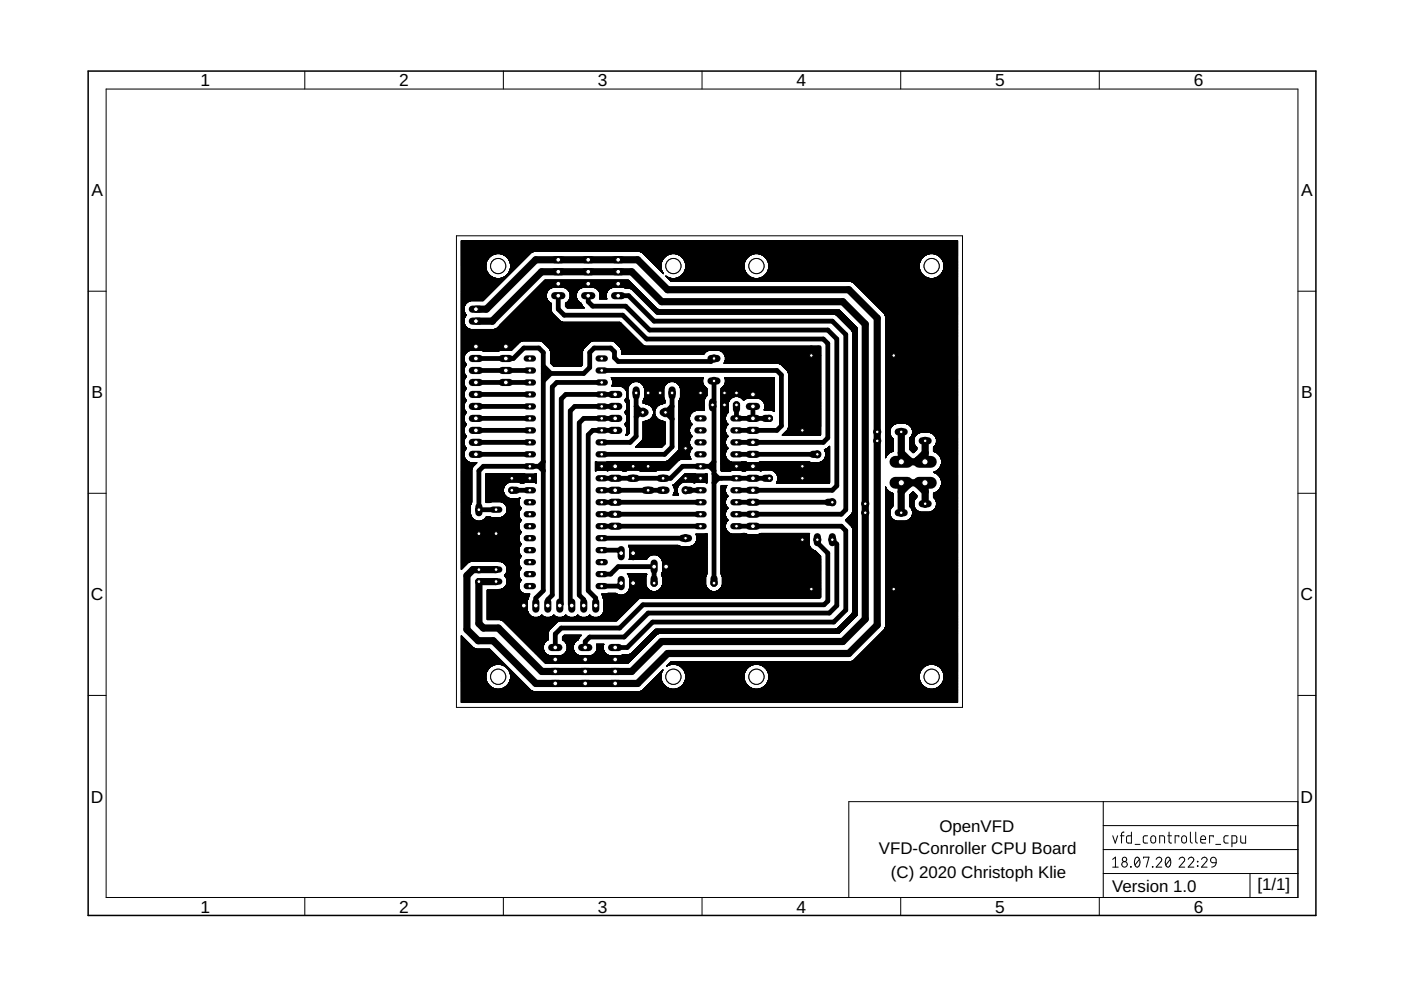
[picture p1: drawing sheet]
<svg xmlns="http://www.w3.org/2000/svg" width="297mm" height="210mm" viewBox="0 0 297 210" stroke-linecap="round" stroke-linejoin="round" font-family="sans-serif">
<defs><g id="words">
<g font-size="3.7">
<text x="42.5" y="18.3">1</text>
<text x="84.7" y="18.3">2</text>
<text x="126.8" y="18.3">3</text>
<text x="168.9" y="18.3">4</text>
<text x="211" y="18.3">5</text>
<text x="253.1" y="18.3">6</text>
<text x="19.4" y="41.6">A</text>
<text x="275.9" y="41.6">A</text>
<text x="19.4" y="84.5">B</text>
<text x="275.9" y="84.5">B</text>
<text x="19.3" y="127.3">C</text>
<text x="275.8" y="127.3">C</text>
<text x="19.3" y="170.2">D</text>
<text x="275.8" y="170.2">D</text>
<text x="42.5" y="193.5">1</text>
<text x="84.7" y="193.5">2</text>
<text x="126.8" y="193.5">3</text>
<text x="168.9" y="193.5">4</text>
<text x="211" y="193.5">5</text>
<text x="253.1" y="193.5">6</text>
</g>
<g font-size="3.6">
<text x="199.2" y="176.3">OpenVFD</text>
<text x="186.3" y="181.1">VFD-Conroller CPU Board</text>
<text x="188.9" y="186.2">(C) 2020 Christoph Klie</text>
<text x="235.8" y="189">Version 1.0</text>
<text x="266.6" y="188.7">[1/1]</text>
</g>
</g></defs>
<g fill="none" stroke="#000" stroke-width=".51">
<circle cx="105.6" cy="56.4" r=".76"/>
<circle cx="142.8" cy="56.4" r=".76"/>
<circle cx="160.3" cy="56.4" r=".76"/>
<circle cx="197.5" cy="56.4" r=".76"/>
<circle cx="105.6" cy="143.5" r=".76"/>
<circle cx="142.8" cy="143.5" r=".76"/>
<circle cx="160.4" cy="143.5" r=".76"/>
<circle cx="197.5" cy="143.4" r=".76"/>
</g>
<g fill="none" stroke="#000" stroke-width="1.5">
<path d="M100.9 68.1h3.5l10.4-10.5h19.1l6.4 6.4h38.4l4.8 4.7v62.6l-4.8 4.7h-38.4l-6.4 6.4h-19l-9.2-9.2h-3.2l-1-1v-8.9h3.7M100.9 65.6h2.2l10.5-10.5h21.6l6.3 6.3h38.5l6 6.1v65l-6 6.1h-38.5l-6.3 6.3h-21.6l-9-9.1h-3.2l-2.4-2.3v-11.5l1.3-1.2h4.9M118.4 60.2h12.7M150.7 76h1.3M133.6 98.9h1.3M134.9 82.7v1.2M135.8 87.4h1M136.8 98.9h1.2M137.4 82.7v1.2M140 82.7v1.2M140.6 87.4h.5M142.5 82.7v1.2"/>
<path d="M145.4 94.4v1.3M148.5 82.7v1.2M150.7 80.8h1.3M151.1 85.2v1.3M153.6 82.7v1.2M153.6 85.2v1.3M155.5 83.3h1.3M156.1 85.9v.9M162.2 88.7h.9M169.5 98.9h1.3M169.5 91.2h1.3M172.3 96.3h1"/>
<path d="M190.4 91.6h1.3M191.1 91.6h.1M191.1 91.6v6.3h5l.1-4.4M191.1 96l1.9 1.9M193 97.9h.1M195.5 93.5h1.3M196.2 96l-2 1.9M101.5 107.4v1.3M101.5 112.5v1.3M107.9 101.4h1.3M108.5 103.9h1M133.6 101.4h1.3"/>
<path d="M136.8 103.9h1.2M140 101.4h1.2M140 103.9h1.2M144.7 114.1h1.3M145.4 101.4h.9M145.4 103.9h.9M162.2 101.4h.9M169.5 101.4h1.3M170.1 113.8v1.3M173.3 113.8v1.3M175.5 106.5h1M176.5 113.8v1.3"/>
<path d="M190.4 108.7h1.3M193 102.4l-1.9 1.9M194.2 102.4l2 1.9M195.5 106.8h1.3M196.2 106.8l-.1-4.4h-5v6.3M117.7 139.8h12.7M138.7 122.7v.9M151.4 122.7v.9"/>
</g>
<g fill="none" stroke="#000" stroke-width="1">
<path d="M100.9 76h7.9l2.3-2.2h3.1l1 .9v50.5l-1.6 1.6v1.6M100.9 73.5h6.4M100.9 78.5h11.4M107.3 68.7h24.1l5.1 5.1h37.1v16.5l-.9 .9h-2.6M107.3 68.7l-4.8 4.8M115.2 77.6l1.6 1.6-1.6 1.6M118.4 62.7v2.9l1.2 1.2h12.4l5.1 5.1h37.5l.9 .9v20l-.9 1h-18.5M118.4 60.2h-2.6l-8.5 8.5M124.7 62.7v1.3l1 .9h7l5 5.1h37.8l1.9 1.9v31.1l-.9 .9h-20.4M127.6 78.5h37.1l1 1v10.8l-1 .9h-8.6M131.1 60.2h2.2l6 6h38.1l3.8 3.8v60.3l-3.5 3.5h-38.4l-6 6h-2.9M131.1 62.7h2.2l5.4 5.4h37.8l2.8 2.8v37.2l-.9 .9h-22.3"/>
<path d="M151.4 76l-.7 .6h-19.6l-.8-.7v-1.3l-.8-.8h-3.5l-1 .9v3.2l-1.2 1.3h-8.6M172 73.8v1.6M172 75.4h1.6M173 74.4l-1 1M100.9 91.2h11.4M100.9 88.7h11.4M100.9 81.1h11.4M100.9 96.3h11.4M100.9 93.8h11.4M100.9 86.2h11.4M100.9 83.6h11.4M114.2 98.9h-11.7l-1 .9v7.6"/>
<path d="M114.2 98.9l1 .9M115.2 97.9l-1 1M127.6 98.9h6M127.6 81.1h-9.6l-.9 .9v44.2l-1 .9v1.3M130.4 91.2h-4.7l-1 1v33l1.6 1.6v1.6M130.4 88.7h-6.6l-1 1v36.5l1 .9v1.3M130.4 86.2h-8.5l-1 .9v41l.3 .3M130.4 83.6h-10.4l-1 1v43.5l-.3 .3M134.9 98.9h1.9M134.9 83.9v8.6l-1.3 1.3h-6M134.9 86.2l1.4 1.2M135.8 87.4l-.9 1"/>
<path d="M137.4 83.3h2.6M137.7 83.3l1-.9 .9 .9M138.7 83.3v-1.9l.9-.9h4.8l1 .9v13.7l-3.9 3.8h-3.5M142.5 83.9v10.8l-1.6 1.6h-13.3M142.5 86.2l-1.4 1.2 1.4 1.4M145.4 82.4l.9 .9-.9 1M146 83.3h2.5M150.4 98.9h-5.7l-2.5 2.5h-1M150.4 98.9l1 .9M151.1 85.9l.3 .3M151.4 97.9l-1 1M151.4 80.8v41.9"/>
<path d="M151.4 85.2l-.3 .3M153.3 85.5l.3 .4-.3 .3M155.5 83.3h-1.9l-.3 .3v14.6l.6 .7h15.6M156.1 86.8v1.9h6.1M156.1 96.3h16.2M156.8 83.3h2.5l.3 .3M159.6 86.2v2.5M170.1 98.9v2.5M101.5 108.1h3.7M105.2 108.1h.1M107.5 113.1l1 1v18.7l7 7h2.2M107.5 113.1l-6 .1"/>
<path d="M108.2 101.4h-1.3l-1.2 1.3v2.2l2.8 2.9v4.1l-1 1v.2M109.2 101.4h3.1M109.5 103.9h2.8M127.6 101.4h6M127.6 106.5h20.9M127.6 109h20.9M127.6 111.6h20.9M127.6 103.9h9.2M127.6 114.1h17.1M127.6 116.6h3.5l.6 .7M134.2 101.4h5.8M134.2 117.3h5.8l1.2 1.3v6.9"/>
<path d="M138 103.9h2M146.3 101.4h2.2M146.3 103.9h2.2M151.4 100.5l.9 .9M152.3 101.4h9.9M152.3 101.4l-.9 1M156.1 106.5h19.4M156.1 111.6h22.3l.9 .9v16.8l-2.5 2.6h-38.4l-5.4 5.4h-2.6M170.1 115.1l3.5 3.5v7.9h-38.4M173.3 115.1l2.2 2.2v10.1l-.8 .8h-38.4l-4.9 5h-12.4l-1.3 1.2v2.9M176.5 114.4l.9 1v13l-1.6 1.6h-38.4l-5.1 5.1h-7.3l-.9 .9v1.3M108.5 128.4h2.6"/>
<path d="M108.5 127.4l1 1-1 .9M108.5 130.3l1 1M109.5 131.3l-1 .9M127.6 121.7h1.9l1.6-1.6h7.6v2.6M131.7 123.6l-.6 .7h-3.5M134.2 125.5l1 1M134.2 123.6v3.8M135.2 126.5l-4.8 4.8h-20.9M141.2 125.5l-.9 1M141.2 125.5l1 1M172 124.9h1.6M172 124.9v1.6"/>
<path d="M172 124.9l1.3 1.3v.3"/>
</g>
<g fill="none" stroke="#000" stroke-width=".21">
<path d="M97.8 59l9.3 .1M97.8 59h7.4M97.8 58.9h7.1M97.8 58.9h7M97.8 58.8h6.8M97.8 58.8h6.7M97.8 58.7h6.6M97.8 58.7h6.5M97.8 58.6h6.4M97.8 58.5l6.3 .1M97.8 58.5h6.2M97.8 58.4l6.2 .1"/>
<path d="M97.8 58.4h6.1M97.8 58.3l6.1 .1M97.8 58.3h6M97.8 58.2l6 .1M97.8 58.2h5.9M97.8 58.1l5.9 .1M97.8 58.1h5.8M97.8 58l5.8 .1M97.8 58h5.7M97.8 57.9l5.7 .1M97.8 57.9h5.6M97.8 57.8h5.6"/>
<path d="M97.8 57.7h5.6M97.8 57.7h5.5M97.8 57.6h5.5M97.8 57.5h5.4M97.8 57.4l5.4 .1M97.8 57.4h5.4M97.8 57.3l5.4 .1M97.8 57.3h5.3M97.8 57.2h5.3M97.8 57.1h5.3M97.8 57h5.3M97.8 56.9h5.2"/>
<path d="M97.8 56.8h5.2M97.8 56.7h5.2M97.8 56.6h5.2M97.8 56.5h5.2M97.8 56.4h5.2M97.8 56.3h5.2M97.8 56.2h5.2M97.8 56.1h5.2M97.8 56h5.2M97.8 55.9h5.2M97.8 55.8h5.3M97.8 55.6h5.3"/>
<path d="M97.8 55.4h5.4M97.8 55.3h5.4M97.8 55.2h5.5M97.8 55h5.6M97.8 53.3h105.2M97.8 53.2h105.2M97.8 53.1h105.2M97.8 53h105.2M97.8 52.9h105.2M97.8 52.8h105.2M97.8 52.7h105.2M97.8 52.6h105.2"/>
<path d="M97.8 52.5h105.2M97.8 52.4h105.2M97.8 52.3h105.2M97.8 52.2h105.2M97.8 52.1h105.2M97.8 52h105.2M97.8 51.9h105.2M97.8 51.8h105.2M97.8 51.7h105.2M97.8 51.6h105.2M97.8 51.5h105.2M97.8 51.4h105.2"/>
<path d="M97.8 51.3h105.2M97.8 51.2h105.2M97.8 51.1h105.2M103 56.1v.7M103 56.8l.2 .6 .8 1.1M103 56h-5.2M103.1 55.9h-5.3M103.1 55.7h-5.3M103.1 55.5l-5.3 .1M103.2 55.5h-5.4M103.2 55.4h-5.4M103.3 55.3h-5.5"/>
<path d="M103.3 55.2h-5.5M103.3 55.1h-5.5M103.4 55.1h-5.6M103.4 54.9l-5.6 .1M103.5 54.9h-5.7M103.5 54.8l-5.7 .1M103.5 54.8l-.5 1.3M103.5 54.8h-5.7M103.6 54.7l-5.8 .1M103.6 54.7h-5.8M103.7 54.6l-5.9 .1M103.7 54.6h-5.9"/>
<path d="M103.8 54.5l-6 .1M103.8 54.5h-6M103.9 54.4l-6.1 .1M103.9 54.4h-6.1M104 54.3l-.5 .5M104 58.5l1.3 .6M104 54.3l-6.2 .1M104.1 54.3h-6.3M104.2 54.2l-6.4 .1M104.3 54.2h-6.5M104.4 54.1h-6.6M104.5 54l-6.7 .1"/>
<path d="M104.6 54h-6.8M104.8 53.9l-7 .1M104.9 53.9h-7.1M105.1 53.8l-7.3 .1M105.3 53.8l-1.3 .5M106 53.8l1.2 .5M106.1 53.8h6.2M106.2 60h-8.4M106.2 59.9l-8.4 .1M106.3 59.9h-8.5M106.3 53.9h6M106.4 59.8l-8.6 .1"/>
<path d="M106.4 59.8h-8.6M106.4 59.7l-8.6 .1M106.5 59.7h-8.7M106.5 53.9h5.7M106.6 59.6h-8.8M106.7 59.5h-8.9M106.7 54h5.5M106.7 54h5.4M106.8 59.4h-9M106.8 58.7h.6M106.8 54.1h5.3M106.9 59.3h-9.1"/>
<path d="M106.9 59.2l-9.1 .1M107 54.2h5M107 59.2h-9.2M107 59.1l-9.2 .1M107.1 54.2h4.9M107.1 59.1h-9.3M107.2 54.3h4.7M107.2 59h-1.1M107.2 54.3l.9 1.1M107.2 58.5l-1.2 .6M107.2 54.3h4.6M107.3 58.9h-1"/>
<path d="M107.3 54.4h4.5M107.3 58.9h-.8M107.3 58.8h-.6M107.4 58.8h-.7M107.4 54.5h4.3M107.4 54.5h4.2M107.5 58.7h-.6M107.5 54.6h4.1M107.5 54.6h4M107.6 58.6h-.6M107.6 54.7h3.9M107.6 58.5l-.5 .1"/>
<path d="M107.7 58.5h-.5M107.7 54.7h3.7M107.7 58.4l-.4 .1M107.7 54.8h3.7M107.8 58.4h-.5M107.8 54.9h3.5M107.8 54.9h3.4M107.8 58.3l-.4 .1M107.8 55h3.3M107.9 57.8h.5M107.9 55.1h3.2M107.9 58.3h-.5"/>
<path d="M107.9 55.2h3.1M107.9 58.2l-.4 .1M108 58.2h-.5M108 55.2h2.9M108 55.3h2.9M108 58.1l-.4 .1M108.1 55.4h2.7M108.1 55.4l.1 .7M108.1 57.4l-.9 1.1M108.1 58.1h-.4M108.1 55.4h2.6M108.1 58l-.4 .1"/>
<path d="M108.1 55.7h2.4M108.2 55.8h2.2M108.2 58h-.5M108.2 56h2M108.2 56.1v.7M108.2 56.8l-.1 .6M108.3 57.9l-.5 .1M108.3 57.9h-.5M108.4 57.8h-.6M108.5 57.7h-.6M108.6 57.6h-.7M108.6 57.6h-.6"/>
<path d="M108.7 57.5h-.7M108.7 57.4l-.6 .1M108.8 57.4h-.7M108.8 57.3l-.7 .1M108.9 57.3h-.8M108.9 57.2l-.8 .1M109 57.2h-.9M109 57.1h-.9M109.1 57.1h-.9M109.2 57h-1M109.2 56.9h-1M109.3 56.9h-1.1"/>
<path d="M109.3 56.8h-1.1M109.4 56.7l-1.2 .1M109.5 56.7h-1.3M109.5 56.6l-1.3 .1M109.6 56.6h-1.4M109.6 56.5l-1.4 .1M109.7 56.5h-1.5M109.7 56.4l-1.5 .1M109.8 56.4h-1.6M109.9 56.3l-1.7 .1M109.9 56.3h-1.7M109.9 56.2l-1.7 .1"/>
<path d="M110 56.2h-1.8M110 56.1l-1.8 .1M110.1 56.1h-1.9M110.2 56h-2M110.3 55.9h-2.1M110.4 55.8h-2.2M110.5 55.6l-2.4 .1M110.6 55.6h-2.5M110.6 55.5l-2.5 .1M110.7 55.5h-2.6M110.8 55.3l-2.8 .1M111.3 54.8l-3.5 .1"/>
<path d="M112.4 53.8h-14.6M112.5 53.7l-14.7 .1M112.5 53.7h-14.7M112.5 53.6l-14.7 .1M112.6 53.6h-14.8M112.6 53.6l-10.2 10.2h-4.6M112.7 53.5l-14.9 .1M112.9 53.5h-15.1M113 53.4h-15.2M113.1 53.4h-15.3M113.3 53.3l-.7 .3M115 60h18.8"/>
<path d="M115 59.9h18.7M115.1 59.9h18.6M115.1 59.8h18.5M115.2 59.8h18.4M115.3 59.7h18.2M115.3 59.6h18.2M115.4 59.6h18M115.4 59.5h17.9M115.5 59.5h17.8M115.5 59.4h17.7M135.6 53.3l.6 .3M135.7 53.4h67.3"/>
<path d="M135.8 53.4h67.2M136 53.5h67M136.1 53.5h66.9M136.2 53.6l4.5 4.4M136.2 53.6h66.8M136.3 53.7h66.7M136.4 53.7h66.6M136.4 53.8h66.6M136.5 53.8h5.8M136.5 53.9h5.5M136.6 53.9h5.3M136.6 54h5.1"/>
<path d="M136.7 54h4.9M136.7 54.1h4.8M136.8 54.2h4.6M136.8 54.2h4.5M136.9 54.3h4.3M137 54.4h4.1M137.1 54.4h4M137.1 54.5h3.9M137.2 54.5h3.7M137.2 54.6h3.7M137.3 54.6h3.5M137.3 54.7h3.5"/>
<path d="M137.4 54.7h3.3M137.4 54.8h3.3M137.5 54.8h3.1M137.5 54.9h3.1M137.6 54.9h3M137.6 55h2.9M137.7 55.1h2.8M137.8 55.1h2.7M137.8 55.2h2.7M137.9 55.2h2.5M137.9 55.3h2.5M138 55.3h2.4"/>
<path d="M138 55.4h2.3M138.1 55.4h2.2M138.1 55.5h2.2M138.2 55.5h2.1M138.2 55.6h2.1M138.3 55.6h2M138.3 55.7h2M138.4 55.8h1.8M138.5 55.9h1.7M138.6 56h1.6M138.7 56.1h1.4M138.8 56.2h1.3"/>
<path d="M138.9 56.2h1.2M138.9 56.3h1.2M139 56.3h1.1M139 56.4h1.1M139.1 56.4h1M139.1 56.5h1M139.2 56.5h.9M139.2 56.6h.9M139.3 56.6h.8M139.3 56.7h.8M139.4 56.7h.7M139.4 56.8h.8"/>
<path d="M139.5 56.9h.7M139.6 56.9h.6M139.6 57h.6M139.7 57h.5M139.7 57.1h.5M139.8 57.1h.5M139.8 57.2h.5M139.9 57.2h.4M139.9 57.3h.4M140 57.3h.3M140 57.4h.3M140.1 57.4h.2"/>
<path d="M140.1 57.5h.3M140.1 56.1v.7M140.1 56.8l.2 .6M140.2 57.6h.2M140.3 57.7h.2M140.3 57.4l.4 .6M140.4 57.8h.1M140.4 57.8h.2M140.5 57.9h.1M140.7 58h.1M140.7 54.8l-.6 1.3M141.2 54.3l-.5 .5"/>
<path d="M141.2 58.5l.1 .1M141.2 58.6h.2M141.3 58.7h.2M141.4 58.7h.1M141.4 58.8h.2M141.5 58.8h.2M141.5 58.9h.4M141.6 58.9h.5M141.6 59h.7M141.7 59l61.3 .1M141.7 59.1h61.3M141.8 59.1h61.2"/>
<path d="M141.8 59.2h61.2M141.9 59.2h61.1M141.9 59.3h61.1M142 59.4h61M142.1 59.5h60.9M142.2 59.6h60.8M142.4 59.1l-1.2-.6 1 1.1h60.8M142.4 53.8l-1.2 .5M143.1 53.8l1.3 .5M143.2 59h16.7M143.3 53.8h16.6M143.4 58.9h16.3"/>
<path d="M143.5 53.9h16.2M143.6 58.9h15.9M143.6 53.9h15.9M143.8 58.8h15.5M143.8 54h15.5M143.9 58.8h15.4M143.9 54h15.4M144 58.7h15.2M144 54.1h15.2M144.1 58.7h15M144.1 54.2h14.9M144.2 58.6h14.8"/>
<path d="M144.2 54.2h14.7M144.3 58.6h14.6M144.3 54.3h14.5M144.4 58.5l-1.3 .6M144.4 54.3l.5 .5M144.4 58.5h14.4M144.4 54.3h14.4M144.4 58.5h14.3M144.4 54.4h14.3M144.5 58.4h14.2M144.5 54.4h14.2M144.5 58.4h14.1"/>
<path d="M144.5 54.5h14.1M144.6 58.3h14M144.6 54.5h14M144.6 58.3h13.9M144.7 54.6h13.8M144.7 58.2h13.8M144.7 58.2h13.7M144.8 54.7h13.6M144.8 58.1h13.5M144.8 54.7h13.5M144.9 54.8l.5 1.3M144.9 54.8h13.4"/>
<path d="M144.9 58h13.4M144.9 54.8h13.3M144.9 58h13.3M144.9 57.9h13.3M144.9 54.9h13.3M145 57.8h13.2M145 55h13.2M145 57.8h13.1M145 55.1h13.1M145 57.7h13.1M145.1 55.1h13M145.1 57.7h13"/>
<path d="M145.1 57.6h13M145.1 57.6h12.9M145.2 57.5h12.8M145.2 55.3h12.8M145.2 57.5h12.7M145.2 55.4h12.7M145.2 57.4l-.8 1.1M145.2 57.4h12.7M145.2 57.3h12.7M145.2 55.5h12.7M145.3 57.2h12.6M145.3 57.1h12.6"/>
<path d="M145.3 55.6h12.6M145.3 57.1h12.5M145.3 57h12.5M145.3 55.9h12.5M145.3 55.8h12.5M145.4 56.9h12.4M145.4 56.8h12.4M145.4 56h12.4M145.4 56.8l-.2 .6M145.4 56.1v.7M145.4 56.7h12.4M145.4 56.6h12.4"/>
<path d="M145.4 56.5h12.4M145.4 56.4h12.4M145.4 56.3h12.4M145.4 56.2h12.4M145.4 56.1h12.4M157.8 56.1v.7M157.8 56.8l.1 .6M157.8 56h-12.4M157.8 55.9h-12.4M157.8 55.8h-12.5M157.9 55.7h-12.6M157.9 55.6h-12.6"/>
<path d="M157.9 57.4l.9 1.1M157.9 55.4l-12.7 .1M158 55.3h-12.9M158 55.2h-12.9M158.1 55.2h-13M158.2 54.9h-13.3M158.3 54.8l-.5 1.3M158.8 54.3l-.5 .5M158.8 58.5l1.2 .6M160 53.8l-1.2 .5M160.7 53.8l1.3 .5M160.8 59h36.3"/>
<path d="M160.9 53.8h36.1M161.1 58.9h35.7M161.1 53.9h35.7M161.2 58.9h35.5M161.2 53.9h35.5M161.4 58.8h35.1M161.4 54h35.1M161.5 58.8h34.9M161.5 54h34.9M161.6 58.7h34.7M161.6 54.1h34.7M161.7 58.7h34.5"/>
<path d="M161.7 54.2h34.5M161.8 58.6h34.3M161.8 54.2h34.3M161.9 58.6h34.1M161.9 54.3h34.1M162 54.3l.5 .5M162 58.5l-1.3 .6M162 58.5h33.9M162 54.3h33.9M162.1 54.4h33.8M162.1 58.4h33.7M162.1 54.4h33.7"/>
<path d="M162.2 54.5h33.5M162.2 58.3h33.5M162.3 54.6h33.3M162.3 58.2h33.3M162.4 54.7h33.1M162.4 58.1h33.1M162.5 54.8l.3 .6M162.5 54.8h32.9M162.5 58h32.9M162.5 54.9h32.8M162.6 57.9h32.7M162.6 54.9h32.7"/>
<path d="M162.6 57.8h32.7M162.6 55h32.7M162.6 55.1h32.7M162.6 57.7h32.7M162.7 57.7h32.5M162.7 57.6h32.5M162.8 57.6h32.4M162.8 55.3h32.4M162.8 57.5h32.3M162.8 57.4l32.3 .1M162.8 55.4l.2 .7M162.8 57.4l-.8 1.1"/>
<path d="M162.8 57.4h32.3M162.8 55.4h32.3M162.9 57.3h32.1M162.9 55.5h32.1M162.9 57.2h32.1M162.9 57.1h32.1M162.9 55.7h32.1M162.9 55.6h32.1M162.9 57h32.1M162.9 55.8h32.1M162.9 57h32M162.9 55.9h32"/>
<path d="M163 56.9h31.9M163 55.9h31.9M163 56.8h31.9M163 56h31.9M163 56.1v.7M163 56.8l-.2 .6M163 56.7l31.9 .1M163 56.7h31.9M163 56.6h31.9M163 56.5h31.9M163 56.4h31.9M163 56.3h31.9"/>
<path d="M163 56.2h31.9M163 56.1h31.9M180.3 59.6l.7 .3M180.4 59.7h22.6M180.5 59.7h22.5M180.6 59.8h22.4M180.7 59.8h22.3M180.9 59.9h22.1M181 59.9l.5 .5M181 59.9h22M181 60h22M194.9 56.1v.7"/>
<path d="M194.9 56.8l.2 .6M195 55.8h-32.1M195 55.6h-32.1M195.1 55.5h-32.2M195.1 57.4l.3 .6M195.1 55.4h-32.3M195.1 55.3l-32.3 .1M195.2 55.2h-32.5M195.2 55.1h-32.5M195.4 54.8l-.5 1.3M195.4 58l.5 .5M195.9 54.3l-.5 .5"/>
<path d="M195.9 58.5l1.3 .6M197.2 53.8l-1.3 .5M197.9 53.8l1.2 .5M198 59h5M198 53.8h5M198.2 58.9h4.8M198.2 53.9h4.8M198.4 58.9h4.6M198.4 53.9h4.6M198.6 58.8h4.4M198.6 54h4.4M198.8 58.7h4.2"/>
<path d="M198.8 54.1h4.2M198.9 54.2h4.1M198.9 58.6h4.1M199 58.6h4M199.1 54.3h3.9M199.1 58.5h3.9M199.1 54.3l.5 .5M199.1 58.5l-1.2 .6M199.2 58.5h3.8M199.2 54.4h3.8M199.2 58.4h3.8M199.3 58.4h3.7"/>
<path d="M199.3 54.5h3.7M199.3 58.3h3.7M199.4 58.3h3.6M199.4 54.6h3.6M199.5 58.2h3.5M199.5 54.6h3.5M199.5 54.7h3.5M199.5 58.1h3.5M199.6 58.1h3.4M199.6 54.8h3.4M199.6 54.8l.6 1.3M199.6 58h3.4"/>
<path d="M199.7 57.9h3.3M199.7 54.9h3.3M199.7 57.8h3.3M199.7 55h3.3M199.8 57.8h3.2M199.8 55.1h3.2M199.8 57.7h3.2M199.8 55.2h3.2M199.9 57.6h3.1M199.9 55.2h3.1M199.9 55.3h3.1M199.9 57.5h3.1"/>
<path d="M199.9 55.4h3.1M200 57.4l-.9 1.1M200 57.4h3M200 57.3h3M200 55.5h3M200 55.4h3M200 57.2h3M200 55.6h3M200 57.1h3M200 55.7h3M200.1 57h2.9M200.1 55.8h2.9"/>
<path d="M200.1 55.9h2.9M200.1 56.9h2.9M200.1 56h2.9M200.1 56.8h2.9M200.2 56.1v.7M200.2 56.8l-.2 .6M200.2 56.7h2.8M200.2 56.6h2.8M200.2 56.5h2.8M200.2 56.4h2.8M200.2 56.3h2.8M200.2 56.2h2.8"/>
<path d="M200.2 56.1h2.8M203 53.3h-105.2M97.8 69.8l35.1 .1M97.8 65.7h.6M97.8 66.5l.9 .1M97.8 65.3h.6M97.8 68.3h.6M97.8 77l.9 .1M97.8 72.3h37.6M97.8 79.8h1.1M97.8 79.7h1M97.8 79.6h.9"/>
<path d="M97.8 79.5l.9 .1M97.8 79.5h.8M97.8 79.4h.8M97.8 79.3h.8M97.8 79.3h.7M97.8 79.2h.7M97.8 79.1h.7M97.8 79.1h.6M97.8 79h.6M97.8 78.9h.6M97.8 78.8h.6M97.8 78.7h.6"/>
<path d="M97.8 78.6h.6M97.8 78.5h.6M97.8 78.4h.6M97.8 78.3h.6M97.8 78.2h.6M97.8 78.1h.6M97.8 78h.7M97.8 77.9h.7M97.8 77.7h.8M97.8 77.3h1.1M97.8 77.2h1.1M97.8 77.2h1"/>
<path d="M97.8 77.1h.9M97.8 77h.9M97.8 76.9l.8 .1M97.8 76.9h.8M97.8 76.8h.8M97.8 76.7h.7M97.8 76.6h.7M97.8 76.5h.6M97.8 76.4h.6M97.8 76.3h.6M97.8 76.2h.6M97.8 76.1h.6"/>
<path d="M97.8 76h.6M97.8 75.9h.6M97.8 75.8h.6M97.8 75.7h.6M97.8 75.6h.6M97.8 75.5h.6M97.8 75.5h.7M97.8 75.4h.7M97.8 75.3h.7M97.8 75.2h.8M97.8 72.2l37.5 .1M97.8 72.2h37.5"/>
<path d="M97.8 72.1l37.4 .1M97.8 72.1h37.3M97.8 72l37.3 .1M97.8 72h37.2M97.8 71.9h37.2M97.8 71.9h37.1M97.8 71.8h37.1M97.8 71.8h37M97.8 71.7h37M97.8 71.6l36.9 .1M97.8 71.6h36.9M97.8 71.5l36.8 .1"/>
<path d="M97.8 71.5h36.8M97.8 71.4l36.7 .1M97.8 71.4h36.7M97.8 71.3l36.6 .1M97.8 71.3h36.6M97.8 71.2h36.5M97.8 71.1h36.4M97.8 71h36.3M97.8 71h36.2M97.8 70.9h36.2M97.8 70.8l36.1 .1M97.8 70.8h36.1"/>
<path d="M97.8 70.7l36 .1M97.8 70.7h36M97.8 70.6l35.9 .1M97.8 70.6h35.9M97.8 70.5l35.8 .1M97.8 70.5h35.8M97.8 70.4l35.7 .1M97.8 70.4h35.7M97.8 70.3l35.6 .1M97.8 70.3h35.5M97.8 70.2l35.5 .1M97.8 70.2h35.4"/>
<path d="M97.8 70.1h35.4M97.8 70.1h35.3M97.8 70h35.3M97.8 70h35.2M97.8 69.9h35.2M97.8 69.8h1.9M97.8 69.7l1.8 .1M97.8 69.7h1.7M97.8 69.6l1.5 .1M97.8 69.6h1.4M97.8 69.5l1.3 .1M97.8 69.5h1.3"/>
<path d="M97.8 69.4h1.2M97.8 69.3h1.1M97.8 69.2h1M97.8 69.2h.9M97.8 69.1h.9M97.8 69l.9 .1M97.8 69h.8M97.8 68.9l.8 .1M97.8 68.9h.8M97.8 68.8l.8 .1M97.8 68.8h.7M97.8 68.7h.7"/>
<path d="M97.8 68.6h.7M97.8 68.6h.6M97.8 68.5h.6M97.8 68.4l.6 .1M97.8 68.4h.6M97.8 68.2h.6M97.8 68.1h.6M97.8 68h.6M97.8 67.9h.6M97.8 67.8h.6M97.8 67.7h.6M97.8 67.6h.6"/>
<path d="M97.8 67.5h.7M97.8 66.8h1.1M97.8 66.7h1M97.8 66.6h.9M97.8 66.5h.8M97.8 66.4l.8 .1M97.8 66.4h.8M97.8 66.3l.8 .1M97.8 66.3h.8M97.8 66.2l.7 .1M97.8 66.2h.7M97.8 66.1l.7 .1"/>
<path d="M97.8 66.1h.7M97.8 66l.6 .1M97.8 66h.6M97.8 65.9l.6 .1M97.8 65.9h.6M97.8 65.8h.6M97.8 65.6h.6M97.8 65.5h.6M97.8 65.4h.6M97.8 65.2h.6M97.8 64.6h.8M98.4 65.2v.7"/>
<path d="M98.4 67.7v.7M98.4 75.7v.7M98.4 78.2v.7M98.4 65.9l.5 .9M98.4 68.4l.2 .7M98.4 76.4l.2 .6M98.4 78.9l.5 .9M98.4 65.2h-.6M98.4 67.7h-.6M98.4 65.1l-.6 .1M98.4 65.1h-.6M98.4 67.6h-.6"/>
<path d="M98.4 65h-.6M98.5 65h-.7M98.5 67.5h-.7M98.5 64.9h-.7M98.5 77.9h-.7M98.5 75.4h-.7M98.5 67.4h-.7M98.5 64.8h-.7M98.6 77.8h-.8M98.6 75.2l-.8 .1M98.6 67.3h-.8M98.6 64.7l-.8 .1"/>
<path d="M98.6 67.2l-.8 .1M98.6 64.7h-.8M98.6 75.1l-.8 .1M98.6 77.7h-.8M98.6 67.2h-.8M98.6 64.6l-.8 .1M98.6 77.6l-.8 .1M98.6 75.1h-.8M98.6 67.1l-.8 .1M98.6 64.5l-.2 .7M98.6 69.1l.5 .5 .7 .2M98.6 77l.3 .3"/>
<path d="M98.6 77.6h-.8M98.6 75l-.8 .1M98.6 67.1h-.8M98.6 64.5l-.8 .1M98.7 77.5l-.9 .1M98.7 75h-.9M98.7 67l-.9 .1M98.7 64.5h-.9M98.7 77.5h-.9M98.7 74.9l-.9 .1M98.7 67h-.9M98.7 64.4l-.9 .1"/>
<path d="M98.8 80h-1M98.8 77.4h-1M98.8 74.9h-1M98.8 79.9h-1M98.8 66.9l-1 .1M98.8 64.4h-1M98.8 74.8l-1 .1M98.8 66.9h-1M98.9 79.9h-1.1M98.9 77.3h-1.1M98.9 74.8h-1.1M98.9 64.3l-1.1 .1"/>
<path d="M98.9 66.8l-1.1 .1M98.9 64.3h-1.1M98.9 66.8l-.5 .9M98.9 77.3l-.5 .9M98.9 79.8l-.3 .3M98.9 74.7l-1.1 .1M99 64.2l-1.2 .1M99 74.7h-1.2M99 64.2h-1.2M99.1 74.6l-1.3 .1M99.1 64.1l-1.3 .1M99.1 74.6h-1.3"/>
<path d="M99.1 64.1h-1.3M99.2 74.5h-1.4M99.2 64l-1.4 .1M99.3 74.5h-1.5M99.3 64h-1.5M99.4 74.4h-1.6M99.5 63.9h-1.7M99.5 74.4h-1.7M99.6 63.9h-1.8M99.7 74.3h-1.9M99.7 63.8h-1.9M99.8 63.8l-.7 .2-.5 .5"/>
<path d="M99.8 74.3l-.7 .2-.5 .5-.2 .7M102 74.3l.6 .2h2.9l.7-.2M102.1 74.3h3.9M102.3 74.4h3.6M102.4 74.4h3.4M102.5 63.7h-4.7M102.5 63.6l-4.7 .1M102.6 74.5h3M102.6 63.6h-4.8M102.6 63.5l-4.8 .1M102.7 63.5h-4.9M102.7 63.4l-4.9 .1"/>
<path d="M102.8 63.4h-5M102.8 63.3l-5 .1M102.9 63.3h-5.1M102.9 63.2h-5.1M103 63.2h-5.2M103.1 63.1h-5.3M103.1 63h-5.3M103.2 62.9l-5.4 .1M103.3 62.9h-5.5M103.3 62.8l-5.5 .1M103.4 62.8h-5.6M103.4 62.7l-5.6 .1"/>
<path d="M103.5 62.7h-5.7M103.5 62.6l-5.7 .1M103.6 62.6h-5.8M103.6 62.5l-5.8 .1M103.7 62.5h-5.9M103.8 62.4l-6 .1M103.8 62.4h-6M103.8 62.3l-6 .1M103.9 62.3h-6.1M103.9 62.2l-6.1 .1M104 62.2h-6.2M104.1 62.1h-6.3"/>
<path d="M104.2 62h-6.4M104.3 61.9h-6.5M104.3 61.8l-6.5 .1M104.4 61.8h-6.6M104.4 61.7l-6.6 .1M104.5 61.7h-6.7M104.5 61.6l-6.7 .1M104.6 61.6h-6.8M104.6 61.5l-6.8 .1M104.7 61.5h-6.9M104.7 61.4h-6.9M104.8 61.4h-7"/>
<path d="M104.8 69.8h28.1M104.8 61.3h-7M104.9 61.3h-7.1M105 69.8h27.8M105 61.2h-7.2M105.1 61.1h-7.3M105.1 69.7h27.7M105.1 61l-7.3 .1M105.2 61h-7.4M105.2 69.7h27.5M105.2 60.9l-7.4 .1M105.3 60.9h-7.5"/>
<path d="M105.3 69.6h27.4M105.3 60.8l-7.5 .1M105.4 60.8h-7.6M105.4 69.6h27.2M105.4 60.7l-7.6 .1M105.5 69.5h27.1M105.5 60.7h-7.7M105.5 69.4h27M105.5 60.6l-7.7 .1M105.6 69.4h26.9M105.6 60.6h-7.8M105.6 69.3h26.8"/>
<path d="M105.7 60.5l-7.9 .1M105.7 69.3h26.7M105.7 60.5h-7.9M105.7 69.2h26.6M105.7 60.4h-7.9M105.8 69.2h26.4M105.8 60.3l-8 .1M105.9 69.1h26.3M105.9 60.3h-8.1M105.9 69.1l-.5 .5-.6 .2M105.9 69.1h26.2M105.9 69h26.2"/>
<path d="M105.9 60.2l-8.1 .1M106 69h26M106 60.2h-8.2M106 68.9h26M106 60.1l-8.2 .1M106.1 68.9h25.8M106.1 60.1h-8.3M106.1 68.8h25.8M106.1 60l-8.3 .1M106.2 68.8h25.6M106.2 68.7h25.6M106.3 68.7h25.4"/>
<path d="M106.3 68.6h25.4M106.4 68.6h25.2M106.4 68.5h25.2M106.5 68.5h25M106.6 68.4h24.8M106.6 68.3h24.8l4.8 4.9 .6 .2M106.7 68.3h12.5M106.7 68.2h12.4M106.8 68.2h12.2M106.8 68.1h12.1M106.9 68.1h11.8M106.9 68h11.8"/>
<path d="M107 68h11.7M107 67.9h11.6M107.1 67.9h11.4M107.1 67.8h11.4M107.2 67.8h11.2M107.2 67.7h11.2M107.3 67.6h11M107.4 67.5h10.8M107.5 67.4h10.6M107.6 67.3h10.4M107.7 67.3h10.3M107.7 67.2h10.2"/>
<path d="M107.8 67.2h10.1M107.8 67.1h10M107.9 67.1h9.9M107.9 67h9.8M108 67h9.6M108 66.9h9.6M108.1 66.9h9.4M108.1 66.8h9.4M108.2 66.7h9.2M108.3 66.6h9M108.4 66.6h8.9M108.4 74.3h.1"/>
<path d="M108.4 66.5h8.8M108.5 74.3h-10.7M108.5 66.5h8.7M108.5 74.2h-10.7M108.5 66.4h8.6M108.6 74.1l-10.8 .1M108.6 66.4h8.5M108.6 74.1h-10.8M108.6 66.3h8.5M108.7 74l-10.9 .1M108.7 66.3h8.3M108.7 74h-10.9"/>
<path d="M108.7 66.2h8.3M108.8 73.9l-11 .1M108.8 66.2h8.2M108.8 73.9h-11M108.8 66.1h8.1M108.9 73.8l-11.1 .1M108.9 66.1h8M108.9 73.8h-11.1M108.9 66h8M109 73.7h-11.2M109 66h7.9M109.1 73.7h-11.3"/>
<path d="M109.1 65.9h7.8M109.1 73.6h-11.3M109.1 65.8h7.8M109.2 73.6h-11.4M109.2 65.8h7.6M109.2 65.7h7.6M109.2 73.5h-11.4M109.3 73.4l-11.5 .1M109.3 65.7h7.5M109.3 73.4h-11.5M109.3 65.6h7.5M109.4 73.3l-11.6 .1"/>
<path d="M109.4 65.6h7.4M109.4 73.3h-11.6M109.4 65.5h7.4M109.5 73.2l-11.7 .1M109.5 65.5h7.3M109.5 65.4h7.3M109.5 73.2h-11.7M109.6 73.1l-11.8 .1M109.6 65.4h7.2M109.6 65.3h7.2M109.6 73.1h-11.8M109.7 73h-11.9"/>
<path d="M109.7 65.3h7.1M109.7 65.2h7.1M109.8 72.9l-12 .1M109.8 72.9l-1.4 1.4M109.8 72.9h-12M109.8 65.2h7M109.8 65.1h7M109.9 72.9h-12.1M109.9 72.8h-12.1M109.9 65h6.9M110 72.7l-12.2 .1M110 72.7h-12.2"/>
<path d="M110 64.9h6.8M110.1 72.6l-12.3 .1M110.1 72.6h-12.3M110.1 64.8h6.7M110.2 64.8h6.6M110.2 72.5l-12.4 .1M110.2 64.7h6.6M110.2 72.5h-12.4M110.3 64.7h6.5M110.3 64.6h6.5M110.4 64.6h6.4M110.4 72.4l-12.6 .1"/>
<path d="M110.4 64.5h6.4M110.5 64.5h6.3M110.5 72.4h-12.7M110.5 64.4h6.3M110.6 64.4h6.2M110.6 64.3h6.2M110.7 72.3l-12.9 .1M110.7 64.3h6.1M110.7 64.2h5.9M110.8 72.3l-.6 .2-.4 .4M110.8 64.2h5.8M110.8 64.1h5.7"/>
<path d="M110.9 64.1h5.6M111 64h5.4M111 63.9h5.4M111.1 63.9h5.2M111.1 63.8h5.2M111.2 63.8h5M111.2 63.7h4.9M111.3 63.7h4.8M111.3 63.6h4.8M111.4 63.6h4.7M111.4 63.5h4.6M111.5 63.5h4.5"/>
<path d="M111.5 63.4h4.5M111.6 63.4h4.4M111.6 63.3h4.4M111.7 63.2h4.2M111.8 63.1h4.1M111.9 63h3.9M112 63h3.8M112 62.9h3.8M112.1 62.9h3.7M112.1 62.8h3.7M112.2 62.8h3.6M112.2 62.7h3.6"/>
<path d="M112.3 62.7h3.5M112.3 62.6h3.5M112.4 62.6h3.4M112.4 62.5h3.4M112.5 62.5h3.3M112.5 62.4h3.3M114 60.9h20.7M114.1 60.9h20.6M114.1 60.8h20.5M114.2 60.8h20.4M114.2 60.7h20.3M114.3 60.7h20.2"/>
<path d="M114.3 60.6h20.1M114.4 60.6h20M114.4 60.5h19.9M114.5 60.4h19.7M114.5 72.3l.6 .2 1.4 1.4 .2 .5M114.6 60.4h19.6M114.6 60.3h19.5M114.6 72.3h11M114.7 60.3h19.4M114.7 60.2h19.3M114.8 60.2h19.2M114.8 72.4h10.6"/>
<path d="M114.8 60.1h19.1M114.9 60.1h19M114.9 72.4h10.4M114.9 60h18.9M115.1 72.5h10.1M115.1 72.5h10M115.2 72.6h9.8M115.3 72.7h9.6M115.4 72.8h9.4M115.4 72.9h9.4M115.5 72.9h9.2M115.5 73h9.2"/>
<path d="M115.6 73h9M115.7 73.1h8.9M115.7 73.1h8.8M115.8 73.2h8.7M115.8 63l.3 .7 .5 .5M115.8 73.2h8.6M115.8 62.3l-3.2 .1M115.9 62.3h-3.3M115.9 73.3h8.4M115.9 62.2l-3.2 .1M115.9 62.2h-3.1M115.9 62.1h-3.1"/>
<path d="M116 62.1h-3.1M116 62h-3.1M116 73.4h8.2M116 62h-3M116 61.9h-3M116 61.8l-2.9 .1M116.1 61.8h-3M116.1 61.7l-2.9 .1M116.1 61.7l-.3 .6v.7M116.1 73.5h8M116.1 61.7h-2.9M116.1 73.6h8"/>
<path d="M116.1 61.6l-2.8 .1M116.2 73.6h7.8M116.2 61.6h-2.9M116.2 73.7h7.8M116.3 61.5l-2.9 .1M116.3 73.7h7.6M116.3 61.5h-2.9M116.4 73.8h7.5M116.4 61.4h-2.9M116.4 73.8h7.4M116.5 73.9h7.3M116.5 61.3h-2.9"/>
<path d="M116.5 73.9h7.2M116.5 74h7.2M116.6 74.1h7.1M116.6 74.1h7M116.6 61.2h-2.9M116.6 64.2l.2 .1M116.6 74.2h7M116.6 74.3h7M116.7 74.4h6.8M116.7 61.2h-3M116.7 75.1h6.8M116.7 77l.7 .7h5.7l.4-.4"/>
<path d="M116.7 74.4v2.6M116.7 74.5h6.8M116.7 76.9h6.8M116.7 76.8h6.8M116.7 76.7h6.8M116.7 76.6h6.8M116.7 76.5h6.8M116.7 76.4h6.8M116.7 76.3h6.8M116.7 76.2h6.8M116.7 76.1h6.8M116.7 76h6.8"/>
<path d="M116.7 75.9h6.8M116.7 75.8h6.8M116.7 75.7h6.8M116.7 75.6h6.8M116.7 75.5h6.8M116.7 75.4h6.8M116.7 75.3h6.8M116.7 75.2h6.8M116.7 75h6.8M116.7 74.9h6.8M116.7 74.8h6.8M116.7 74.7h6.8"/>
<path d="M116.7 74.6h6.8M116.7 77h6.8M116.8 77h6.7M116.8 61.1h-3M116.8 64.3v1.5l.3 .6M116.8 77.1h6.7M116.9 77.2h6.6M116.9 61l-3 .1M117 77.3h6.5M117 61h-3.1M117.1 77.3h6.4M117.1 66.4l1.7 1.7 .5 .2"/>
<path d="M117.1 77.4h6.3M117.2 77.4h6.2M117.2 60.9l-3.2 .1M117.2 77.5h6.1M117.3 60.9l-.7 .3-.5 .5M117.3 77.5h6M117.3 77.6h5.9M117.4 77.6h5.8M119.5 60.9l.6 .3 .5 .5M119.5 60.9h4M119.7 61h3.7M119.8 61h3.5"/>
<path d="M119.9 64.3v.6M119.9 64.9h3.6M119.9 64.8h3.5M119.9 64.7l3.5 .1M119.9 64.7h3.5M119.9 64.6l3.5 .1M119.9 64.6h3.4M119.9 64.5l3.4 .1M119.9 64.5h3.4M119.9 64.4l3.4 .1M119.9 64.4h3.4M119.9 64.3h3.3"/>
<path d="M119.9 65h3.7M120 64.3h3.1M120 61.1h3.1M120 65h3.7M120 61.2h3M120 65.1h3.7M120.1 65.1l3.7 .1M120.1 64.2h2.9M120.1 65.2h3.7M120.2 64.2h2.7M120.2 61.2h2.7M120.2 65.2l3.7 .1"/>
<path d="M120.2 61.3h2.7M120.2 64.1h2.7M120.3 64.1h2.5M120.3 61.3h2.5M120.3 61.4h2.5M120.3 64h2.4M120.4 63.9h2.3M120.4 61.4h2.3M120.4 61.5h2.3M120.4 63.9h2.2M120.5 63.8h2.1M120.5 61.5h2.1"/>
<path d="M120.5 61.6h2.1M120.5 63.8h2M120.6 63.7h1.9M120.6 61.6h1.9M120.6 61.7l.3 .6M120.6 61.7h1.8M120.6 63.6l1.8 .1M120.6 63.6h1.8M120.7 61.8h1.7M120.7 63.5l1.7 .1M120.7 63.5h1.7M120.7 61.9h1.7"/>
<path d="M120.7 63.4l1.7 .1M120.8 63.4h1.5M120.8 62h1.5M120.8 63.3h1.5M120.8 62.1h1.5M120.8 63.2h1.5M120.8 62.2h1.5M120.9 63.1h1.3M120.9 62.3h1.3M120.9 63l-.3 .7-.7 .6M120.9 62.3v.7M120.9 63h1.3"/>
<path d="M120.9 62.9h1.3M120.9 62.8h1.3M120.9 62.7h1.3M120.9 62.6h1.3M120.9 62.5h1.3M120.9 62.4h1.3M122.2 62.3v.7M122.2 63l.2 .7 .6 .5M122.2 62.2h-1.3M122.3 62h-1.5M122.4 61.7l-.2 .6M123 64.2l.2 .1"/>
<path d="M123.2 64.3l.2 .5M123.4 64.8l.5 .5h-3.7l-.3-.4M123.6 60.9l-.6 .3-.6 .5M123.7 73.9l-.2 .5v2.9M125.7 72.3l-.6 .2-1.4 1.4M125.8 60.9l.7 .3 .5 .5M125.9 60.9h4M126 61h3.7M126.2 61h3.4M126.3 61.1h3.2M126.4 61.2h3M126.5 61.2h2.8"/>
<path d="M126.6 61.3h2.6M126.7 61.4h2.4M126.8 61.5h2.2M126.8 61.5h2.1M126.9 61.6h2M126.9 61.6h1.9M127 61.7l.3 .6M127 61.7h1.8M127 61.8h1.8M127 61.8h1.7M127.1 61.9h1.6M127.1 62h1.6"/>
<path d="M127.1 63.3h1.6M127.1 62.1h1.5M127.1 62.1h1.6M127.2 63.2h1.4M127.2 62.2h1.4M127.2 63.1h1.4M127.2 63.1h1.3M127.2 62.3h1.3M127.3 63l-.2 .4h1.6l-.2-.4M127.3 62.3v.7M127.3 63h1.2M127.3 62.9h1.2"/>
<path d="M127.3 62.8h1.2M127.3 62.7h1.2M127.3 62.6h1.2M127.3 62.5h1.2M127.3 62.4h1.2M127.3 62.3h1.2M128.5 62.3v.7M128.6 62.2h-1.4M128.7 62h-1.6M128.8 61.7l-.3 .6M129.8 72.3l.5 .2M129.9 72.3l5.5 .1"/>
<path d="M129.9 60.9l-.6 .3-.5 .5M130 72.4h5.5M130.2 72.4l5.3 .1M130.3 72.5h5.3M130.3 72.5l1.3 1.2M130.4 72.5l5.2 .1M130.4 72.6h5.3M130.5 72.6l5.2 .1M130.5 72.7h5.3M130.6 72.7l5.2 .1M130.6 72.8h5.3M130.7 72.9h5.3"/>
<path d="M130.8 73h5.3M130.9 73h5.2M130.9 73.1h5.3M131 73.1l5.2 .1M131 73.2h5.3M131.1 73.2l5.4 .1M131.1 73.3h5.5M131.2 73.3l5.5 .1M131.2 73.4h42.7M131.3 73.4l42.7 .1M131.3 73.5h42.7M131.4 73.6h42.6"/>
<path d="M131.5 73.7h42.5M131.6 73.7l.2 .6M131.6 73.7h42.4M131.6 73.8h42.4M131.6 73.9h42.4M131.7 74h42.3M131.7 74.1h42.3M131.7 74.2h42.3M131.8 74.3v.8h17.4v-.1M131.8 75.1h17.4M131.8 74.9h17.6M131.8 74.6h17.9"/>
<path d="M132.2 60.9l.6 .3M132.2 60.9l2.6 .1M132.4 61h2.4M132.5 61l2.4 .1M132.7 61.1h2.2M132.7 61.2h2.3M133.6 61.2l.6 .2 5.1 5.2h39.5M133.7 61.2h1.3M133.8 61.3h1.3M134 61.3h1.1M134 61.4h1.2M134.2 61.4h1.1"/>
<path d="M134.2 61.5h1.1M134.3 61.5l1.1 .1M134.3 61.6h1.1M134.4 61.6l1.1 .1M134.4 61.7h1.1M134.5 61.7l1.1 .1M134.5 61.8h1.1M134.6 61.8l1.1 .1M134.6 61.9h1.1M134.7 62h1.1M134.8 62.1h1.1M134.9 62.1h1.1"/>
<path d="M134.9 62.2h1.1M135 62.2l1.1 .1M135 62.3h1.1M135.1 62.3l1.1 .1M135.1 62.4h1.1M135.2 62.4l1.1 .1M135.2 62.5h1.1M135.3 62.5l1.1 .1M135.3 62.6h1.1M135.4 62.6l1.1 .1M135.4 62.7h1.1M135.5 62.7l1.1 .1"/>
<path d="M135.6 62.8h1M135.6 62.8l1.1 .1M135.7 62.9h1M135.7 62.9l1.1 .1M135.8 63h1M135.8 63.1h1.1M135.9 63.1h1M135.9 63.2h1.1M136 63.2h1.1M136 63.3h1.1M136.1 63.3l1.1 .1M136.1 63.4h1.1"/>
<path d="M136.2 63.4l1.1 .1M136.2 63.5h1.1M136.3 63.5l1.1 .1M136.3 63.6h1.1M136.4 63.6l1.1 .1M136.4 63.7h1.1M136.5 63.8h1.1M136.6 63.9h1.1M136.7 63.9h1.1M136.7 64h1.1M136.8 64l1.1 .1M136.8 64.1h1.1"/>
<path d="M136.9 64.1l1.1 .1M136.9 64.2h1.1M137 64.2l1.1 .1M137 64.3h1.1M137.1 64.3l1.1 .1M137.1 64.4h1.1M137.2 64.4l1.1 .1M137.2 64.5h1.1M137.3 64.5l1.1 .1M137.4 64.6h1M137.4 64.6l1.1 .1M137.5 64.7h1"/>
<path d="M137.5 64.7l1.1 .1M137.6 64.8h1M137.6 64.9h1.1M137.7 64.9h1M137.7 65h1.1M137.8 65h1.1M137.8 65.1h1.1M137.9 65.1l1.1 .1M137.9 65.2h1.1M138 65.2l1.1 .1M138 65.3h1.1M138.1 65.3l1.1 .1"/>
<path d="M138.1 65.4h1.1M138.2 65.4l1.1 .1M138.2 65.5h1.2M138.3 65.6h1.3M138.3 65.6h1.4M138.4 65.7h1.4M138.5 65.7h39.5M138.5 65.8h39.5M138.6 65.8h39.5M138.6 65.9h39.5M138.7 65.9l39.5 .1M138.7 66h39.5"/>
<path d="M138.8 66l39.5 .1M138.8 66.1h39.5M138.9 66.1l39.5 .1M138.9 66.2h39.5M139 66.2l39.5 .1M139 66.3h39.5M139.1 66.3l39.5 .1M139.1 66.4h39.5M139.2 66.4l39.5 .1M139.3 66.5h39.5M139.3 65.5l-6.1-6.1h-17.6l-9.7 9.7M139.3 65.5l.6 .2"/>
<path d="M149.2 75l-17.4 .1M149.3 75h-17.5M149.3 74.9l-17.5 .1M149.4 74.8l-17.6 .1M149.5 74.8h-17.7M149.5 74.7l-17.7 .1M149.6 74.7h-17.8M149.6 74.6h-17.8M149.8 74.5h-18M149.9 74.5h-18.1M150 74.4h-18.2M150.1 74.4h-18.3"/>
<path d="M150.3 74.3h-18.5M150.4 74.3l-.7 .2-.5 .5M152.4 74.3l.6 .2 .5 .5M152.5 74.3h21.5M152.6 74.4h21.4M152.8 74.4h21.2M152.9 74.5h21.1M153 74.5h21M153.1 74.6h20.9M153.2 74.7h20.8M153.3 74.8h20.7M153.4 74.9h20.6"/>
<path d="M153.5 75h20.5M153.5 77h20.5M153.5 75l.3 .7M153.6 75.1h20.4M153.6 76.9h20.4M153.6 76.8h20.4M153.6 75.2h20.4M153.6 76.7h20.4M153.6 75.3h20.4M153.7 76.6h20.3M153.7 75.4h20.3M153.7 76.5h20.3"/>
<path d="M153.7 75.5h20.3M153.8 76.4h20.2M153.8 75.6h20.2M153.8 75.7v.7l-.3 .6M153.8 76.3h20.2M153.8 76.2h20.2M153.8 76.1h20.2M153.8 76h20.2M153.8 75.9h20.2M153.8 75.8h20.2M153.8 75.7h20.2M165 77l.6 .3 .9 .9"/>
<path d="M165.2 77.1h8.8M165.3 77.2h8.7M165.4 77.2h8.6M165.5 77.3h8.5M165.6 77.3h8.4M165.7 77.4h8.3M165.8 77.5h8.2M165.9 77.6h8.1M166 77.7h8M166.1 77.7h7.9M166.1 77.8h7.9M166.2 77.9h7.8"/>
<path d="M166.3 78h7.7M166.4 78.1h7.6M166.5 78.2h7.5M166.5 78.2l.5 .5M166.6 78.3h7.4M166.7 78.4h7.3M166.8 78.5h7.2M166.9 78.6h7.1M167 78.7l.2 .5M167 78.7h7M167 78.8h7M167.1 78.9h6.9"/>
<path d="M167.1 79h6.9M167.1 79.1h6.9M167.2 79.1h6.8M167.2 79.2h6.8M167.2 79.2v11.4M167.2 80h6.8M167.2 79.9h6.8M167.2 79.8h6.8M167.2 79.7h6.8M167.2 79.6h6.8M167.2 79.5h6.8M167.2 79.4h6.8"/>
<path d="M167.2 79.3h6.8M173.9 73.4l.1 .1M174 73.5v18.7M174 74.3h-42.2M176.8 66.6l.5 .2 2.9 2.9M176.9 66.6h2M177 66.7h1.9M177.1 66.7h1.9M177.2 66.8h1.8M177.4 66.8l1.7 .1M177.4 66.9h1.7M177.4 66.9l1.8 .1"/>
<path d="M177.5 67h1.7M177.6 67l1.7 .1M177.6 67.1h1.7M177.7 67.1l1.7 .1M177.7 67.2h1.8M177.8 67.2l1.7 .1M177.8 67.3h1.8M177.9 67.4h1.7M177.9 65.7l3.8 3.7M177.9 67.4h1.8M178 67.5h1.7M178.1 67.5h1.7"/>
<path d="M178.1 67.6h1.7M178.1 67.6h1.8M178.2 67.7h1.7M178.3 67.7l1.7 .1M178.3 67.8h1.7M178.4 67.8l1.7 .1M178.4 67.9h1.7M178.5 67.9l1.7 .1M178.5 68h1.8M178.6 68.1h1.7M178.6 68.1h1.8M178.7 68.2h1.7"/>
<path d="M178.7 68.2h1.8M178.8 68.3h1.7M178.8 68.3h1.8M178.9 68.4h1.7M178.9 68.4l1.8 .1M179 68.5h1.7M179 68.5l1.8 .1M179.1 68.6h1.7M179.2 68.6l1.7 .1M179.2 68.7h1.7M179.3 68.7l1.7 .1M179.3 68.8h1.7"/>
<path d="M179.3 68.8l1.8 .1M179.4 68.9h1.7M179.5 68.9l1.7 .1M179.5 69h1.8M179.6 69l1.7 .1M179.6 69.1h1.8M179.7 69.2h1.7M179.7 69.2h1.8M179.8 69.3h1.7M179.9 69.3h1.7M179.9 69.4h1.7M180 69.4h1.7"/>
<path d="M180 69.5h1.7M180.1 69.6h1.6M180.2 69.7l.4 .4 .2 .5M180.2 69.6h1.5M180.2 69.7h1.5M180.3 69.7h1.4M180.3 69.8h1.4M180.4 69.8h1.3M180.4 69.9h1.3M180.5 70h1.2M180.6 70.1h1.1M180.6 70.2h1.1"/>
<path d="M180.7 70.2h1M180.7 70.3h1M180.7 70.4h1M180.8 70.5h.9M180.8 70.6v37.8M180.8 73.4h.9M180.8 77h.9M180.8 74.3h.9M180.8 75.1h.9M180.8 72.3h.9M180.8 77.7h.9M180.8 74.5h.9"/>
<path d="M180.8 80h.9M180.8 79.9h.9M180.8 79.8h.9M180.8 79.7h.9M180.8 79.6h.9M180.8 79.5h.9M180.8 79.4h.9M180.8 79.3h.9M180.8 79.2h.9M180.8 79.1h.9M180.8 79h.9M180.8 78.9h.9"/>
<path d="M180.8 78.8h.9M180.8 78.7h.9M180.8 78.6h.9M180.8 78.5h.9M180.8 78.4h.9M180.8 78.3h.9M180.8 78.2h.9M180.8 78.1h.9M180.8 78h.9M180.8 77.9h.9M180.8 77.8h.9M180.8 77.6h.9"/>
<path d="M180.8 77.5h.9M180.8 77.4h.9M180.8 77.3h.9M180.8 77.2h.9M180.8 77.1h.9M180.8 76.9h.9M180.8 76.8h.9M180.8 76.7h.9M180.8 76.6h.9M180.8 76.5h.9M180.8 76.4h.9M180.8 76.3h.9"/>
<path d="M180.8 76.2h.9M180.8 76.1h.9M180.8 76h.9M180.8 75.9h.9M180.8 75.8h.9M180.8 75.7h.9M180.8 75.6h.9M180.8 75.5h.9M180.8 75.4h.9M180.8 75.3h.9M180.8 75.2h.9M180.8 75h.9"/>
<path d="M180.8 74.9h.9M180.8 74.8h.9M180.8 74.7h.9M180.8 74.6h.9M180.8 74.4h.9M180.8 74.2h.9M180.8 74.1h.9M180.8 74h.9M180.8 73.9h.9M180.8 73.8h.9M180.8 73.7h.9M180.8 73.6h.9"/>
<path d="M180.8 73.5h.9M180.8 73.3h.9M180.8 73.2h.9M180.8 73.1h.9M180.8 73h.9M180.8 72.9h.9M180.8 72.8h.9M180.8 72.7h.9M180.8 72.6h.9M180.8 72.5h.9M180.8 72.4h.9M180.8 72.2h.9"/>
<path d="M180.8 72.1h.9M180.8 72h.9M180.8 71.9h.9M180.8 71.8h.9M180.8 71.7h.9M180.8 71.6h.9M180.8 71.5h.9M180.8 71.4h.9M180.8 71.3h.9M180.8 71.2h.9M180.8 71.1h.9M180.8 71h.9"/>
<path d="M180.8 70.9h.9M180.8 70.8h.9M180.8 70.7h.9M180.8 70.6h.9M181.1 60h21.9M181.1 60.1h21.9M181.2 60.1h21.8M181.2 60.2h21.8M181.3 60.2h21.7M181.4 60.3h21.6M181.4 60.4h21.6M181.5 60.4l6 6"/>
<path d="M181.5 60.5h21.5M181.6 60.6h21.4M181.7 69.4v61.1M181.7 60.6h21.3M181.7 60.7h21.3M181.8 60.7h21.2M181.8 60.8h21.2M181.9 60.8h21.1M181.9 60.9h21.1M182 60.9h21M182.1 61h20.9M182.1 61.1h20.9"/>
<path d="M182.2 61.2h20.8M182.3 61.3h20.7M182.4 61.3h20.6M182.4 61.4h20.6M182.5 61.4h20.5M182.5 61.5h20.5M182.6 61.5h20.4M182.6 61.6h20.4M182.7 61.6h20.3M182.7 61.7h20.3M182.8 61.7h20.2M182.8 61.8h20.2"/>
<path d="M182.9 61.8h20.1M182.9 61.9h20.1M183 62h20M183.1 62.1h19.9M183.2 62.2h19.8M183.3 62.2h19.7M183.3 62.3h19.7M183.4 62.4h19.6M183.5 62.4h19.5M183.5 62.5h19.5M183.6 62.5h19.4M183.6 62.6h19.4"/>
<path d="M183.7 62.6h19.3M183.7 62.7h19.3M183.8 62.7h19.2M183.8 62.8h19.2M183.9 62.8h19.1M184 62.9h19M184 63h19M184.1 63.1h18.9M184.2 63.2h18.8M184.3 63.2h18.7M184.3 63.3h18.7M184.4 63.3h18.6"/>
<path d="M184.4 63.4h18.6M184.5 63.4h18.5M184.5 63.5h18.5M184.6 63.5h18.4M184.6 63.6h18.4M184.7 63.6h18.3M184.7 63.7h18.3M184.8 63.8h18.2M184.9 63.9h18.1M185 64h18M185.1 64.1h17.9M185.2 64.1h17.8"/>
<path d="M185.2 64.2h17.8M185.3 64.2h17.7M185.3 64.3h17.7M185.4 64.3h17.6M185.4 64.4h17.6M185.5 64.4h17.5M185.5 64.5h17.5M185.6 64.5h17.4M185.6 64.6h17.4M185.7 64.6h17.3M185.7 64.7h17.3M185.8 64.7h17.2"/>
<path d="M185.9 64.8h17.1M185.9 64.9h17.1M186 65h17M186.1 65h16.9M186.1 65.1h16.9M186.2 65.1h16.8M186.2 65.2h16.8M186.3 65.2h16.7M186.3 65.3h16.7M186.4 65.3h16.6M186.4 65.4h16.6M186.5 65.4h16.5"/>
<path d="M186.5 65.5h16.5M186.6 65.6h16.4M186.7 65.7h16.3M186.8 65.7h16.2M186.8 65.8h16.2M186.9 65.9h16.1M187 66h16M187.1 66h15.9M187.1 66.1h15.9M187.2 66.1h15.8M187.2 66.2h15.8M187.3 66.2h15.7"/>
<path d="M187.3 66.3h15.7M187.4 66.3h15.6M187.5 66.4h15.5M187.5 66.4l.2 .7M187.5 66.5h15.5M187.6 66.6h15.4M187.6 66.7h15.4M187.6 66.8h15.4M187.7 66.9h15.3M187.7 67h15.3M187.7 67.1v30M187.7 69.8h15.3"/>
<path d="M187.7 68.3h15.3M187.7 73.4h15.3M187.7 77h15.3M187.7 74.3h15.3M187.7 75.1h15.3M187.7 72.3h15.3M187.7 77.7h15.3M187.7 74.5h15.3M187.7 80h15.3M187.7 79.9h15.3M187.7 79.8h15.3M187.7 79.7h15.3"/>
<path d="M187.7 79.6h15.3M187.7 79.5h15.3M187.7 79.4h15.3M187.7 79.3h15.3M187.7 79.2h15.3M187.7 79.1h15.3M187.7 79h15.3M187.7 78.9h15.3M187.7 78.8h15.3M187.7 78.7h15.3M187.7 78.6h15.3M187.7 78.5h15.3"/>
<path d="M187.7 78.4h15.3M187.7 78.3h15.3M187.7 78.2h15.3M187.7 78.1h15.3M187.7 78h15.3M187.7 77.9h15.3M187.7 77.8h15.3M187.7 77.6h15.3M187.7 77.5h15.3M187.7 77.4h15.3M187.7 77.3h15.3M187.7 77.2h15.3"/>
<path d="M187.7 77.1h15.3M187.7 76.9h15.3M187.7 76.8h15.3M187.7 76.7h15.3M187.7 76.6h15.3M187.7 76.5h15.3M187.7 76.4h15.3M187.7 76.3h15.3M187.7 76.2h15.3M187.7 76.1h15.3M187.7 76h15.3M187.7 75.9h15.3"/>
<path d="M187.7 75.8h15.3M187.7 75.7h15.3M187.7 75.6h15.3M187.7 75.5h15.3M187.7 75.4h15.3M187.7 75.3h15.3M187.7 75.2h15.3M187.7 75h15.3M187.7 74.9h15.3M187.7 74.8h15.3M187.7 74.7h15.3M187.7 74.6h15.3"/>
<path d="M187.7 74.4h15.3M187.7 74.2h15.3M187.7 74.1h15.3M187.7 74h15.3M187.7 73.9h15.3M187.7 73.8h15.3M187.7 73.7h15.3M187.7 73.6h15.3M187.7 73.5h15.3M187.7 73.3h15.3M187.7 73.2h15.3M187.7 73.1h15.3"/>
<path d="M187.7 73h15.3M187.7 72.9h15.3M187.7 72.8h15.3M187.7 72.7h15.3M187.7 72.6h15.3M187.7 72.5h15.3M187.7 72.4h15.3M187.7 72.2h15.3M187.7 72.1h15.3M187.7 72h15.3M187.7 71.9h15.3M187.7 71.8h15.3"/>
<path d="M187.7 71.7h15.3M187.7 71.6h15.3M187.7 71.5h15.3M187.7 71.4h15.3M187.7 71.3h15.3M187.7 71.2h15.3M187.7 71.1h15.3M187.7 71h15.3M187.7 70.9h15.3M187.7 70.8h15.3M187.7 70.7h15.3M187.7 70.6h15.3"/>
<path d="M187.7 70.5h15.3M187.7 70.4h15.3M187.7 70.3h15.3M187.7 70.2h15.3M187.7 70.1h15.3M187.7 70h15.3M187.7 69.9h15.3M187.7 69.7h15.3M187.7 69.6h15.3M187.7 69.5h15.3M187.7 69.4h15.3M187.7 69.3h15.3"/>
<path d="M187.7 69.2h15.3M187.7 69.1h15.3M187.7 69h15.3M187.7 68.9h15.3M187.7 68.8h15.3M187.7 68.7h15.3M187.7 68.6h15.3M187.7 68.5h15.3M187.7 68.4h15.3M187.7 68.2h15.3M187.7 68.1h15.3M187.7 68h15.3"/>
<path d="M187.7 67.9h15.3M187.7 67.8h15.3M187.7 67.7h15.3M187.7 67.6h15.3M187.7 67.5h15.3M187.7 67.4h15.3M187.7 67.3h15.3M187.7 67.2h15.3M187.7 67.1h15.3M97.8 99.7h2.2M97.8 99.6h2.2M97.8 99.9h2.2"/>
<path d="M97.8 99.8h2.2M97.8 87l.8 .1M97.8 86.9l.8 .1M97.8 84.4h.7M97.8 84.2h.6M97.8 84.1h.6M97.8 98h1.8M97.8 97.8l1.4 .1M97.8 98.1h3.3l-.9 .9-.2 .5M97.8 97.3l.9 .1M97.8 80.9h.6M97.8 85.5h.7"/>
<path d="M97.8 85.6h.6M97.8 89.2h.6M97.8 89.3l.7 .1M97.8 94.8h.9M97.8 92.3h.9M97.8 81.9h.8M97.8 91.7h.6M97.8 89.8h.9M97.8 99.5h2.2M97.8 99.4h2.3M97.8 99.3h2.3M97.8 99.2h2.4"/>
<path d="M97.8 99.1h2.4M97.8 99h2.5M97.8 98.6h2.8M97.8 98.3h3.2M97.8 98l1.9 .1M97.8 97.9l1.6 .1M97.8 97.9h1.5M97.8 97.8h1.3M97.8 97.7h1.3M97.8 97.7h1.2M97.8 97.6h1.2M97.8 97.6h1.1"/>
<path d="M97.8 97.5h1M97.8 97.4h.9M97.8 97.3h.8M97.8 97.2h.8M97.8 97.1l.8 .1M97.8 97.1h.8M97.8 97h.7M97.8 96.9h.7M97.8 96.8h.6M97.8 96.7h.6M97.8 96.6h.6M97.8 96.5h.6"/>
<path d="M97.8 96.4h.6M97.8 96.3h.6M97.8 96.2h.6M97.8 96.1h.6M97.8 96h.6M97.8 95.7h.7M97.8 95l1.1 .1M97.8 95h1M97.8 94.9l1 .1M97.8 94.9h.9M97.8 94.8h.8M97.8 94.7h.8"/>
<path d="M97.8 94.6h.8M97.8 94.5h.7M97.8 94.4h.7M97.8 94.3l.7 .1M97.8 94.3h.6M97.8 94.2l.6 .1M97.8 94.2h.6M97.8 94.1h.6M97.8 94h.6M97.8 93.9h.6M97.8 93.8h.6M97.8 93.7h.6"/>
<path d="M97.8 93.6h.6M97.8 93.5h.6M97.8 92.5h1.1M97.8 92.4l1 .1M97.8 92.4h1M97.8 92.3l.9 .1M97.8 92.2h.8M97.8 92.1h.8M97.8 92h.8M97.8 91.9l.7 .1M97.8 91.9h.7M97.8 91.8l.7 .1"/>
<path d="M97.8 91.8h.7M97.8 91.7l.6 .1M97.8 91.6l.6 .1M97.8 91.6h.6M97.8 91.5h.6M97.8 91.4h.6M97.8 91.3h.6M97.8 91.2h.6M97.8 91.1h.6M97.8 91h.6M97.8 90.9h.6M97.8 90.6h.7"/>
<path d="M97.8 90.3h.8M97.8 89.9l1.1 .1M97.8 89.9h1M97.8 89.8l1 .1M97.8 89.7h.9M97.8 89.7h.8M97.8 89.6h.8M97.8 89.5h.8M97.8 89.4h.7M97.8 89.3h.7M97.8 89.2l.7 .1M97.8 89.1l.6 .1"/>
<path d="M97.8 89.1h.6M97.8 89l.6 .1M97.8 89h.6M97.8 88.9h.6M97.8 88.8h.6M97.8 88.7h.6M97.8 88.6h.6M97.8 88.5h.6M97.8 88.4h.6M97.8 88h.7M97.8 87.9h.8M97.8 87.7h.8"/>
<path d="M97.8 87.4h1.1M97.8 87.3l1 .1M97.8 87.3h1M97.8 87.2l.9 .1M97.8 87.2h.9M97.8 87.1h.8M97.8 87h.8M97.8 86.9h.7M97.8 86.8h.7M97.8 86.7h.7M97.8 86.7h.6M97.8 86.6h.6"/>
<path d="M97.8 86.5h.6M97.8 86.4h.6M97.8 86.3h.6M97.8 86.2h.6M97.8 86.1h.6M97.8 86h.6M97.8 85.9h.6M97.8 85.7h.6M97.8 85.4h.7M97.8 85.4h.8M97.8 85.3h.8M97.8 85.2h.8"/>
<path d="M97.8 84.9h1.1M97.8 84.8l1.1 .1M97.8 84.8h1M97.8 84.7l1 .1M97.8 84.7h.9M97.8 84.6l.9 .1M97.8 84.6h.8M97.8 84.5l.8 .1M97.8 84.5h.8M97.8 84.4l.8 .1M97.8 84.3h.7M97.8 84.2h.7"/>
<path d="M97.8 84h.6M97.8 83.9h.6M97.8 83.8h.6M97.8 83.7h.6M97.8 83.6h.6M97.8 83.5h.6M97.8 83.4h.6M97.8 83.3h.6M97.8 83.2h.6M97.8 83.1h.6M97.8 83h.7M97.8 82.9h.7"/>
<path d="M97.8 82.8h.8M97.8 82.7h.8M97.8 82.4h1.1M97.8 82.3h1.1M97.8 82.3h1M97.8 82.2h1M97.8 82.1l.9 .1M97.8 82.1h.9M97.8 82l.8 .1M97.8 82h.8M97.8 81.8h.7M97.8 81.7h.7"/>
<path d="M97.8 81.6h.6M97.8 81.5h.6M97.8 81.4l.6 .1M97.8 81.4h.6M97.8 81.3h.6M97.8 81.2h.6M97.8 81.1h.6M97.8 81h.6M97.8 80.8h.6M97.8 80.7h.6M97.8 80.6h.6M97.8 80.5h.7"/>
<path d="M97.8 80.4h.7M97.8 80.3h.7M97.8 80.3h.8M97.8 80.2h.8M97.8 80.1h.8M98.4 80.8v.6M98.4 83.3v.7l.5 .9M98.4 85.8v.7M98.4 88.4v.7M98.4 90.9v.7M98.4 93.5v.6M98.4 96v.7"/>
<path d="M98.4 81.4l.5 1M98.4 86.5l.5 .9M98.4 89.1l.5 .9M98.4 91.6l.5 .9M98.4 94.1l.5 1M98.4 96.7l.2 .6 .5 .5 .7 .3M98.4 96h-.6M98.4 93.4l-.6 .1M98.4 90.9h-.6M98.4 88.3l-.6 .1M98.4 85.8h-.6M98.4 83.2l-.6 .1"/>
<path d="M98.4 80.7l-.6 .1M98.4 95.9h-.6M98.4 93.4h-.6M98.4 90.8l-.6 .1M98.4 88.3h-.6M98.4 93.3h-.6M98.4 90.8h-.6M98.4 88.2l-.6 .1M98.4 85.7h-.6M98.4 83.1l-.6 .1M98.4 80.6h-.6M98.4 95.8h-.6"/>
<path d="M98.4 90.7l-.6 .1M98.4 88.2h-.6M98.5 95.8h-.7M98.5 93.2h-.7M98.5 90.7h-.7M98.5 88.1l-.7 .1M98.5 85.6h-.7M98.5 83l-.7 .1M98.5 80.5h-.7M98.5 90.6l-.7 .1M98.5 88.1h-.7M98.5 95.7h-.7"/>
<path d="M98.5 93.1h-.7M98.5 95.6h-.7M98.5 90.5l-.7 .1M98.5 88h-.7M98.6 95.5l-.8 .1M98.6 93h-.8M98.6 90.5h-.8M98.6 95.5h-.8M98.6 90.4h-.8M98.6 87.9h-.8M98.6 95.4l-.8 .1M98.6 92.9h-.8"/>
<path d="M98.6 87.8h-.8M98.6 95.4h-.8M98.6 90.3h-.8M98.6 85.3h-.8M98.6 82.7h-.8M98.6 80.2h-.8M98.6 80.1l-.2 .7M98.6 82.6l-.2 .7M98.6 85.2l-.2 .6M98.6 87.7l-.2 .7M98.6 90.3l-.2 .6M98.6 92.8l-.2 .7"/>
<path d="M98.6 95.3l-.2 .7M98.6 95.3l-.8 .1M98.6 92.8h-.8M98.7 80.1h-.9M98.7 85.2h-.9M98.7 82.6h-.9M98.7 95.3h-.9M98.7 92.8h-.9M98.7 90.2h-.9M98.7 87.7h-.9M98.7 85.1h-.9M98.7 80l-.9 .1"/>
<path d="M98.7 95.2l-.9 .1M98.7 92.7h-.9M98.7 90.1l-.9 .1M98.7 87.6h-.9M98.8 85l-1 .1M98.8 82.5h-1M98.8 95.2h-1M98.8 92.6l-1 .1M98.8 90.1h-1M98.8 87.5l-1 .1M98.8 85h-1M98.8 95.1l-1 .1"/>
<path d="M98.8 92.6h-1M98.8 90l-1 .1M98.8 87.5h-1M98.9 84.9l-1.1 .1M98.9 82.4h-1.1M98.9 95.1h-1.1M98.9 92.5l-1.1 .1M98.9 82.4l-.3 .2M98.9 84.9l-.3 .3M98.9 87.4l-.3 .3M98.9 90l-.3 .3M98.9 92.5l-.3 .3"/>
<path d="M98.9 95.1l-.3 .2M98.9 90h-1.1M98.9 87.4l-1.1 .1M100 99.5v7M100.1 99.4l-2.3 .1M100.2 99.1h-2.4M100.2 99h-2.4M100.3 98.9h-2.5M100.4 98.8l-2.6 .1M100.4 98.8h-2.6M100.5 98.7l-2.7 .1M100.5 98.7h-2.7"/>
<path d="M100.6 98.6h-2.8M100.7 98.5l-2.9 .1M100.8 98.5h-3M100.8 98.4h-3M100.9 98.4h-3.1M100.9 98.3h-3.1M101 98.2h-3.2M101.1 98.1l-3.3 .1M126.2 98h17.3M126.2 99.9h.1M126.2 97.9l.3 .1M126.2 97.9h.2"/>
<path d="M126.3 99.8l-.1 .1M126.4 99.8h-.2M126.6 99.7l-.4 .2M126.6 98l-.4-.1v2M128.6 99.7l.2 .1M128.7 99.8h.2M128.8 99.8h.1M128.9 97.9l-.3 .1M129.1 99.7l-2.9 .1M129.2 99.7h-3M129.3 99.6l-.5 .2M129.6 80.1h19.5"/>
<path d="M129.6 80.2l19.5-.1-.1 .3M129.6 80.2l.3 .6M129.7 80.3h19.3M129.8 80.5h19.2M129.8 81.6h3.6M129.8 80.6h19.2M129.9 80.7h19.1M129.9 81.4l-.2 .5h3.6M129.9 80.8v.6M129.9 81.3h3.9M129.9 80.9h19.1M129.9 80.8h19.1"/>
<path d="M131.6 99.6l.6 .3h.4l.6-.3M131.6 81.9l.6 .2 .5 .5M131.7 99.7h1.4M131.7 81.9h1.6M131.8 99.7h1.2M131.8 82h1.4M131.9 99.8h1M132 82h1.2M132 99.8h.8M132.1 82.1h1.1M132.2 82.1h1M132.2 82.2h1"/>
<path d="M132.3 82.3h.8M132.4 82.3h.7M132.4 82.4h.7M132.4 90l.3 .3M132.4 87.4l.3 .3M132.4 84.9l.3 .3M132.4 90h1M132.4 87.4h1M132.4 84.9h.9M132.5 89.9h.9M132.5 87.4h.9M132.5 84.9h.9"/>
<path d="M132.5 84.9h.8M132.5 82.4h.6M132.5 90h.9M132.5 87.5h.9M132.5 90.1h.9M132.5 85h.9M132.5 84.8h.8M132.5 82.5h.6M132.6 89.9h.8M132.6 87.3h.8M132.6 85h.8M132.6 84.8h.7"/>
<path d="M132.6 82.5h.5M132.6 89.8h.8M132.6 90.1h.8M132.6 87.6h.8M132.6 90.2h.8M132.6 87.7h.8M132.6 85.1h.8M132.6 84.7h.7M132.6 82.6h.5M132.7 89.7h.7M132.7 87.2h.7M132.7 84.7h.5"/>
<path d="M132.7 85.2h.7M132.7 82.6h.4M132.7 92.3h.1M132.7 82.6l.3 .7v.7l-.3 .6M132.7 85.2l.3 .6v.7M132.7 90.3l.3 .6M132.7 89.7l-.3 .3M132.7 87.7l.3 .7M132.7 87.2l-.3 .2M132.7 84.6l-.3 .3M132.7 90.3h.7M132.7 87.7h.7"/>
<path d="M132.7 87.8h.7M132.7 84.6h.5M132.7 82.7h.4M132.7 87.1h.7M132.7 90.4h.7M132.7 89.6h.7M132.7 85.3h.7M132.7 84.5h.5M132.8 90.4h.6M132.8 87.9h.6M132.8 85.3h.6M132.8 84.5h.4"/>
<path d="M132.8 82.8h.3M132.8 87h.6M132.8 90.5h.6M132.8 89.5h.6M132.8 85.4h.6M132.8 84.4h.4M132.8 84.4h.3M132.8 88h.6M132.8 82.9h.3M132.8 90.6h.6M132.8 89.4h.6M132.8 86.9h.6"/>
<path d="M132.8 85.5h.6M132.8 84.3h.3M132.8 89.3h.6M132.8 88.1h.6M132.8 86.8h.6M132.8 83h.3M132.9 91.8h.5M132.9 90.7h.5M132.9 89.3h.5M132.9 88.1h.5M132.9 86.8h.5M132.9 85.6h.5"/>
<path d="M132.9 84.2h.2M132.9 83h.2M132.9 89.2h.5M132.9 88.2h.5M132.9 86.7h.5M132.9 83.1h.2M132.9 91.7h.5M132.9 85.7h.5M132.9 84.1h.2M132.9 90.8h.5M132.9 88.3h.5M132.9 86.6h.5"/>
<path d="M132.9 83.2h.2M132.9 91.6h.5M132.9 89.1h.5M132.9 85.8h.5M132.9 84h.2M133 91.6l-.3 .7M133 88.4v.7M133 90.9v.7M133 89.1l-.3 .6M133 86.5l-.3 .7M133 91.6h.4M133 91.5h.4"/>
<path d="M133 91.4h.4M133 91.3h.4M133 91.2h.4M133 91.1h.4M133 91h.4M133 90.9h.4M133 89h.4M133 88.9h.4M133 88.8h.4M133 88.7h.4M133 88.6h.4M133 88.5h.4"/>
<path d="M133 88.4h.4M133 88.3h.4M133 86.5h.4M133 86.4h.4M133 86.3h.4M133 86.2h.4M133 86.1h.4M133 86h.4M133 85.9h.4M133 83.9h.1M133 83.8h.1M133 83.7h.1"/>
<path d="M133 83.6h.1M133 83.5h.1M133 83.4h.1M133 83.3h.1M133.1 92.2h-.4M133.1 82.3v2M133.1 84.3l.3 .6M133.2 92.1h-.5M133.2 92.1h-.4M133.3 92h-.5M133.3 81.8l-3.6 .1M133.3 91.9l-.5 .1"/>
<path d="M133.3 81.8h-3.5M133.3 81.7h-3.5M133.4 84.9v7M133.4 91.9l-.4 .4h-.3M133.4 91.9h-.6M133.4 81.7h-3.6M133.5 81.6h-3.7M133.5 81.5h-3.6M133.6 81.4l-3.7 .1M133.6 81.4h-3.7M133.7 81.3l-3.8 .1M133.8 81.2l-3.9 .1"/>
<path d="M133.9 81.2h-4M134 81.1l-4.1 .1M134.1 81.1h-4.2M134.3 81l-4.4 .1M134.3 81h-4.4M134.5 80.9l-.6 .3-.5 .5-.3 .6M134.9 94.7h.1M135.2 99.6l.7 .3h3.1l.6-.3M135.2 80.9l.7 .3 .5 .5M135.3 99.7h4.2M135.4 81h6.6M135.4 94.1h5.6"/>
<path d="M135.5 99.7h3.9M135.5 94h5.5M135.5 81h6.4M135.6 93.9h5.4M135.6 99.8h3.6M135.6 81.1h6.1M135.7 93.8h5.3M135.7 99.8h3.4M135.7 93.8h.1M135.8 81.1h5.8M135.8 93.7h5.2M135.9 81.2h5.6"/>
<path d="M135.9 93.6h5.1M135.9 81.2h5.5M136 93.6h5M136 81.3h5.4M136 93.5h5M136 81.3h5.3M136.1 93.5h4.9M136.1 81.4h5.2M136.1 93.4h4.9M136.1 81.4h5.1M136.2 93.3h4.8M136.2 93.2h4.8"/>
<path d="M136.2 81.5h5M136.2 93.1h4.8M136.2 81.6h4.9M136.3 93.1h4.7M136.3 93h4.7M136.3 81.6h4.8M136.3 92.9h4.7M136.4 92.9h4.6M136.4 81.7h4.6M136.4 84.9v.6l4.6-.1M136.4 92.8l-.2 .6-1.5 1.4h5.6M136.4 81.7l.3 .6"/>
<path d="M136.4 92.3h4.6M136.4 91.7h4.6M136.4 89.8h4.6M136.4 92.8h4.6M136.4 92.7h4.6M136.4 92.6h4.6M136.4 92.5h4.6M136.4 92.4h4.6M136.4 92.2h4.6M136.4 92.1h4.6M136.4 92h4.6M136.4 91.9h4.6"/>
<path d="M136.4 91.8h4.6M136.4 91.6h4.6M136.4 91.5h4.6M136.4 91.4h4.6M136.4 91.3h4.6M136.4 91.2h4.6M136.4 91.1h4.6M136.4 91h4.6M136.4 90.9h4.6M136.4 90.8h4.6M136.4 90.7h4.6M136.4 90.6h4.6"/>
<path d="M136.4 90.5h4.6M136.4 90.4h4.6M136.4 90.3h4.6M136.4 90.2h4.6M136.4 90.1h4.6M136.4 90h4.6M136.4 89.9h4.6M136.4 89.7h4.6M136.4 89.6h4.6M136.4 89.5h4.6M136.4 89.4h4.5M136.4 85.4h4.6"/>
<path d="M136.4 85.3h4.6M136.4 85.2h4.6M136.4 85.1h4.6M136.4 85h4.6M136.4 84.9h4.6M136.4 84.8h4.5M136.4 81.8h4.5M136.5 81.9h4.4M136.5 84.7h4.4M136.5 84.6h4.4M136.5 82h4.4M136.5 84.6h4.3"/>
<path d="M136.5 82h4.3M136.5 84.5h4.3M136.5 82.1h4.3M136.6 84.5h4.2M136.6 82.1h4.2M136.6 84.4h4.2M136.6 82.2h4.2M136.6 82.3h4.2M136.6 84.3h4.1M136.6 82.3h4.1M136.7 84.2h4M136.7 84.1h4"/>
<path d="M136.7 85.5l.3 .2M136.7 84.3l-.3 .6M136.7 82.3v2M136.7 84.3h4M136.7 84h4M136.7 83.9h4M136.7 83.8h4M136.7 83.7h4M136.7 83.6h4M136.7 83.5h4M136.7 83.4h4M136.7 83.3h4"/>
<path d="M136.7 83.2h4M136.7 83.1h4M136.7 83h4M136.7 82.9h4M136.7 82.8h4M136.7 82.7h4M136.7 82.6h4M136.7 82.5h4M136.7 82.4h4M136.7 89.3h3.9M136.8 85.6h3.8M136.8 89.3h3.7"/>
<path d="M136.9 85.6h3.6M137.1 85.7l.7 .2 .5 .5M137.2 85.7h3M137.2 89.2h2.9M137.3 85.7h2.8M137.4 89.1h2.6M137.4 85.8h2.6M137.5 89.1h2.4M137.5 85.9h2.3M137.6 89h2.1M137.7 85.9h2M137.7 89h1.9"/>
<path d="M137.8 86h1.8M137.8 88.9h1.7M137.9 88.9h1.6M137.9 86h1.6M137.9 86.1h1.6M137.9 88.8h1.5M138 86.1h1.4M138 88.7h1.4M138 86.2h1.4M138 88.7h1.3M138.1 86.2h1.2M138.1 88.6h1.2"/>
<path d="M138.1 86.3h1.2M138.2 88.6h1M138.2 88.5h1M138.2 86.3h1M138.2 86.4h.9M138.2 88.5h.9M138.3 86.4l.3 .7M138.3 88.4h.8M138.3 86.4h.8M138.3 86.5h.8M138.3 88.3h.7M138.3 86.6h.7"/>
<path d="M138.4 88.2h.6M138.4 86.7h.6M138.4 88.1h.6M138.4 86.8h.6M138.4 88.1h.5M138.4 86.8h.5M138.5 88h.4M138.5 86.9h.4M138.5 87.9h.4M138.5 87h.4M138.5 87.8h.3M138.6 87.8l-.3 .7-.5 .4-.7 .3"/>
<path d="M138.6 87.1v.7M138.6 87.8h.2M138.6 87.7h.2M138.6 87.6h.2M138.6 87.5h.2M138.6 87.4h.2M138.6 87.3h.2M138.6 87.2h.2M138.6 87.1h.2M138.8 87.1v.7M138.8 87.8l.3 .7 .5 .4M139.1 86.4l-.3 .7"/>
<path d="M139.6 88.9l.6 .3M140.2 85.7l-.6 .2-.5 .5M140.3 94.8h-5.6M140.4 89.2l.3 .2M140.4 89.2h-3.4l-.3 .2M140.4 94.7h-5.6M140.4 94.7h-5.5M140.5 94.6h-5.6M140.5 94.6h-5.5M140.6 94.5h-5.6M140.7 94.4l-5.6 .1M140.7 82.3v2"/>
<path d="M140.7 84.3l.3 .6M140.7 85.5l-.3 .2M140.7 94.4h-5.6M140.8 94.3l-5.6 .1M140.8 94.3h-5.6M140.9 94.2l-5.6 .1M140.9 94.2h-5.6M140.9 85.5h-4.5M141 94.1h-5.6M141 85.4h-4.6M141 81.7l-.3 .6M141 84.9v.5"/>
<path d="M141 89.5v4.6M141 89.5l-4.6-.1v3.4M141 94.1l-.7 .7M141.6 99.6l.2 .1M141.7 99.7h.1M141.8 99.6l-15.6 .1M141.9 99.6h-15.7M141.9 99.5l-15.7 .1M142 99.5h-15.8M142 99.4l-15.8 .1M142 97.3h4.5M142.1 99.4h-15.9"/>
<path d="M142.1 97.3h4.4M142.1 80.9l-.6 .3-.5 .5M142.1 99.3l-15.9 .1M142.2 97.2h4.2M142.2 99.3h-16M142.2 99.2l-16 .1M142.3 97.1h4.1M142.3 99.2h-16.1M142.3 99.1h-16.1M142.4 97h3.9M142.4 99.1h-16.2M142.5 99h-16.3"/>
<path d="M142.5 96.9h3.8M142.6 98.9h-16.4M142.6 96.8h3.6M142.6 98.8l-16.4 .1M142.7 98.8h-16.5M142.7 96.7h3.5M142.7 98.7l-16.5 .1M142.7 96.6h3.5M142.8 98.7h-16.6M142.8 96.6h3.4M142.8 98.6l-16.6 .1M142.8 96.5h3.4"/>
<path d="M142.9 80.9l.6 .3 .5 .5 .3 .6v2l-.3 .6M142.9 98.6h-16.7M142.9 96.5h3.3M142.9 98.5l-16.7 .1M142.9 96.4h3.3M143 98.5h-16.8M143 96.4h3.2M143 81h6M143 98.4h-16.8M143 96.3h3.2M143.1 98.4h-16.9M143.1 96.3h3.1"/>
<path d="M143.1 81h5.9M143.2 98.3h-17M143.2 96.2h3M143.3 98.2h-17.1M143.3 96.1h2.9M143.3 81.1h5.7M143.3 98.1l-17.1 .1M143.3 96l-1.5 1.6-.6 .3M143.4 98.1h-17.2M143.4 96h2.8M143.4 81.1l5.6 .1M143.4 98l-17.2 .1"/>
<path d="M143.4 95.9h2.8M143.5 95.9h2.7M143.5 97.9l-14.8 .1M143.5 81.2h5.5M143.5 95.8h2.8M143.6 81.2l5.4 .1M143.6 97.9h-14.8M143.6 97.8l-14.7 .1M143.6 81.3h5.5M143.6 95.7h2.7M143.7 81.3l5.4 .1M143.7 97.8h-2.4"/>
<path d="M143.7 97.7h-2.3M143.7 81.4h5.4M143.7 95.6h2.6M143.8 81.4l5.3 .1M143.8 97.7h-2.3M143.8 95.5h2.6M143.8 97.6h-2.1M143.8 81.5h5.3M143.8 95.4h2.7M143.9 81.6h5.3M143.9 95.3h2.6M144 97.6h-2.2"/>
<path d="M144 81.7h5.2M144 86.9h5.3M144 95l-.2 .6-.5 .4M144 84.9v10.1M144 85.5h5.3M144 85.6h5.3M144 89.2h2.3M144 89.3h2.3M144 94.8h2.6M144 92.3h2.6M144 91.7h2.2M144 89.8h2.6"/>
<path d="M144 95l2.8 .1M144 95h2.7M144 94.9l2.7 .1M144 94.9h2.6M144 94.8h2.5M144 94.7h2.5M144 94.7h2.4M144 94.6h2.4M144 94.5h2.4M144 94.4h2.3M144 94.3h2.3M144 94.2h2.2"/>
<path d="M144 94.1h2.2M144 94h2.2M144 93.9h2.2M144 93.8h2.2M144 93.7h2.2M144 93.6h2.2M144 93.5h2.2M144 93.4h2.2M144 93.3h2.3M144 93.2h2.3M144 93.1h2.3M144 93h2.4"/>
<path d="M144 92.9h2.5M144 92.5h2.8M144 92.4l2.7 .1M144 92.4h2.7M144 92.3l2.6 .1M144 92.2h2.5M144 92.2h2.4M144 92.1h2.4M144 92h2.4M144 91.9h2.3M144 91.8h2.3M144 91.7h2.3"/>
<path d="M144 91.6h2.2M144 91.5h2.2M144 91.4h2.2M144 91.3h2.2M144 91.2h2.2M144 91.1h2.2M144 91h2.2M144 90.9h2.2M144 90.8h2.2M144 90.7h2.3M144 90.6h2.3M144 89.9l2.7 .1"/>
<path d="M144 89.9h2.7M144 89.8l2.6 .1M144 89.7h2.5M144 89.6h2.4M144 89.5h2.4M144 89.4h2.3M144 89.1l2.2 .1M144 89.1h2.2M144 89h2.2M144 88.9h2.2M144 88.8h2.2M144 88.7h2.2"/>
<path d="M144 88.6h2.2M144 88.5h2.2M144 88.4h2.2M144 88.3h2.2M144 88.2h2.2M144 88.1h2.3M144 88h2.3M144 87h5.4M144 86.8h5.3M144 86.7h5.3M144 86.6h5.3M144 86.5h5.3"/>
<path d="M144 86.4h5.3M144 86.3h5.3M144 86.2h5.3M144 86.1h5.3M144 86h5.3M144 85.9h5.3M144 85.8h5.3M144 85.7h5.3M144 85.4h5.3M144 85.3h5.3M144 85.2h5.3M144 85.1h5.3"/>
<path d="M144 85h5.3M144 84.9h5.3M144 97.5h-2.2M144 81.8h5.3M144.1 84.8h5.2M144.1 81.8l5.2 .1M144.1 81.9h5.3M144.1 81.9l5.3 .1M144.1 84.6h5.3M144.1 82h5.4M144.1 82l5.4 .1M144.2 84.5h5.2"/>
<path d="M144.2 82.1h5.4M144.2 97.5h-2.3M144.2 82.1l5.4 .1M144.2 82.2h5.5M144.2 84.4h5.3M144.2 82.3h5.5M144.3 82.3h5.6M144.3 84.2h5.3M144.3 83.9h5.6M144.3 83.8h5.6M144.3 83.7h5.6M144.3 83.6h5.6"/>
<path d="M144.3 83.5h5.6M144.3 83.4h5.6M144.3 83.3h5.6M144.3 83.2h5.6M144.3 83.1h5.6M144.3 83h5.6M144.3 82.9h5.6M144.3 82.8h5.6M144.3 82.7h5.6M144.3 82.6h5.6M144.3 82.5h5.6M144.3 82.4h5.6"/>
<path d="M144.3 97.4h-2.4M144.4 97.4l-.6 .2-2 2.1M146.2 89l.6 1M146.2 88.4v.6M146.2 90.9v.7M146.2 93.5v.6M146.2 96v.7M146.2 91.6l.6 .9M146.2 94.1l.3 .6M146.2 96.7l.3 .6M146.2 93.3l-2.2 .1M146.3 90.7h-2.3"/>
<path d="M146.3 88.2h-2.3M146.3 95.8h-2.7M146.3 90.6h-2.3M146.3 88.1h-2.3M146.3 95.7h-2.6M146.4 90.5h-2.4M146.4 88h-2.4M146.4 95.5l-2.6 .1M146.4 93h-2.4M146.4 87.9h-2.4M146.4 90.4h-2.4M146.4 95.4l-2.6 .1"/>
<path d="M146.4 92.9h-2.4M146.4 87.8h-2.4M146.5 87.8l-.3 .6M146.5 90.3l-.3 .6M146.5 94.7l.3 .4M146.5 97.3l-4.5 .1M146.5 90.3h-2.5M146.5 87.8h-2.5M146.5 95.3l-2.6 .1M146.5 92.8h-2.5M146.5 87.7h-2.5M146.6 90.2h-2.6"/>
<path d="M146.6 87.7h-2.6M146.6 95.2l-2.7 .1M146.6 92.7h-2.6M146.6 90.1l-2.6 .1M146.6 87.6h-2.6M146.7 95.2h-2.8M146.7 92.6l-2.7 .1M146.7 90.1h-2.7M146.7 87.5l-2.7 .1M146.7 95.1l-2.7 .1M146.7 92.6h-2.7M146.7 90l-2.7 .1"/>
<path d="M146.7 87.5h-2.7M146.7 95.1h-2.7M146.7 92.5l-2.7 .1M146.8 90l-.3 .3M146.8 92.5l-.6 1M146.8 95.1l-.6 .9M146.8 90h-2.8M146.8 87.4l-2.8 .1M146.8 87.4h-2.8M146.9 87.3l-2.9 .1M146.9 87.3l-.4 .5M146.9 87.3h-2.9"/>
<path d="M147.1 87.2l-3.1 .1M147.2 87.2h-3.2M147.4 87.1l-3.4 .1M147.4 87.1h-3.4M147.5 87l-.6 .3M149 80.4v.7M149 81.1l.2 .7M149 80.9l-19.1 .1M149 80.4h-19.2M149 80.3h-19.3M149.1 80.2l-19.4 .1M149.1 80.2h-19.4"/>
<path d="M149.2 81.8l.5 .5M149.3 86.8l.1 .2-5.4 .1M149.3 84.9v1.9M149.3 84.8l-5.3 .1M149.4 84.7l-5.3 .1M149.4 84.7h-5.3M149.4 84.6h-5.3M149.5 84.5h-5.3M149.5 84.4l-5.3 .1M149.5 84.3h-5.2M149.6 84.2l-.3 .7M149.6 84.2h-5.3"/>
<path d="M149.7 84.1h-5.4M149.7 82.3h.2M149.8 84h-5.5M149.8 83.9l-5.5 .1M149.9 82.3v1.6M149.9 83.9l-.3 .3M152.9 99.8h2M152.9 99.8l.1 .1M152.9 82.3v17.5M152.9 87h1.5M152.9 86.9h1.5M152.9 84.1h11.2"/>
<path d="M152.9 98h5.4M152.9 97.8l1.9 .1M152.9 98.1h23M152.9 97.3l1.3 .1M152.9 85.5h1.5M152.9 85.6h1.5M152.9 89.2h1M152.9 89.3h1M152.9 94.8h1.3M152.9 92.3h1.3M152.9 91.7h1M152.9 89.8h1.3"/>
<path d="M152.9 99.6h23M152.9 99.5h23M152.9 99.4h23M152.9 99.3h23M152.9 99.2h23M152.9 99.1h23M152.9 99h23M152.9 98.9h23M152.9 98.8h23M152.9 98.7h23M152.9 98.6h23M152.9 98.5h23"/>
<path d="M152.9 98.4h23M152.9 98.3h23M152.9 98.2h23M152.9 98l5.5 .1M152.9 97.9l2.1 .1M152.9 97.9h2M152.9 97.8h1.8M152.9 97.7h1.7M152.9 97.7h1.6M152.9 97.6h1.5M152.9 97.5h1.4M152.9 97.4h1.3"/>
<path d="M152.9 97.3h1.2M152.9 97.2l1.2 .1M152.9 97.2h1.2M152.9 97.1l1.1 .1M152.9 97.1h1.1M152.9 97l1.1 .1M152.9 97h1M152.9 96.9l1 .1M152.9 96.9h1M152.9 96.8l1 .1M152.9 96.8h1M152.9 96.7h.9"/>
<path d="M152.9 96.6h.9M152.9 96.5h.9M152.9 96.4h.9M152.9 96.3h.9M152.9 96.2h.9M152.9 96.1h.9M152.9 96h.9M152.9 95.9h.9M152.9 95.8h1M152.9 95.7h1M152.9 95.7h1.1M152.9 95.6h1.1"/>
<path d="M152.9 95.5h1.1M152.9 95.4h1.2M152.9 95l1.5 .1M152.9 95h1.4M152.9 94.9l1.4 .1M152.9 94.9h1.3M152.9 94.8h1.2M152.9 94.7h1.2M152.9 94.6h1.1M152.9 94.5h1.1M152.9 94.4h1M152.9 94.3h1"/>
<path d="M152.9 94.2h1M152.9 94.2h.9M152.9 94.1h.9M152.9 94h.9M152.9 93.9h.9M152.9 93.8h.9M152.9 93.7h.9M152.9 93.6h.9M152.9 93.5h.9M152.9 93.4h.9M152.9 93.3h1M152.9 93.2h1"/>
<path d="M152.9 93.1h1.1M152.9 93h1.1M152.9 92.9h1.2M152.9 92.5h1.5M152.9 92.4l1.4 .1M152.9 92.4h1.4M152.9 92.3l1.3 .1M152.9 92.2h1.2M152.9 92.1h1.2M152.9 92.1h1.1M152.9 92h1.1M152.9 91.9h1.1"/>
<path d="M152.9 91.9h1M152.9 91.8h1M152.9 91.6h.9M152.9 91.5h.9M152.9 91.4h.9M152.9 91.3h.9M152.9 91.2h.9M152.9 91.1h.9M152.9 91h.9M152.9 90.9h.9M152.9 90.8h1M152.9 90.7h1"/>
<path d="M152.9 90.6h1.1M152.9 89.9l1.5 .1M152.9 89.9h1.4M152.9 89.8l1.4 .1M152.9 89.7h1.3M152.9 89.7h1.2M152.9 89.6h1.2M152.9 89.5h1.1M152.9 89.4h1.1M152.9 89.1l1 .1M152.9 89.1h.9M152.9 89h.9"/>
<path d="M152.9 88.9h.9M152.9 88.8h.9M152.9 88.7h.9M152.9 88.6h.9M152.9 88.5h.9M152.9 88.4h.9M152.9 88.3h.9M152.9 88.3h1M152.9 88.2h1M152.9 88.1h1M152.9 88h1.1M152.9 87.3h1.6"/>
<path d="M152.9 87.3h1.5M152.9 87.2h1.5M152.9 87.1h1.5M152.9 86.8h1.5M152.9 86.7h1.5M152.9 86.6h1.5M152.9 86.5h1.5M152.9 86.4h1.5M152.9 86.3h1.5M152.9 86.2h1.5M152.9 86.1h1.5M152.9 86h1.5"/>
<path d="M152.9 85.9h1.5M152.9 85.8h1.5M152.9 85.7h1.5M152.9 85.4h1.5M152.9 85.2h1.6M152.9 84.8h1.8M152.9 84.5h2.1M152.9 84h11.2M152.9 83.9h11.2M152.9 83.8h11.2M152.9 83.7h11.2M152.9 83.6h11.2"/>
<path d="M152.9 83.5h11.2M152.9 83.4h11.2M152.9 83.3h11.2M152.9 83.2h11.2M152.9 83.1h11.2M152.9 83h11.2M152.9 82.9h11.2M152.9 82.8h11.2M152.9 82.7h11.2M152.9 82.6h11.2M152.9 82.5h11.2M152.9 82.4h11.2"/>
<path d="M152.9 82.3h11.2M153 82.3h-.1M153 82.3h11.1M153.1 82.2h11M153.2 82.1h10.9M153.3 82h10.8M153.4 81.9h10.7M153.5 81.9h10.6M153.5 81.8h10.6M153.5 81.8l-.5 .5M153.5 81.7h10.6M153.6 81.7h10.5"/>
<path d="M153.6 81.6h10.5M153.6 81.5h10.5M153.7 81.4h10.4M153.7 80.1h10.4M153.7 81.3h10.4M153.7 80.2h10.4M153.7 81.2h10.4M153.7 80.3h10.4M153.8 81.2h10.3M153.8 80.3h10.3M153.8 80.4h10.3M153.8 80.9h10.3"/>
<path d="M153.8 81.1h10.3M153.8 81h10.3M153.8 80.8h10.3M153.8 80.7h10.3M153.8 80.6h10.3M153.8 80.5h10.3M153.8 88.4v.6M153.8 90.9v.7M153.8 93.5v.6M153.8 96v.7M153.8 89l.6 1M153.8 91.6l.6 .9"/>
<path d="M153.8 94.1l.3 .6M153.8 96.7l.3 .6M153.9 95.9h-1M153.9 93.3l-1 .1M153.9 90.7h-1M153.9 88.2h-1M153.9 90.6h-1M153.9 88.1h-1M154 90.5h-1.1M154 88h-1.1M154 95.5l-1.1 .1M154 93h-1.1"/>
<path d="M154 87.9h-1.1M154 90.4h-1.1M154.1 92.9h-1.2M154.1 90.4h-1.2M154.1 87.8h-1.2M154.1 87.8l-.3 .6M154.1 90.3l-.3 .6M154.1 94.7l.3 .4M154.1 97.3l.4 .4M154.1 90.3h-1.2M154.1 95.3l-1.2 .1M154.1 92.8h-1.2"/>
<path d="M154.1 87.7h-1.2M154.2 95.3h-1.3M154.2 92.8h-1.3M154.2 90.2h-1.3M154.2 87.7h-1.3M154.2 95.2l-1.3 .1M154.2 92.7h-1.3M154.2 90.1l-1.3 .1M154.2 87.6h-1.3M154.3 95.2h-1.4M154.3 92.6l-1.4 .1M154.3 90.1h-1.4"/>
<path d="M154.3 87.5l-1.4 .1M154.3 95.1l-1.4 .1M154.3 92.6h-1.4M154.3 90l-1.4 .1M154.3 87.5h-1.4M154.4 87.2l.1 .2M154.4 95.1h-1.5M154.4 92.5l-1.5 .1M154.4 90l-.3 .3M154.4 92.5l-.6 1M154.4 95.1l-.6 .9M154.4 90h-1.5"/>
<path d="M154.4 85.5h-1.5M154.4 87.4l-1.5 .1M154.4 87.4h-1.5M154.4 85.4h-1.5M154.5 87.4l-.4 .4M154.5 85.3h-1.6M154.5 85.3l-.1 1.9M154.5 85.1v.2M154.5 97.7l.7 .3M154.5 85.1h-1.6M154.6 85l-1.7 .1M154.6 85h-1.7"/>
<path d="M154.6 84.9l-1.7 .1M154.6 84.9h-1.7M154.6 84.9l-.1 .2M154.7 84.8l-1.8 .1M154.8 84.7l-1.9 .1M154.8 84.7h-1.9M154.9 84.6l-2 .1M154.9 84.6h-2M155 84.5h-2.1M155 99.8h-2.1M155.1 84.4l-2.2 .1M155.1 84.4h-2.2"/>
<path d="M155.2 99.7l-.4 .2h-1.5M155.3 84.3h-2.4M155.4 84.3h-2.5M155.4 84.2l-.8 .7M155.4 84.2h-2.5M155.6 84.2h-2.7M155.8 84.1h-2.9M155.8 84.1l-.2 .1M156.5 84.1l.2 .1M156.5 84.1h7.6M156.7 84.2h7.4M156.8 84.2l.8 .7"/>
<path d="M156.8 84.2h7.3M156.9 84.3h7.2M157 84.3h7.1M157.1 98l.8-.1 .6 .2M157.2 84.4h6.9M157.2 84.4h1.3M157.2 98h1M157.3 84.5h1M157.3 99.8h.8M157.3 97.9h.8M157.4 99.8h.6M157.4 84.6h.7"/>
<path d="M157.4 84.6h.6M157.5 84.7h.4M157.5 84.7h.3M157.6 84.8h.2M157.6 84.8h.1M157.6 84.9h.1M158.3 99.7l-5.4 .1M158.4 99.7h-5.5M158.5 99.6l-.6 .3-.8-.2M158.5 84.4l-.9 .5M160.7 99.6l.6 .3 .5-.3M160.7 84.4a1.84 1.84 0 0 1 1.5 2.1"/>
<path d="M160.7 98.1l.7-.2h10l.6 .2M160.8 84.4h3.3M160.8 98.1h11.1M160.9 99.7h.8M160.9 84.5h3.2M161 98h10.8M161 99.7h.6M161 84.5h3.1M161.1 98h10.5M161.1 99.8h.3M161.2 84.6h2.9M161.2 97.9h10.3"/>
<path d="M161.2 99.8h.1M161.3 84.6h2.8M161.4 84.7h2.7M161.5 84.7h2.6M161.5 84.8h2.6M161.6 84.8h2.5M161.6 84.9h2.5M161.7 84.9h2.4M161.7 85h2.4M161.8 85h2.3M161.8 85.1h2.3M161.9 85.2h2.2"/>
<path d="M161.9 85.3h2.2M162 85.3h2.1M162 85.4h2.1M162 86.9h2.1M162 86.8h2.1M162 85.5h2.1M162.1 85.5h2M162.1 86.8h2M162.1 86.7h2M162.1 85.6h2M162.1 86.6h2M162.1 85.7h2"/>
<path d="M162.2 86.6h1.9M162.2 85.8h1.9M162.2 86.5l-.2 .4h2.1M162.2 86.5h1.9M162.2 86.4h1.9M162.2 86.3h1.9M162.2 86.2h1.9M162.2 86.1h1.9M162.2 86h1.9M162.2 85.9h1.9M163.5 99.6l12.4 .1M163.5 86.9l.2 .1"/>
<path d="M163.6 87h.5M163.6 99.7h12.3M163.7 87h.4M163.8 99.7l.1 .1M163.8 87l.3 .2M163.9 87.1h.2M163.9 99.8h12M163.9 99.8l.2 .1M164 99.8h11.9M164.1 87.2h.1M164.1 99.9l.6 .7M164.1 99.9h11.8"/>
<path d="M164.1 80.1h-10.5l.2 1-.3 .7M164.1 80.1v7.1M164.2 99.9h11.7M165.9 92.2h8.1M166 92.1h8M166.1 92h7.9M166.2 91.9h7.8M166.3 91.8h7.7M166.4 91.7h7.6M166.5 91.7h7.5M166.5 91.6l-.7 .7h8.1M166.5 91.6h7.5"/>
<path d="M166.6 91.5h7.4M166.7 91.4h7.3M166.8 91.3h7.2M166.9 91.2h7.1M167 91.1h7M167 91h7M167.1 90.9h6.9M167.1 90.8h6.9M167.2 90.7h6.8M167.2 90.6h6.8M167.2 80.1h6.8M167.2 87h6.8"/>
<path d="M167.2 86.9h6.8M167.2 84.4h6.8M167.2 84.2h6.8M167.2 84.1h6.8M167.2 80.9h6.8M167.2 85.5h6.8M167.2 85.6h6.8M167.2 89.2h6.8M167.2 89.3h6.8M167.2 81.9h6.8M167.2 89.8h6.8M167.2 90.6l-.2 .6-.5 .4"/>
<path d="M167.2 90.5h6.8M167.2 90.4h6.8M167.2 90.3h6.8M167.2 90.2h6.8M167.2 90.1h6.8M167.2 90h6.8M167.2 89.9h6.8M167.2 89.7h6.8M167.2 89.6h6.8M167.2 89.5h6.8M167.2 89.4h6.8M167.2 89.1h6.8"/>
<path d="M167.2 89h6.8M167.2 88.9h6.8M167.2 88.8h6.8M167.2 88.7h6.8M167.2 88.6h6.8M167.2 88.5h6.8M167.2 88.4h6.8M167.2 88.3h6.8M167.2 88.2h6.8M167.2 88.1h6.8M167.2 88h6.8M167.2 87.9h6.8"/>
<path d="M167.2 87.8h6.8M167.2 87.7h6.8M167.2 87.6h6.8M167.2 87.5h6.8M167.2 87.4h6.8M167.2 87.3h6.8M167.2 87.2h6.8M167.2 87.1h6.8M167.2 86.8h6.8M167.2 86.7h6.8M167.2 86.6h6.8M167.2 86.5h6.8"/>
<path d="M167.2 86.4h6.8M167.2 86.3h6.8M167.2 86.2h6.8M167.2 86.1h6.8M167.2 86h6.8M167.2 85.9h6.8M167.2 85.8h6.8M167.2 85.7h6.8M167.2 85.4h6.8M167.2 85.3h6.8M167.2 85.2h6.8M167.2 85.1h6.8"/>
<path d="M167.2 85h6.8M167.2 84.9h6.8M167.2 84.8h6.8M167.2 84.7h6.8M167.2 84.6h6.8M167.2 84.5h6.8M167.2 84.3h6.8M167.2 84h6.8M167.2 83.9h6.8M167.2 83.8h6.8M167.2 83.7h6.8M167.2 83.6h6.8"/>
<path d="M167.2 83.5h6.8M167.2 83.4h6.8M167.2 83.3h6.8M167.2 83.2h6.8M167.2 83.1h6.8M167.2 83h6.8M167.2 82.9h6.8M167.2 82.8h6.8M167.2 82.7h6.8M167.2 82.6h6.8M167.2 82.5h6.8M167.2 82.4h6.8"/>
<path d="M167.2 82.3h6.8M167.2 82.2h6.8M167.2 82.1h6.8M167.2 82h6.8M167.2 81.8h6.8M167.2 81.7h6.8M167.2 81.6h6.8M167.2 81.5h6.8M167.2 81.4h6.8M167.2 81.3h6.8M167.2 81.2h6.8M167.2 81.1h6.8"/>
<path d="M167.2 81h6.8M167.2 80.8h6.8M167.2 80.7h6.8M167.2 80.6h6.8M167.2 80.5h6.8M167.2 80.4h6.8M167.2 80.3h6.8M167.2 80.2h6.8M173.7 98.1h2.2M173.8 98h2.1M174 92.2l-.1 .1M174 98h1.9"/>
<path d="M174 92.2h-8.1M174.1 97.9h1.8M174.2 97.9h1.7M174.3 97.8h1.6M174.4 97.7h1.5M174.5 97.6h1.4M174.6 97.5h1.3M174.7 97.4h1.2M174.8 95.3a1.79 1.79 0 0 1-1.2 2.8M174.8 97.3h1.1M174.8 95.3h1.1M174.8 95.4h1.1"/>
<path d="M174.8 97.2h1.1M174.9 97.2h1M174.9 95.5h1M174.9 97.1h1M174.9 97h1M174.9 95.6h1M174.9 95.7h1M174.9 96.9h1M174.9 95.3h1M175 96.9h.9M175 95.8h.9M175 96.8h.9"/>
<path d="M175 95.9h.9M175 96.7h.9M175 96h.9M175.1 96.6h.8M175.1 96.5h.8M175.1 96.4h.8M175.1 96.3h.8M175.1 96.2h.8M175.1 96.1h.8M175.1 96h.8M175.1 95.2h.8M175.2 95.2h.7"/>
<path d="M175.4 95.1h.5M175.5 95h.4M175.6 94.9h.3M175.6 94.8h.3M175.7 94.8h.2M175.7 94.7h.2M175.8 94.7h.1M175.9 94.7l-.5 .4-.5 .2M175.9 94.7h.1M175.9 94.6h.1M175.9 99.6l-23 .1M175.9 95.3h-1.1"/>
<path d="M175.9 94.6v.1M175.9 94.6v7.8M180.8 99.7h.9M180.8 99.6h.9M180.8 99.9h.9M180.8 99.8h.9M180.8 80.1h.9M180.8 87h.9M180.8 86.9h.9M180.8 84.4h.9M180.8 84.2h.9M180.8 84.1h.9"/>
<path d="M180.8 98h.9M180.8 97.8h.9M180.8 98.1h.9M180.8 95.3h.9M180.8 97.3h.9M180.8 80.9h.9M180.8 85.5h.9M180.8 85.6h.9M180.8 89.2h.9M180.8 89.3h.9M180.8 94.8h.9M180.8 92.3h.9"/>
<path d="M180.8 81.9h.9M180.8 91.7h.9M180.8 89.8h.9M180.8 99.5h.9M180.8 99.4h.9M180.8 99.3h.9M180.8 99.2h.9M180.8 99.1h.9M180.8 99h.9M180.8 98.9h.9M180.8 98.8h.9M180.8 98.7h.9"/>
<path d="M180.8 98.6h.9M180.8 98.5h.9M180.8 98.4h.9M180.8 98.3h.9M180.8 98.2h.9M180.8 97.9h.9M180.8 97.7h.9M180.8 97.6h.9M180.8 97.5h.9M180.8 97.4h.9M180.8 97.2h.9M180.8 97.1h.9"/>
<path d="M180.8 97h.9M180.8 96.9h.9M180.8 96.8h.9M180.8 96.7h.9M180.8 96.6h.9M180.8 96.5h.9M180.8 96.4h.9M180.8 96.3h.9M180.8 96.2h.9M180.8 96.1h.9M180.8 96h.9M180.8 95.9h.9"/>
<path d="M180.8 95.8h.9M180.8 95.7h.9M180.8 95.6h.9M180.8 95.5h.9M180.8 95.4h.9M180.8 95.2h.9M180.8 95.1h.9M180.8 95h.9M180.8 94.9h.9M180.8 94.7h.9M180.8 94.6h.9M180.8 94.5h.9"/>
<path d="M180.8 94.4h.9M180.8 94.3h.9M180.8 94.2h.9M180.8 94.1h.9M180.8 94h.9M180.8 93.9h.9M180.8 93.8h.9M180.8 93.7h.9M180.8 93.6h.9M180.8 93.5h.9M180.8 93.4h.9M180.8 93.3h.9"/>
<path d="M180.8 93.2h.9M180.8 93.1h.9M180.8 93h.9M180.8 92.9h.9M180.8 92.8h.9M180.8 92.7h.9M180.8 92.6h.9M180.8 92.5h.9M180.8 92.4h.9M180.8 92.2h.9M180.8 92.1h.9M180.8 92h.9"/>
<path d="M180.8 91.9h.9M180.8 91.8h.9M180.8 91.6h.9M180.8 91.5h.9M180.8 91.4h.9M180.8 91.3h.9M180.8 91.2h.9M180.8 91.1h.9M180.8 91h.9M180.8 90.9h.9M180.8 90.8h.9M180.8 90.7h.9"/>
<path d="M180.8 90.6h.9M180.8 90.5h.9M180.8 90.4h.9M180.8 90.3h.9M180.8 90.2h.9M180.8 90.1h.9M180.8 90h.9M180.8 89.9h.9M180.8 89.7h.9M180.8 89.6h.9M180.8 89.5h.9M180.8 89.4h.9"/>
<path d="M180.8 89.1h.9M180.8 89h.9M180.8 88.9h.9M180.8 88.8h.9M180.8 88.7h.9M180.8 88.6h.9M180.8 88.5h.9M180.8 88.4h.9M180.8 88.3h.9M180.8 88.2h.9M180.8 88.1h.9M180.8 88h.9"/>
<path d="M180.8 87.9h.9M180.8 87.8h.9M180.8 87.7h.9M180.8 87.6h.9M180.8 87.5h.9M180.8 87.4h.9M180.8 87.3h.9M180.8 87.2h.9M180.8 87.1h.9M180.8 86.8h.9M180.8 86.7h.9M180.8 86.6h.9"/>
<path d="M180.8 86.5h.9M180.8 86.4h.9M180.8 86.3h.9M180.8 86.2h.9M180.8 86.1h.9M180.8 86h.9M180.8 85.9h.9M180.8 85.8h.9M180.8 85.7h.9M180.8 85.4h.9M180.8 85.3h.9M180.8 85.2h.9"/>
<path d="M180.8 85.1h.9M180.8 85h.9M180.8 84.9h.9M180.8 84.8h.9M180.8 84.7h.9M180.8 84.6h.9M180.8 84.5h.9M180.8 84.3h.9M180.8 84h.9M180.8 83.9h.9M180.8 83.8h.9M180.8 83.7h.9"/>
<path d="M180.8 83.6h.9M180.8 83.5h.9M180.8 83.4h.9M180.8 83.3h.9M180.8 83.2h.9M180.8 83.1h.9M180.8 83h.9M180.8 82.9h.9M180.8 82.8h.9M180.8 82.7h.9M180.8 82.6h.9M180.8 82.5h.9"/>
<path d="M180.8 82.4h.9M180.8 82.3h.9M180.8 82.2h.9M180.8 82.1h.9M180.8 82h.9M180.8 81.8h.9M180.8 81.7h.9M180.8 81.6h.9M180.8 81.5h.9M180.8 81.4h.9M180.8 81.3h.9M180.8 81.2h.9"/>
<path d="M180.8 81.1h.9M180.8 81h.9M180.8 80.8h.9M180.8 80.7h.9M180.8 80.6h.9M180.8 80.5h.9M180.8 80.4h.9M180.8 80.3h.9M180.8 80.2h.9M187.7 80.1h15.3M187.7 87h15.3M187.7 86.9h15.3"/>
<path d="M187.7 84.4h15.3M187.7 84.2h15.3M187.7 84.1h15.3M187.7 95.3h1.6M187.7 80.9h15.3M187.7 85.5h15.3M187.7 85.6h15.3M187.7 89.2h15.3M187.7 89.3h15.3M187.7 94.8h1.6M187.7 92.3h1.1M187.7 81.9h15.3"/>
<path d="M187.7 91.7h1M187.7 97h.1M187.7 96.9h.1M187.7 96.8h.2M187.7 96.7h.2M187.7 95.6h1.6M187.7 95.5h1.6M187.7 95.4h1.6M187.7 95.2h1.6M187.7 95.1h1.6M187.7 95h1.6M187.7 94.9h1.6"/>
<path d="M187.7 94.7h1.6M187.7 94.6h1.6M187.7 94.5h1.6M187.7 94.4h1.6M187.7 94.3h1.6M187.7 94.2h1.6M187.7 94.1h1.6M187.7 94h1.6M187.7 93.9h1.6M187.7 93.8h1.6M187.7 93.7h1.6M187.7 93.6h1.6"/>
<path d="M187.7 93.5h1.6M187.7 93.4h1.6M187.7 93.3h1.6M187.7 93.2h1.6M187.7 93.1h1.6M187.7 93h1.6M187.7 92.9h1.6M187.7 92.9h1.5M187.7 92.8h1.5M187.7 92.8h1.4M187.7 92.7h1.4M187.7 92.6l1.3 .1"/>
<path d="M187.7 92.6h1.3M187.7 92.5h1.2M187.7 92.4h1.2M187.7 92.4h1.1M187.7 92.2h1.1M187.7 92.1h1M187.7 92h1M187.7 91.9l1 .1M187.7 91.9h1M187.7 91.8h1M187.7 91.6h1M187.7 91.5h1"/>
<path d="M187.7 91.4h1M187.7 91.3h1M187.7 91.2h1M187.7 91.1h1M187.7 91h1M187.7 90.9h1.1M187.7 90.8h1.1M187.7 90.7h1.2M187.7 90.6h1.2M187.7 89.7h15.3M187.7 89.6h15.3M187.7 89.5h15.3"/>
<path d="M187.7 89.4h15.3M187.7 89.1h15.3M187.7 89h15.3M187.7 88.9h15.3M187.7 88.8h15.3M187.7 88.7h15.3M187.7 88.6h15.3M187.7 88.5h15.3M187.7 88.4h15.3M187.7 88.3h15.3M187.7 88.2h15.3M187.7 88.1h15.3"/>
<path d="M187.7 88h15.3M187.7 87.9h15.3M187.7 87.8h15.3M187.7 87.7h15.3M187.7 87.6h15.3M187.7 87.5h15.3M187.7 87.4h15.3M187.7 87.3h15.3M187.7 87.2h15.3M187.7 87.1h15.3M187.7 86.8h15.3M187.7 86.7h15.3"/>
<path d="M187.7 86.6h15.3M187.7 86.5h15.3M187.7 86.4h15.3M187.7 86.3h15.3M187.7 86.2h15.3M187.7 86.1h15.3M187.7 86h15.3M187.7 85.9h15.3M187.7 85.8h15.3M187.7 85.7h15.3M187.7 85.4h15.3M187.7 85.3h15.3"/>
<path d="M187.7 85.2h15.3M187.7 85.1h15.3M187.7 85h15.3M187.7 84.9h15.3M187.7 84.8h15.3M187.7 84.7h15.3M187.7 84.6h15.3M187.7 84.5h15.3M187.7 84.3h15.3M187.7 84h15.3M187.7 83.9h15.3M187.7 83.8h15.3"/>
<path d="M187.7 83.7h15.3M187.7 83.6h15.3M187.7 83.5h15.3M187.7 83.4h15.3M187.7 83.3h15.3M187.7 83.2h15.3M187.7 83.1h15.3M187.7 83h15.3M187.7 82.9h15.3M187.7 82.8h15.3M187.7 82.7h15.3M187.7 82.6h15.3"/>
<path d="M187.7 82.5h15.3M187.7 82.4h15.3M187.7 82.3h15.3M187.7 82.2h15.3M187.7 82.1h15.3M187.7 82h15.3M187.7 81.8h15.3M187.7 81.7h15.3M187.7 81.6h15.3M187.7 81.5h15.3M187.7 81.4h15.3M187.7 81.3h15.3"/>
<path d="M187.7 81.2h15.3M187.7 81.1h15.3M187.7 81h15.3M187.7 80.8h15.3M187.7 80.7h15.3M187.7 80.6h15.3M187.7 80.5h15.3M187.7 80.4h15.3M187.7 80.3h15.3M187.7 80.2h15.3M187.8 96.9l-.1 .1M187.9 96.8l-.2 .1"/>
<path d="M187.9 96.6l-.2 .5M188 96.6h-.3M188.1 96.5h-.4M188.2 96.4h-.5M188.3 96.3h-.6M188.3 96.2l-.6 .1M188.4 96.2h-.7M188.4 96.1l-.7 .1M188.5 96.1h-.8M188.6 96l-.9 .1M188.7 91.2v.7M188.7 91.9l.2 .7 .4 .4"/>
<path d="M188.7 96h-1M188.7 91.1l-1 .1M188.7 91l-1 .1M188.7 95.9h-1M188.8 90.7l-1.1 .1M188.9 95.9h-1.2M188.9 90.6l-.2 .6M189 90.5l-1.3 .1M189 95.8h-1.3M189 90.5h-1.3M189.1 90.4h-1.4M189.2 95.8h-1.5"/>
<path d="M189.2 90.3h-1.5M189.3 95.7h-1.6M189.3 90.2h-1.6M189.3 93v2.7M189.3 95.7l-.7 .3-.7 .6M189.3 90.1l-1.6 .1M189.4 90.1h-1.7M189.5 90l-1.8 .1M189.7 90h-2M189.7 89.9l-2 .1M189.9 89.9h-2.2M190 89.8l-2.3 .1"/>
<path d="M190.1 89.8l-.7 .3-.5 .5M192 89.8l.7 .3 .5 .5M192.1 89.8h10.9M192.2 89.9h10.8M192.4 89.9h10.6M192.5 90h10.5M192.6 90h10.4M192.7 90.1h10.3M192.8 90.1h10.2M192.8 90.2h10.2M192.9 94.8h1.5M192.9 95.3l.7 .7"/>
<path d="M192.9 92.9v2.4M192.9 95.2h1.5M192.9 95.1h1.5M192.9 95h1.5M192.9 94.9h1.5M192.9 94.8h1.4M192.9 94.7h1.4M192.9 94.7h1.3M192.9 94.6h1.3M192.9 94.6h1.2M192.9 94.5h1.2M192.9 94.4h1.1"/>
<path d="M192.9 94.3h1.1M192.9 94.3h1M192.9 94.2h1M192.9 94.1h1M192.9 94.1h.9M192.9 94h.9M192.9 93.9h.9M192.9 93.8h.8M192.9 93.7h.8M192.9 93.6h.8M192.9 93.5h.8M192.9 93.4h.8"/>
<path d="M192.9 93.3h.8M192.9 93.2h.8M192.9 93.1h.8M192.9 95.3h1.5M192.9 90.3h10.1M192.9 95.3h1.4M193 95.4h1.2M193 90.4h10M193.1 95.5h1.1M193.1 90.5h9.9M193.1 95.5h1M193.2 90.6l.3 .6"/>
<path d="M193.2 95.6h.8M193.2 92.5h.8M193.2 90.6h9.8M193.3 95.7h.7M193.3 90.7h9.7M193.3 90.8h9.7M193.3 95.7h.6M193.3 95.8h.6M193.3 90.9h9.7M193.4 90.9h9.6M193.4 91h9.6M193.4 95.8h.4"/>
<path d="M193.4 91.1h9.6M193.5 91.2v.7M193.5 91.9l-.3 .7-.3 .3M193.5 95.9h.3M193.5 91.6h9.5M193.5 91.5h9.5M193.5 91.4h9.5M193.5 91.3h9.5M193.5 91.2h9.5M193.5 95.9h.2M193.6 96h.1M193.7 93.1v.7"/>
<path d="M193.7 93.8l.3 .7 .4 .3M193.8 93.1h-.9M193.8 93h-.9M193.8 92.9h-.9M193.9 92.8h-1M193.9 92.8h-.9M193.9 92.7h-.9M193.9 92.6l-.8 .1M194 92.6h-.9M194 92.5l-.3 .6M194 92.5h-.8M194 92.4l-.7 .1"/>
<path d="M194.1 92.4h-.8M194.2 92.3l-.9 .1M194.2 92.3h-.9M194.3 92.2h-1M194.3 92.2h-.9M194.4 94.8v.5M194.4 95.3l-.8 .7M194.4 92.1h-1M194.5 92h-1.1M194.6 91.9l-1.2 .1M194.7 91.9h-1.2M194.8 91.8l-1.3 .1"/>
<path d="M195 91.8h-1.5M195.1 91.7l-1.6 .1M195.2 91.7l-.7 .3-.5 .5M197.1 91.7l.7 .3 .5 .5M197.2 91.7h5.8M197.3 91.8h5.7M197.5 91.8h5.5M197.5 91.9h5.5M197.7 91.9h5.3M197.8 92h5.2M197.9 92.1h5.1M197.9 95.3h5.1"/>
<path d="M197.9 94.8h5.1M197.9 94.8v.9M197.9 95.7l.7 .3 .7 .6M197.9 95.7h5.1M197.9 95.6h5.1M197.9 95.5h5.1M197.9 95.4h5.1M197.9 95.2h5.1M197.9 95.1h5.1M197.9 95h5.1M197.9 94.9h5.1M198 94.8h5"/>
<path d="M198 92.2h5M198 95.8h5M198 94.7h5M198.1 92.3h4.9M198.1 94.7h4.9M198.1 94.6h4.9M198.2 95.8h4.8M198.2 94.6h4.8M198.2 92.4h4.8M198.2 94.5h4.8M198.3 100h4.7M198.3 92.5l.2 .6"/>
<path d="M198.3 95.9h4.7M198.3 94.4h4.7M198.3 92.5h4.7M198.3 94.3h4.7M198.3 92.6h4.7M198.4 94.3h4.6M198.4 92.6h4.6M198.4 94.2h4.6M198.4 92.7h4.6M198.4 92.8h4.6M198.4 99.9h4.6M198.4 94.1h4.6"/>
<path d="M198.4 92.9h4.6M198.5 95.9h4.5M198.5 94h4.5M198.5 92.9h4.5M198.5 93h4.5M198.5 99.9h4.5M198.5 93.9h4.5M198.5 93.1h4.5M198.5 93.1v.7M198.5 93.8l-.2 .7-.4 .3M198.5 96h4.5M198.5 93.8h4.5"/>
<path d="M198.5 93.7h4.5M198.5 93.6h4.5M198.5 93.5h4.5M198.5 93.4h4.5M198.5 93.3h4.5M198.5 93.2h4.5M198.6 99.8h4.4M198.7 96h4.3M198.7 99.8h4.3M198.7 96.1h4.3M198.8 99.7h4.2M198.8 96.1h4.2"/>
<path d="M198.8 96.2h4.2M198.9 99.6h4.1M198.9 96.2h4.1M198.9 96.3h4.1M199 99.5h4M199 96.4h4M199.1 99.4h3.9M199.1 96.5h3.9M199.2 99.3h3.8M199.2 96.6h3.8M199.3 99.2l-.7 .6-.7 .3M199.3 96.6l.3 .9"/>
<path d="M199.3 99.2h3.7M199.3 99.1h3.7M199.3 96.7h3.7M199.3 99h3.7M199.3 96.8h3.7M199.4 99h3.6M199.4 98.9h3.6M199.4 96.9h3.6M199.4 98.8h3.6M199.4 97h3.6M199.5 98.7h3.5M199.5 97.1h3.5"/>
<path d="M199.5 98.6h3.5M199.5 97.2h3.5M199.5 98.5h3.5M199.5 97.3h3.5M199.6 97.3h3.4M199.6 98.5h3.4M199.6 98.4h3.4M199.6 97.4h3.4M199.6 97.5h3.4M199.6 98h3.4M199.6 97.8h3.4M199.6 98.1h3.4"/>
<path d="M199.6 97.5v.9M199.6 98.4l-.3 .8M199.6 98.3h3.4M199.6 98.2h3.4M199.6 97.9h3.4M199.6 97.7h3.4M199.6 97.6h3.4M203 91.7h-9.5M203 89.8h-15.3M97.8 102.4h2.2M97.8 100.4h2.2M97.8 100.5h2.2"/>
<path d="M97.8 102.3h2.2M97.8 102.2h2.2M97.8 105h2.2M97.8 110.5h12.6M97.8 108.6h2M97.8 117.6h12.5M97.8 102.9h2.2M97.8 109.6h2.2M97.8 109.7h2.3M97.8 106.4h2.2M97.8 106.5h2.2M97.8 105.6h2.2"/>
<path d="M97.8 105.7h2.2M97.8 119.8h1M97.8 119.5h1.3M97.8 118.9h12.2M97.8 118.8h12.2M97.8 117.9h12.8M97.8 117.8l12.7 .1M97.8 117.8h12.7M97.8 117.7h12.6M97.8 117.6l12.6 .1M97.8 117.5l12.5 .1M97.8 117.5h12.4"/>
<path d="M97.8 117.4l12.4 .1M97.8 117.4h12.4M97.8 117.3l12.4 .1M97.8 117.3h12.4M97.8 117.2l12.3 .1M97.8 117.2h12.3M97.8 117.1l12.3 .1M97.8 117.1h12.2M97.8 117l12.2 .1M97.8 117h12.2M97.8 116.9h12.2M97.8 116.8h12.2"/>
<path d="M97.8 116.7h12.2M97.8 116.6h12.2M97.8 116.5h12.2M97.8 116.4h12.2M97.8 116.3h12.2M97.8 115.9h12.4M97.8 115.8h12.4M97.8 115.7h12.5M97.8 115.3h12.8M97.8 115.3h12.7M97.8 115.2l12.7 .1M97.8 115.2h12.6"/>
<path d="M97.8 115.1h12.6M97.8 115.1h12.5M97.8 115h12.5M97.8 115h12.4M97.8 114.9h12.4M97.8 114.8h12.4M97.8 114.7l12.4 .1M97.8 114.7h12.3M97.8 114.6h12.3M97.8 114.5h12.2M97.8 114.4h12.2M97.8 114.3h12.2"/>
<path d="M97.8 114.2h12.2M97.8 114.1h12.2M97.8 114h12.2M97.8 113.9h12.2M97.8 113.8h12.2M97.8 113.4h12.4M97.8 113.3h12.4M97.8 113.2h12.5M97.8 112.8h12.8M97.8 112.7h12.7M97.8 112.6h12.6M97.8 112.5h12.5"/>
<path d="M97.8 112.4h12.4M97.8 112.3h12.4M97.8 112.2l12.4 .1M97.8 112.2h12.4M97.8 112.1l12.3 .1M97.8 112.1h12.3M97.8 112l12.3 .1M97.8 112h12.2M97.8 111.9l12.2 .1M97.8 111.9h12.2M97.8 111.8h12.2M97.8 111.7h12.2"/>
<path d="M97.8 111.6h12.2M97.8 111.5h12.2M97.8 111.4h12.2M97.8 111.3h12.2M97.8 111.2h12.2M97.8 111.1h12.3M97.8 111h12.3M97.8 110.9h12.4M97.8 110.8h12.4M97.8 110.7h12.4M97.8 110.4l3.4 .1M97.8 110.4h3.2"/>
<path d="M97.8 110.3l3.1 .1M97.8 110.3h3M97.8 110.2l2.8 .1M97.8 110.2h2.7M97.8 110.1l2.7 .1M97.8 110.1h2.6M97.8 110h2.6M97.8 110h2.5M97.8 109.9h2.5M97.8 109.9h2.4M97.8 109.8h2.4M97.8 109.7l2.3 .1"/>
<path d="M97.8 109.6l2.2 .1M97.8 109.5l2.2 .1M97.8 109.5h2.1M97.8 109.4l2.1 .1M97.8 109.4h2.1M97.8 109.3l2.1 .1M97.8 109.3h2.1M97.8 109.2h2M97.8 109.1h2M97.8 109h2M97.8 108.9h2M97.8 108.8h2"/>
<path d="M97.8 108.7h2M97.8 108.5h2M97.8 108.4h2M97.8 108.3h2M97.8 108.2h2M97.8 108.1h2M97.8 108h2M97.8 107.9h2M97.8 107.8h2M97.8 107.7h2M97.8 107.6h2M97.8 107.5h2"/>
<path d="M97.8 107.4h2M97.8 107.3h2M97.8 107.2h2M97.8 107.1h2M97.8 107h2M97.8 106.8h2.1M97.8 106.7h2.1M97.8 106.6h2.1M97.8 106.6h2.2M97.8 106.3h2.2M97.8 106.2h2.2M97.8 106.1h2.2"/>
<path d="M97.8 106h2.2M97.8 105.9h2.2M97.8 105.8h2.2M97.8 105.5h2.2M97.8 105.4h2.2M97.8 105.3h2.2M97.8 105.2h2.2M97.8 105.1h2.2M97.8 104.9h2.2M97.8 104.8h2.2M97.8 104.7h2.2M97.8 104.6h2.2"/>
<path d="M97.8 104.5h2.2M97.8 104.4h2.2M97.8 104.3h2.2M97.8 104.2h2.2M97.8 104.1h2.2M97.8 104h2.2M97.8 103.9h2.2M97.8 103.8h2.2M97.8 103.7h2.2M97.8 103.6h2.2M97.8 103.5h2.2M97.8 103.4h2.2"/>
<path d="M97.8 103.3h2.2M97.8 103.2h2.2M97.8 103.1h2.2M97.8 103h2.2M97.8 102.8h2.2M97.8 102.7h2.2M97.8 102.6h2.2M97.8 102.5h2.2M97.8 102.1h2.2M97.8 102h2.2M97.8 101.9h2.2M97.8 101.8h2.2"/>
<path d="M97.8 101.7h2.2M97.8 101.6h2.2M97.8 101.5h2.2M97.8 101.4h2.2M97.8 101.3h2.2M97.8 101.2h2.2M97.8 101.1h2.2M97.8 101h2.2M97.8 100.9h2.2M97.8 100.8h2.2M97.8 100.7h2.2M97.8 100.6h2.2"/>
<path d="M97.8 100.3h2.2M97.8 100.2h2.2M97.8 100.1h2.2M97.8 100h2.2M98.6 120h-.8M98.6 119.9l-.8 .1M98.7 119.9h-.9M98.7 119.8h-.9M98.8 119.7l-1 .1M98.9 119.7h-1.1M98.9 119.6l-1.1 .1M99 119.6h-1.2"/>
<path d="M99 119.5h-1.2M99.1 119.4h-1.3M99.2 119.4h-1.4M99.3 119.3h-1.5M99.5 119.2h-1.7M99.6 119.1l-1.8 .1M99.7 119.1h-1.9M99.8 107.1v2M99.8 109.1l.2 .6 .5 .5M99.8 107.1h-2M99.8 107h-2M99.8 119l-2 .1"/>
<path d="M99.8 106.9h-2M99.9 106.8h-2.1M99.9 119l-.6 .3-1.3 1.2M100 106.5l-.2 .6M100.5 110.2l.7 .3M102.2 110.4h8.3M102.4 110.3h8.2M102.6 110.2l-.7 .3M102.6 110.2h7.9M102.6 110.1h7.8M102.7 110.1h7.7M102.7 110h7.6"/>
<path d="M102.8 109.9h7.4M102.9 109.9h7.3M102.9 109.8h7.3M103 109.8h7.2M103 109.7l-.4 .5M103 109.7h7.2M103.1 100.5h10.6M103.1 105h4M103.1 106.5h.7M103.1 100.5v6M103.1 102.4h4.4M103.1 105.6l4.9 .1"/>
<path d="M103.1 105.7h7.1M103.1 109.7h1M103.1 106.3h6.9M103.1 106.2h6.9M103.1 106h7M103.1 105.9h7M103.1 105.8h7.1M103.1 105.7h5M103.1 105.6h4.7M103.1 105.5l4.7 .1M103.1 105.5h4.5M103.1 105.4l4.4 .1"/>
<path d="M103.1 105.4h4.4M103.1 105.3h4.3M103.1 105.2h4.2M103.1 105.1h4.1M103.1 105.1h4M103.1 104.9l3.9 .1M103.1 104.9h3.9M103.1 104.8h3.9M103.1 104.7h3.8M103.1 104.6h3.8M103.1 104.6h3.7M103.1 104.5h3.7"/>
<path d="M103.1 104.4h3.7M103.1 104.3h3.7M103.1 104.2h3.6M103.1 104.1h3.6M103.1 104h3.6M103.1 103.9h3.6M103.1 103.8h3.6M103.1 103.7h3.6M103.1 103.6h3.6M103.1 103.5h3.7M103.1 103.4h3.7M103.1 103.3h3.7"/>
<path d="M103.1 103.1h3.9M103.1 102.8h4.1M103.1 102.1h10.6M103.1 102h10.6M103.1 101.9h10.6M103.1 101.8h10.6M103.1 101.7h10.6M103.1 101.6h10.6M103.1 101.5h10.6M103.1 101.4h10.6M103.1 101.3h10.6M103.1 101.2h10.6"/>
<path d="M103.1 101.1h10.6M103.1 101h10.6M103.1 100.9h10.6M103.1 100.8h10.6M103.1 100.7h10.6M103.1 100.6h10.6M103.1 100.5h8.2M103.1 100.5h8M103.1 100.4h7.9M103.1 100.4v.1M103.9 109.6l.3 .1M104 109.6h-.9l-.1 .1"/>
<path d="M104 106.5h-.9M104.1 106.4h-1M104.2 106.4l-.4 .2M104.8 119h.1M105.5 119l4.5 .1M105.7 119h4.3M106.2 119.1l.6 .2 .5 .5 .2 .6M106.2 106.4l.6 .2M106.3 109.7h3.8M106.3 106.4h3.7M106.3 119.1h3.7M106.4 109.6h3.7"/>
<path d="M106.4 106.5h3.6M106.4 119.2h3.6M106.5 109.6h3.6M106.6 106.5h3.4M106.6 119.3h3.4M106.6 106.6h3.4M106.7 109.5h3.4M106.7 119.3h3.3M106.7 103.6v.7M106.7 104.3l.1 .2M106.8 109.5h3.2M106.8 103.5l-3.7 .1"/>
<path d="M106.8 106.6l.5 .5M106.8 106.6h3.2M106.8 119.4h3.2M106.8 106.7h3.2M106.8 104.5v.1M106.8 103.4l-.1 .2M106.8 104.6l.1 .1M106.8 109.4h3.2M106.9 119.4h3.1M106.9 109.4h3.1M106.9 106.7h3.1M106.9 103.2l-3.8 .1"/>
<path d="M106.9 103.2l-.1 .2M106.9 104.7l.1 .3M106.9 119.5h3.1M106.9 103.2h-3.8M107 119.5h3M107 109.3h3M107 106.8h3M107 103.1h-3.9M107 103h-3.9M107 105l.5 .5M107 119.6h3M107 106.9h3"/>
<path d="M107.1 102.9l-4 .1M107.1 109.2h2.9M107.1 119.6l3 .1M107.1 107h3M107.1 102.9h-4M107.1 119.7h3M107.2 109.1h2.8M107.2 102.8h-4.1M107.2 119.7l2.9 .1M107.2 107.1h2.9M107.3 119.8h2.8M107.3 107.1a1.7 1.7 0 0 1-1.1 2.6"/>
<path d="M107.3 119.8h2.9M107.3 109h2.7M107.3 107.1h2.8M107.3 102.7h-4.2M107.3 119.9h2.9M107.3 108.9h2.7M107.3 107.2h2.9M107.3 119.9l2.9 .1M107.3 120h2.9M107.3 108.8h2.7M107.3 107.3h2.9M107.4 108.8h2.6"/>
<path d="M107.4 107.3h2.8M107.4 108.7h2.6M107.4 107.4h2.8M107.4 102.6h-4.3M107.4 107.4l2.9 .1M107.4 107.5h2.9M107.4 108.5h2.7M107.4 107.5l3 .1M107.5 107.6h2.9M107.5 108.5h2.6M107.5 107.6l3 .1M107.5 102.5h-4.4"/>
<path d="M107.5 107.7h3.1M107.5 102.4l-.6 .8M107.5 105.5l.3 .1M107.5 108.3h2.7M107.5 108.2h2.7M107.5 108.1h2.7M107.5 107.7l3.1 .1M107.7 102.4h-4.6M107.8 102.3l-.3 .1M107.8 105.6h.1M107.8 102.3l-4.7 .1M107.8 102.3h.1"/>
<path d="M107.9 105.6l.3 .1M108.1 102.2l-5 .1M108.2 102.2l-5.1 .1M109.8 102.2l.7 .2 .8-.1M109.9 105.7h.3M110 102.2h3.7M110 119h-12.2M110 106.4h-6.9M110 106.2v.6M110 108.7v.7M110 111.2v.7M110 106.8l.6 1"/>
<path d="M110 109.4l.6 .9M110 111.9l.6 .9M110 114.4l.6 1M110 117l.6 .9M110 116.3h-12.2M110 113.7h-12.2M110 111.2h-12.2M110 108.6l-2.6 .1M110 106.1h-6.9M110 108.6h-2.6M110 118.8h-12.2M110 116.2h-12.2"/>
<path d="M110 111.1l-12.2 .1M110 106l-6.9 .1M110.1 102.3h3.6M110.1 118.7h-12.3M110.1 116.2h-12.3M110.1 113.6l-12.3 .1M110.1 116.1h-12.3M110.1 113.6h-12.3M110.1 111l-12.3 .1M110.1 108.5h-2.6M110.1 105.9l-7 .1M110.1 118.6h-12.3"/>
<path d="M110.1 113.5l-12.3 .1M110.1 116h-12.3M110.1 113.5h-12.3M110.1 110.9l-12.3 .1M110.1 108.4h-2.6M110.1 105.8l-7 .1M110.1 105.6h.1M110.2 118.5h-12.4M110.2 116h-12.4M110.2 113.4l-12.4 .1M110.2 118.4l-12.4 .1M110.2 115.8l-12.4 .1"/>
<path d="M110.2 113.3h-12.4M110.2 118.4h-12.4M110.2 118.3l-12.4 .1M110.2 105.6h.1M110.2 113.2h-12.4M110.2 105.6l-.2 .1M110.2 118.3h-12.4M110.2 115.7l-12.4 .1M110.2 102.3h1M110.3 105.6l-.5 .1M110.3 105.6l-.3 .6M110.3 118.2l-12.5 .1"/>
<path d="M110.3 110.6h-12.5M110.3 108.1h-2.8M110.3 118.2h-12.5M110.3 102.4h.8M110.3 113.1h-12.5M110.3 115.6l-12.5 .1M110.3 108h-2.8M110.4 115.6h-12.6M110.4 118.1l-12.6 .1M110.4 113.1h-12.6M110.4 118.1h-12.6M110.4 107.9l-2.9 .1"/>
<path d="M110.4 115.5l-12.6 .1M110.4 113h-12.6M110.4 110.4l-8.5 .1M110.4 107.9h-2.9M110.5 118l-12.7 .1M110.5 115.5h-12.7M110.5 112.9l-12.7 .1M110.5 110.4h-8.5M110.5 107.8l-3 .1M110.5 118h-12.7M110.5 115.4l-12.7 .1M110.5 112.9h-12.7"/>
<path d="M110.5 107.8h-3M110.6 112.8l-.6 1v.6M110.6 115.4l-.6 .9v.7M110.6 117.9a1.63 1.63 0 0 0 0 2.6M110.6 107.8l-.6 .9M110.6 110.3l-.6 .9M110.6 117.9l-12.8 .1M110.6 115.4h-12.8M110.6 112.8l-12.8 .1M110.6 110.3h-8.3M111 100.4l.3 .1M113.3 102.3l.4 .1"/>
<path d="M113.4 100.5h.3M113.5 102.3h.2M113.5 100.5h.2M113.6 102.4h.1M113.6 100.4h.1M113.6 100.4l-.3 .1M113.6 100.4l.1 .1M113.7 102.2h-10.6M113.7 100.5v1.9M113.7 102.4h.1M133.2 115.6l10.7 .1M133.3 115.7h10.7"/>
<path d="M133.3 115.7l10.8 .1M133.3 115.8l16.6 .1M133.3 115.8h10.9M133.4 116h16.5M133.4 115.9h16.5M133.4 118.5h3.7M133.4 116.1h16.5M133.5 118.4h3.7M133.5 116.1h16.4M133.5 116.2v2.2M133.5 117.5h16.4M133.5 117.4h16.4"/>
<path d="M133.5 117.3h16.4M133.5 117.2h16.4M133.5 117.1h16.4M133.5 117h16.4M133.5 116.9h16.4M133.5 116.8h16.4M133.5 116.7h16.4M133.5 116.6h16.4M133.5 116.5h16.4M133.5 116.4h16.4M133.5 116.3h16.4M133.5 116.2h16.4"/>
<path d="M137.1 118.6h-3.7M137.2 118.4l-3.8 .1M137.2 118.4l-.1 .2h-3.7l.1-.2M137.2 118.3l-3.7 .1M137.3 118.3h-3.8M137.3 118.2l-3.8 .1M137.4 118.2h-3.9M137.4 118.1l-3.9 .1M137.5 118.1h-4M137.5 118l-4 .1M137.6 118h-4.1M137.6 117.9l-4.1 .1"/>
<path d="M137.7 117.9l-.5 .5M137.7 117.9h-4.2M137.8 117.8l-4.3 .1M138 117.8h-4.5M138.1 117.7h-4.6M138.2 117.6l-4.7 .1M138.3 117.6l-.6 .3M139 117.6l.7 .3M139.1 117.6h10.8M139.3 117.7h10.6M139.4 117.8h10.5M139.5 117.8h10.4"/>
<path d="M139.7 117.9l.5 .5 .3 .6M139.7 117.9h10.2M139.8 118h10.1M139.9 118.1h10M140 118.2h9.9M140.1 118.3h9.8M140.2 118.3h9.7M140.2 118.4h9.7M140.3 118.6h9.6M140.3 118.5h9.6M140.3 118.7h9.6M140.4 118.8h9.5"/>
<path d="M140.4 118.9h9.5M140.4 119h9.5M140.5 119.1h9.4M140.5 119v2.3M140.5 120h9.4M140.5 119.9h9.4M140.5 119.8h9.4M140.5 119.7h9.4M140.5 119.6h9.4M140.5 119.5h9.4M140.5 119.4h9.4M140.5 119.3h9.4"/>
<path d="M140.5 119.2h9.4M140.5 119h9.4M142.6 102.9h1.3M142.7 102.9h1.2M142.7 105h1.2M142.7 104.9h1.1M142.7 103h1.1M142.8 104.8h1M142.8 103.1h1M142.8 104.7h1M142.8 104.7h.9M142.8 103.2h.9"/>
<path d="M142.9 104.6h.8M142.9 103.2h.8M142.9 103.3h.8M142.9 104.5h.8M142.9 103.4h.8M142.9 104.4h.7M142.9 103.4h.7M143 104.4h.6M143 103.5h.6M143 104.3h.6M143 104.3l-.3 .7h1.1M143 103.6v.7"/>
<path d="M143 104.2h.6M143 104.1h.6M143 104h.6M143 103.9h.6M143 103.8h.6M143 103.7h.6M143 103.6h.6M143 102.7h1.1M143.6 103.6v.7M143.6 104.3l.2 .7M143.6 102.2h6.3M143.6 102.1h6.3"/>
<path d="M143.7 102h6.2M143.8 101.9h6.1M143.8 103l-.2 .6M143.9 101.8h6M144 102.8h-1.3M144 101.7h5.9M144 102.8h-1.2M144.1 102.7h-1.2M144.1 101.6h5.8M144.2 102.6h-1.1M144.2 101.5h5.7M144.3 102.6h-1.1"/>
<path d="M144.3 101.5h5.6M144.3 102.5h-1.1M144.3 101.4h5.6M144.3 102.4l-.5 .6M144.4 115.9l-.7-.3h-10.5l.3 .6M144.4 102.4l-1.1 .1M144.4 101.4h5.5M144.4 101.3h5.5M144.5 101.3h5.4M144.5 102.4h-1.2M144.5 101.2h5.4M144.6 101.2h5.3"/>
<path d="M144.6 102.3l-1.2 .1M144.6 101.1h5.3M144.7 101h5.2M144.8 102.3h-1.4M144.8 100.9h5.1M144.9 102.2l-1.4 .1M144.9 100.8h5M145 102.2l-.7 .2M145 100.7h4.9M145.1 100.7h4.8M145.1 100.6h4.8M145.2 100.6h4.7"/>
<path d="M145.2 100.5h2.3M145.3 100.5h2M145.3 100.4h1.9M145.4 100.4l-2.4 2.3-.4 .1 .4 .8M146.5 115.8h3.4M146.6 115.8h3.3M146.7 102.2l.5 .2 .3-.1M146.7 115.7h3.2M146.8 102.2h3.1M146.8 115.7h3.1M146.9 102.3h3M147 115.6h2.9"/>
<path d="M147 115.6l-.7 .3M147 102.3h.4M147.1 115.5h2.8M147.2 102.4h.1M147.2 100.4l.3 .1M147.2 115.4h2.7M147.3 115.3h2.6M147.4 115.2h2.5M147.4 115.1h2.5M147.5 115.1h2.4M147.5 115h2.4M147.6 115h2.3"/>
<path d="M147.6 114.9h2.3M147.6 113.3h2.3M147.6 114.8h2.3M147.6 113.4h2.3M147.6 114.7h2.3M147.6 113.5h2.3M147.7 114.7h2.2M147.7 113.5h2.2M147.7 114.6h2.2M147.7 113.6h2.2M147.7 114.5h2.2M147.7 113.7h2.2"/>
<path d="M147.8 114.4h2.1M147.8 114.3h2.1M147.8 114.2h2.1M147.8 114.1h2.1M147.8 114h2.1M147.8 113.9h2.1M147.8 113.8h2.1M149.5 102.3l.4 .1M149.6 100.5h.3M149.6 113.2h.3M149.7 102.3h.2M149.7 100.5h.2"/>
<path d="M149.8 102.4h.1M149.8 113.1h.1M149.8 100.4h.1M149.8 100.4l-.3 .1M149.9 100.4v2M149.9 113.1v8.6M149.9 102.2h-6.4M149.9 117.6h-16.4M149.9 113.2h-2.3a1.75 1.75 0 0 1-.6 2.4M149.9 113.1l-.4 .1M149.9 102.4h.1M152.9 103v18.7"/>
<path d="M152.9 105h1.3M152.9 119.1h21.1M152.9 119h21.1M152.9 117.6h20.8M152.9 118.6h21.1M152.9 115.6h18.7M152.9 115.8h18.8M152.9 113.2h5.4M152.9 113.1h2M152.9 113.3h18.7M152.9 109.6h1M152.9 109.7h1.1"/>
<path d="M152.9 106.4h.9M152.9 106.5h.9M152.9 120h21.1M152.9 119.9h21.1M152.9 119.8h21.1M152.9 119.7h21.1M152.9 119.6h21.1M152.9 119.5h21.1M152.9 119.4h21.1M152.9 119.3h21.1M152.9 119.2h21.1M152.9 118.9h21.1"/>
<path d="M152.9 118.8h21.1M152.9 118.7h21.1M152.9 118.5h21.1M152.9 118.4h21.1M152.9 118.3h21.1M152.9 118.2h21.1M152.9 118.1h21.1M152.9 118h21.1M152.9 117.9h21.1M152.9 117.8l21 .1M152.9 117.8h21M152.9 117.7h20.9"/>
<path d="M152.9 117.6l20.9 .1M152.9 117.5l20.8 .1M152.9 117.5h20.7M152.9 117.4l20.6 .1M152.9 117.4h20.6M152.9 117.3l20.6 .1M152.9 117.3h20.5M152.9 117.2h20.4M152.9 117.1l20.3 .1M152.9 117.1h20.3M152.9 117l20.2 .1M152.9 117h20.2"/>
<path d="M152.9 116.9h20.1M152.9 116.8h20M152.9 116.8h19.9M152.9 116.7h19.8M152.9 116.6l19.7 .1M152.9 116.6h19.5M152.9 116.5h19.4M152.9 116.5h19.3M152.9 116.4l19.3 .1M152.9 116.4h19.2M152.9 116.3l19.2 .1M152.9 116.3h19.1"/>
<path d="M152.9 116.2h19.1M152.9 116.2h19M152.9 116.1h19M152.9 116.1h18.9M152.9 116h18.9M152.9 116h18.8M152.9 115.9h18.8M152.9 115.7l18.8 .1M152.9 115.7h18.7M152.9 115.6l18.7 .1M152.9 115.5h18.7M152.9 115.4h18.6"/>
<path d="M152.9 115.3h18.6M152.9 115.2h18.6M152.9 115.1h18.6M152.9 115h18.6M152.9 114.9h18.6M152.9 114.8h18.6M152.9 114.7h18.6M152.9 114.6h18.6M152.9 114.5h18.6M152.9 114.4h18.6M152.9 114.3h18.6M152.9 114.2h18.6"/>
<path d="M152.9 114.1h18.6M152.9 114h18.6M152.9 113.9h18.6M152.9 113.8h18.6M152.9 113.7h18.6M152.9 113.6h18.6M152.9 113.5h18.6M152.9 113.4h18.6M152.9 113.3h5.5M152.9 113.2h2.1M152.9 113.1h1.8M152.9 113h1.7"/>
<path d="M152.9 112.9l1.6 .1M152.9 112.9h1.6M152.9 112.8l1.5 .1M152.9 112.8h1.5M152.9 112.7l1.4 .1M152.9 112.7h1.4M152.9 112.6h1.3M152.9 112.5h1.2M152.9 112.4h1.1M152.9 112.3h1.1M152.9 112.2l1.1 .1M152.9 112.2h1"/>
<path d="M152.9 112.1l1 .1M152.9 112.1h1M152.9 112l1 .1M152.9 112h1M152.9 111.9l.9 .1M152.9 111.9h.9M152.9 111.8h.9M152.9 111.7h.9M152.9 111.6h.9M152.9 111.5h.9M152.9 111.4h.9M152.9 111.3h.9"/>
<path d="M152.9 111.2h.9M152.9 111.1h1M152.9 110.4h1.3M152.9 110.2l1.4 .1M152.9 110.2h1.4M152.9 110.1l1.3 .1M152.9 110.1h1.3M152.9 110h1.2M152.9 109.9h1.2M152.9 109.9h1.1M152.9 109.8h1.1M152.9 109.7l1.1 .1"/>
<path d="M152.9 109.6l1 .1M152.9 109.5l1 .1M152.9 109.5h1M152.9 109.4l1 .1M152.9 109.4h.9M152.9 109.3h.9M152.9 109.2h.9M152.9 109.1h.9M152.9 109h.9M152.9 108.9h.9M152.9 108.8h.9M152.9 108.7h.9"/>
<path d="M152.9 108.6h.9M152.9 108.5h1M152.9 107.9h1.3M152.9 107.7h1.4M152.9 107.6l1.4 .1M152.9 107.6h1.3M152.9 107.5l1.3 .1M152.9 107.5h1.2M152.9 107.4l1.2 .1M152.9 107.4h1.2M152.9 107.3h1.1M152.9 107.2h1.1"/>
<path d="M152.9 107.1h1M152.9 107h1M152.9 106.9h1M152.9 106.8l.9 .1M152.9 106.8h.9M152.9 106.7h.9M152.9 106.6h.9M152.9 106.3h.9M152.9 106.2h.9M152.9 106h1M152.9 105.2h1.5M152.9 105.2h1.4"/>
<path d="M152.9 105.1h1.4M152.9 105.1h1.3M152.9 104.9l1.2 .1M152.9 104.9h1.2M152.9 104.8h1.2M152.9 104.8h1.1M152.9 104.7h1.1M152.9 104.6h1.1M152.9 104.6h1M152.9 104.5h1M152.9 104.4h1M152.9 104.4h.9"/>
<path d="M152.9 104.3h.9M152.9 104.2h.9M152.9 104.1h.9M152.9 104h.9M152.9 103.9h.9M152.9 103.8h.9M152.9 103.7h.9M152.9 103.6h.9M152.9 103.1h1.1M152.9 103h1.2M153 102.9l-.1 .1M153.8 103.6v.7"/>
<path d="M153.8 106.2v.6M153.8 108.7v.7M153.8 111.2v.7M153.8 104.3l.3 .6M153.8 106.8l.3 .6M153.8 109.4l.3 .6M153.8 111.9l.3 .6M153.8 106.1h-.9M153.8 103.5l-.9 .1M153.9 108.6h-1M153.9 111.1h-1M153.9 106l-1 .1"/>
<path d="M153.9 103.5h-1M153.9 103.4l-1 .1M153.9 111h-1M153.9 108.5h-1M153.9 105.9l-1 .1M153.9 103.4h-1M153.9 108.4l-1 .1M153.9 105.9h-1M153.9 103.3l-1 .1M153.9 110.9h-1M153.9 108.4h-1M153.9 105.8l-1 .1"/>
<path d="M153.9 103.3h-1M154 110.9h-1.1M154 108.3l-1.1 .1M154 105.8h-1.1M154 103.2l-1.1 .1M154 105.7h-1.1M154 110.8h-1.1M154 108.3h-1.1M154 103.2h-1.1M154 108.2h-1.1M154 103.1l-1.1 .1M154 105.6l-1.1 .1"/>
<path d="M154 110.7h-1.1M154.1 110.7h-1.2M154.1 108.1h-1.2M154.1 105.6h-1.2M154.1 103l-1.2 .1M154.1 103l-.3 .6M154.1 104.9l.3 .3M154.1 105.5l-.3 .7M154.1 107.4l.3 .4M154.1 108.1l-.3 .6M154.1 110l.3 .3M154.1 110.6l-.3 .6"/>
<path d="M154.1 112.5l.4 .5 .7 .2M154.1 110.6h-1.2M154.1 105.5l-1.2 .1M154.1 103h-1.2M154.1 108h-1.2M154.1 105.5h-1.2M154.2 110.5h-1.3M154.2 107.9l-1.3 .1M154.2 105.4l-1.3 .1M154.2 105.4h-1.3M154.3 110.4h-1.4M154.3 107.8l-1.4 .1"/>
<path d="M154.3 105.3h-1.4M154.3 110.3l-1.4 .1M154.3 107.8h-1.4M154.4 105.2l-.3 .3M154.4 107.8l-.3 .3M154.4 110.3l-.3 .3M154.4 110.3h-1.5M154.4 107.8h-1.5M157.3 113.2h.8M157.4 113.1h.6M157.5 113.1l-.4 .1M157.9 113.1l.6 .2"/>
<path d="M160.9 113.3h10.7M161.2 113.1h10.5l-.2 .3M161.4 113.1l-.7 .2M164.2 100h11.7M164.3 100.1h11.6M164.4 100.2h11.5M164.5 100.3h11.4M164.6 100.4h11.3M164.7 102.3h11.2M164.7 100.5h11.2M164.7 102.2h11.2M164.7 100.6h11.2"/>
<path d="M164.7 102.2l-.1 .2h11.3M164.7 100.6l.1 .2M164.8 102.1h11.1M164.8 100.7h11.1M164.8 102.1l-.1 .1M164.8 102v.1M164.8 100.8l.1 .2M164.8 102h11.1M164.8 100.8h11.1M164.8 101.9h11.1M164.8 100.9h11.1M164.9 101.8h11"/>
<path d="M164.9 101h11M164.9 101.8l-.1 .2M164.9 101v.8M164.9 101.7h11M164.9 101.6h11M164.9 101.5h11M164.9 101.4h11M164.9 101.3h11M164.9 101.2h11M164.9 101.1h11M171.5 113.4v2M171.5 115.4l.3 .7 .5 .5"/>
<path d="M171.6 113.2h-10.6M171.6 113.2h-10.5M172.3 116.6l.6 .2M172.9 116.8l1.1 1.1M174 117.9v8.8h-46.2M175.9 102.4h-.1M179.2 110.3l1.4 1.4 .2 .5M179.2 110.3h2.5M179.3 110.3h2.4M179.3 110.4h2.4M179.3 110.2h2.4M179.4 110.4h2.3"/>
<path d="M179.4 110.2h2.3M179.4 110.5h2.3M179.4 110.1h2.3M179.5 110.6h2.2M179.5 110h2.2M179.6 110.7h2.1M179.6 109.9h2.1M179.7 110.8h2M179.7 109.8h2M179.8 109.7h1.9M179.8 110.9h1.9M179.9 110.9h1.8"/>
<path d="M179.9 109.7h1.8M179.9 109.6h1.8M179.9 111h1.8M180 111h1.7M180 109.6h1.7M180 111.1h1.7M180 109.5h1.7M180.1 111.1h1.6M180.1 109.5h1.6M180.1 111.2h1.6M180.1 109.4h1.6M180.2 111.2h1.5"/>
<path d="M180.2 109.4h1.5M180.2 111.3h1.5M180.2 109.3h1.5M180.3 111.3h1.4M180.3 109.3h1.4M180.3 111.4h1.4M180.3 109.2h1.4M180.4 109.2h1.3M180.4 111.5h1.3M180.4 109.1h1.3M180.5 109.1h1.2M180.5 111.6h1.2"/>
<path d="M180.6 111.6h1.1M180.6 109h1.1M180.6 108.9h1.1M180.6 111.7h1.1M180.6 108.8h1.1M180.7 111.8h1M180.7 108.8h1M180.7 108.7h1M180.7 111.9h1M180.7 108.6h1M180.7 112h1M180.8 112h.9"/>
<path d="M180.8 108.5h.9M180.8 112.1h.9M180.8 108.4h.9M180.8 102.4h.9M180.8 100.4h.9M180.8 100.5h.9M180.8 102.3h.9M180.8 102.2h.9M180.8 105h.9M180.8 119.1h.9M180.8 119h.9M180.8 117.6h.9"/>
<path d="M180.8 118.6h.9M180.8 115.6h.9M180.8 115.8h.9M180.8 113.2h.9M180.8 102.9h.9M180.8 113.1h.9M180.8 113.3h.9M180.8 112.2v17.4M180.8 108.4l-.2 .5-1.4 1.4M180.8 106.4h.9M180.8 106.5h.9M180.8 105.6h.9"/>
<path d="M180.8 105.7h.9M180.8 120h.9M180.8 119.9h.9M180.8 119.8h.9M180.8 119.7h.9M180.8 119.6h.9M180.8 119.5h.9M180.8 119.4h.9M180.8 119.3h.9M180.8 119.2h.9M180.8 118.9h.9M180.8 118.8h.9"/>
<path d="M180.8 118.7h.9M180.8 118.5h.9M180.8 118.4h.9M180.8 118.3h.9M180.8 118.2h.9M180.8 118.1h.9M180.8 118h.9M180.8 117.9h.9M180.8 117.8h.9M180.8 117.7h.9M180.8 117.5h.9M180.8 117.4h.9"/>
<path d="M180.8 117.3h.9M180.8 117.2h.9M180.8 117.1h.9M180.8 117h.9M180.8 116.9h.9M180.8 116.8h.9M180.8 116.7h.9M180.8 116.6h.9M180.8 116.5h.9M180.8 116.4h.9M180.8 116.3h.9M180.8 116.2h.9"/>
<path d="M180.8 116.1h.9M180.8 116h.9M180.8 115.9h.9M180.8 115.7h.9M180.8 115.5h.9M180.8 115.4h.9M180.8 115.3h.9M180.8 115.2h.9M180.8 115.1h.9M180.8 115h.9M180.8 114.9h.9M180.8 114.8h.9"/>
<path d="M180.8 114.7h.9M180.8 114.6h.9M180.8 114.5h.9M180.8 114.4h.9M180.8 114.3h.9M180.8 114.2h.9M180.8 114.1h.9M180.8 114h.9M180.8 113.9h.9M180.8 113.8h.9M180.8 113.7h.9M180.8 113.6h.9"/>
<path d="M180.8 113.5h.9M180.8 113.4h.9M180.8 113h.9M180.8 112.9h.9M180.8 112.8h.9M180.8 112.7h.9M180.8 112.6h.9M180.8 112.5h.9M180.8 112.4h.9M180.8 112.3h.9M180.8 112.2h.9M180.8 108.3h.9"/>
<path d="M180.8 108.2h.9M180.8 108.1h.9M180.8 108h.9M180.8 107.9h.9M180.8 107.8h.9M180.8 107.7h.9M180.8 107.6h.9M180.8 107.5h.9M180.8 107.4h.9M180.8 107.3h.9M180.8 107.2h.9M180.8 107.1h.9"/>
<path d="M180.8 107h.9M180.8 106.9h.9M180.8 106.8h.9M180.8 106.7h.9M180.8 106.6h.9M180.8 106.3h.9M180.8 106.2h.9M180.8 106.1h.9M180.8 106h.9M180.8 105.9h.9M180.8 105.8h.9M180.8 105.5h.9"/>
<path d="M180.8 105.4h.9M180.8 105.3h.9M180.8 105.2h.9M180.8 105.1h.9M180.8 104.9h.9M180.8 104.8h.9M180.8 104.7h.9M180.8 104.6h.9M180.8 104.5h.9M180.8 104.4h.9M180.8 104.3h.9M180.8 104.2h.9"/>
<path d="M180.8 104.1h.9M180.8 104h.9M180.8 103.9h.9M180.8 103.8h.9M180.8 103.7h.9M180.8 103.6h.9M180.8 103.5h.9M180.8 103.4h.9M180.8 103.3h.9M180.8 103.2h.9M180.8 103.1h.9M180.8 103h.9"/>
<path d="M180.8 102.8h.9M180.8 102.7h.9M180.8 102.6h.9M180.8 102.5h.9M180.8 102.1h.9M180.8 102h.9M180.8 101.9h.9M180.8 101.8h.9M180.8 101.7h.9M180.8 101.6h.9M180.8 101.5h.9M180.8 101.4h.9"/>
<path d="M180.8 101.3h.9M180.8 101.2h.9M180.8 101.1h.9M180.8 101h.9M180.8 100.9h.9M180.8 100.8h.9M180.8 100.7h.9M180.8 100.6h.9M180.8 100.3h.9M180.8 100.2h.9M180.8 100.1h.9M180.8 100h.9"/>
<path d="M187.7 105h1.6M187.7 119.1h15.3M187.7 119h15.3M187.7 110.5h15.3M187.7 108.6h1M187.7 117.6h15.3M187.7 118.6h15.3M187.7 115.6h15.3M187.7 115.8h15.3M187.7 113.2h15.3M187.7 113.1h15.3M187.7 113.3h15.3"/>
<path d="M187.7 109.6h1.2M187.7 109.7h1.2M187.7 106.4h1.6M187.7 106.5h1.6M187.7 105.6h1.6M187.7 105.7h1.6M187.7 120h15.3M187.7 119.9h15.3M187.7 119.8h15.3M187.7 119.7h15.3M187.7 119.6h15.3M187.7 119.5h15.3"/>
<path d="M187.7 119.4h15.3M187.7 119.3h15.3M187.7 119.2h15.3M187.7 118.9h15.3M187.7 118.8h15.3M187.7 118.7h15.3M187.7 118.5h15.3M187.7 118.4h15.3M187.7 118.3h15.3M187.7 118.2h15.3M187.7 118.1h15.3M187.7 118h15.3"/>
<path d="M187.7 117.9h15.3M187.7 117.8h15.3M187.7 117.7h15.3M187.7 117.5h15.3M187.7 117.4h15.3M187.7 117.3h15.3M187.7 117.2h15.3M187.7 117.1h15.3M187.7 117h15.3M187.7 116.9h15.3M187.7 116.8h15.3M187.7 116.7h15.3"/>
<path d="M187.7 116.6h15.3M187.7 116.5h15.3M187.7 116.4h15.3M187.7 116.3h15.3M187.7 116.2h15.3M187.7 116.1h15.3M187.7 116h15.3M187.7 115.9h15.3M187.7 115.7h15.3M187.7 115.5h15.3M187.7 115.4h15.3M187.7 115.3h15.3"/>
<path d="M187.7 115.2h15.3M187.7 115.1h15.3M187.7 115h15.3M187.7 114.9h15.3M187.7 114.8h15.3M187.7 114.7h15.3M187.7 114.6h15.3M187.7 114.5h15.3M187.7 114.4h15.3M187.7 114.3h15.3M187.7 114.2h15.3M187.7 114.1h15.3"/>
<path d="M187.7 114h15.3M187.7 113.9h15.3M187.7 113.8h15.3M187.7 113.7h15.3M187.7 113.6h15.3M187.7 113.5h15.3M187.7 113.4h15.3M187.7 113h15.3M187.7 112.9h15.3M187.7 112.8h15.3M187.7 112.7h15.3M187.7 112.6h15.3"/>
<path d="M187.7 112.5h15.3M187.7 112.4h15.3M187.7 112.3h15.3M187.7 112.2h15.3M187.7 112.1h15.3M187.7 112h15.3M187.7 111.9h15.3M187.7 111.8h15.3M187.7 111.7h15.3M187.7 111.6h15.3M187.7 111.5h15.3M187.7 111.4h15.3"/>
<path d="M187.7 111.3h15.3M187.7 111.2h15.3M187.7 111.1h15.3M187.7 111h15.3M187.7 110.9h15.3M187.7 110.8h15.3M187.7 110.7h15.3M187.7 110.6h15.3M187.7 110.4l2.3 .1M187.7 110.4h2.2M187.7 110.3l2.1 .1M187.7 110.3h2"/>
<path d="M187.7 110.2l1.8 .1M187.7 110.2h1.7M187.7 110.1l1.7 .1M187.7 110.1h1.6M187.7 110h1.6M187.7 110h1.5M187.7 109.9h1.4M187.7 109.8h1.3M187.7 109.7l1.3 .1M187.7 109.6l1.2 .1M187.7 109.5l1.2 .1M187.7 109.5h1.1"/>
<path d="M187.7 109.4l1.1 .1M187.7 109.4h1.1M187.7 109.3l1.1 .1M187.7 109.3h1.1M187.7 109.2l1 .1M187.7 109.2h1M187.7 109.1l1 .1M187.7 109.1h1M187.7 109h1M187.7 108.9h1M187.7 108.8h1M187.7 108.7h1"/>
<path d="M187.7 108.5h1M187.7 108.4h1M187.7 108.3h1M187.7 108.2h1M187.7 108.1h1M187.7 108h1.1M187.7 107.9h1.1M187.7 107.3h1.6M187.7 107.2h1.6M187.7 107.1h1.6M187.7 107h1.6M187.7 106.9h1.6"/>
<path d="M187.7 106.8h1.6M187.7 106.7h1.6M187.7 106.6h1.6M187.7 106.3h1.6M187.7 106.2h1.6M187.7 106.1h1.6M187.7 106h1.6M187.7 105.9h1.6M187.7 105.8h1.6M187.7 105.5h1.6M187.7 105.4h1.6M187.7 105.3h1.6"/>
<path d="M187.7 105.2h1.6M187.7 105.1h1.6M187.7 104.9h1.6M187.7 104.8h1.6M187.7 104.7h1.6M187.7 104.6h1.6M187.7 104.5h1.5M187.7 104.5h1.4M187.7 104.4h1.3M187.7 104.4h1.1M187.7 104.3h1M187.7 104.2l.9 .1"/>
<path d="M187.7 104.2h.8M187.7 104.1l.8 .1M187.7 104.1h.7M187.7 104h.6M187.7 103.9h.5M187.7 103.8h.5M187.7 103.8h.4M187.7 103.7h.3M187.7 103.6h.2M187.7 103.5l.2 .1M187.7 103.5h.2M187.7 103.4l.2 .1"/>
<path d="M187.7 103.4h.1M187.7 103.3l.1 .1M187.7 103.3h.1M187.7 103.2l.1 .1M187.9 103.7l-.2-.5v29.7M187.9 103.7l.7 .6 .7 .3M188.7 108.4v.7M188.7 109.1l.2 .6M188.8 108.1h-1.1M188.8 107.9l-1.1 .1M188.9 107.8l-1.2 .1M188.9 107.8h-1.2"/>
<path d="M188.9 107.7l-1.2 .1M188.9 107.7l-.2 .7M188.9 109.7l.5 .5M188.9 107.7h-1.2M189 107.6l-1.3 .1M189 107.6h-1.3M189.1 107.5l-1.4 .1M189.1 107.5h-1.4M189.2 107.4l-1.5 .1M189.3 107.4h-1.6M189.3 104.6v2.7M189.3 107.3l-.4 .4"/>
<path d="M189.3 107.3l-1.6 .1M189.4 110.2l.7 .3M192.1 110.5h10.9M192.2 110.4h10.8M192.3 110.4h10.7M192.4 110.3h10.6M192.6 110.3h10.4M192.7 110.2l-.7 .3M192.7 110.2h10.3M192.8 110.2h10.2M192.8 110.1h10.2M192.8 105h1.6"/>
<path d="M192.8 107.3l.4 .4M192.8 105v2.3M192.8 106.4h1M192.8 106.5h.9M192.8 107.3l1 .1M192.8 107.3h1M192.8 107.2l1 .1M192.8 107.2h.9M192.8 107.1h.9M192.8 107h.9M192.8 106.9h.9M192.8 106.8h.9"/>
<path d="M192.8 106.7h.9M192.8 106.6h.9M192.8 106.4h.9M192.8 106.3h1M192.8 106.2h1M192.8 106.1h1.1M192.8 106h1.1M192.8 105.4h1.6M192.8 105.3h1.6M192.8 105.2h1.6M192.8 105.1h1.6M192.9 110h10.1"/>
<path d="M192.9 107.4h.9M192.9 105h1.4M192.9 107.4l1 .1M192.9 104.9h1.4M193 109.9h10M193 107.5h.9M193 104.9h1.2M193 107.5l.9 .1M193 104.8h1.2M193.1 109.8h9.9M193.1 107.6h.8M193.1 104.8h1"/>
<path d="M193.1 107.6l.9 .1M193.1 104.7h1M193.2 109.7h9.8M193.2 107.7h.8M193.2 104.6h.8M193.2 109.7l-.5 .5M193.2 107.7l.3 .7M193.2 107.7l.8 .1M193.2 109.6h9.8M193.2 107.8h.8M193.3 109.6h9.7M193.3 107.8l.8 .1"/>
<path d="M193.3 104.6h.7M193.3 107.9h.8M193.3 109.5h9.7M193.3 107.9l.9 .1M193.3 104.5h.6M193.3 108h.9M193.3 109.4h9.7M193.3 108.1h1M193.4 104.5h.4M193.4 109.3h9.6M193.4 108.2h1M193.4 108.1h.9"/>
<path d="M193.4 109.2h9.6M193.4 104.4h.4M193.4 108.3h1.1M193.4 109.1h9.6M193.5 109.1l-.3 .6M193.5 108.4v.7M193.5 108.6h9.5M193.5 109.1h9.5M193.5 109h9.5M193.5 108.9h9.5M193.5 108.8h9.5M193.5 108.7h9.5"/>
<path d="M193.5 108.5l1.6 .1M193.5 108.5h1.5M193.5 108.4l1.4 .1M193.5 108.4h1.3M193.5 108.3l1.1 .1M193.5 104.4h.2M193.5 104.3l-.7 .7M193.5 104.3h.2M193.7 104.3l.7 .7M193.7 106.4v.8M193.7 107.2l.3 .6M193.9 106.2h-1.1"/>
<path d="M193.9 106l-1.1 .1M194 105.9l-1.2 .1M194 105.9h-1.2M194 105.8l-.3 .6M194 107.8l.5 .5M194 105.8l-1.2 .1M194 105.8h-1.2M194.1 105.7l-1.3 .1M194.1 105.7h-1.3M194.2 105.6l-1.4 .1M194.2 105.6h-1.4M194.3 105.5l-1.5 .1"/>
<path d="M194.3 105.5h-1.5M194.4 105v.4M194.4 105.4l-.4 .4M194.4 105.4l-1.6 .1M194.5 108.3l.7 .3M197.2 108.6h5.8M197.3 108.5h5.7M197.4 108.5h5.6M197.5 108.4h5.5M197.7 108.4h5.3M197.8 108.3l-.7 .3M197.8 108.3h5.2"/>
<path d="M197.8 108.2h5.2M197.9 108.2h5.1M197.9 105h5.1M197.9 105.4l.4 .4M197.9 104.6v.8M197.9 100.1l.7 .4M197.9 105.4h5.1M197.9 105.3h5.1M197.9 105.2h5.1M197.9 105.1h5.1M197.9 104.9h5.1M197.9 104.8h5.1"/>
<path d="M197.9 104.7h5.1M197.9 104.6h5.1M197.9 100.1h5.1M197.9 100.2h5.1M198 108.1h5M198 105.5h5M198 104.5h5M198 100.1h5M198.1 108h4.9M198.1 105.6h4.9M198.1 100.2h4.9M198.1 104.5h4.9"/>
<path d="M198.1 100h4.9M198.2 107.9h4.8M198.2 105.7h4.8M198.2 100.3h4.8M198.3 107.8h4.7M198.3 105.8h4.7M198.3 104.4h4.7M198.3 107.8l-.5 .5M198.3 105.8l.2 .6M198.3 107.7h4.7M198.3 105.9h4.7M198.3 100.3h4.7"/>
<path d="M198.4 106h4.6M198.4 107.6h4.6M198.4 106.1h4.6M198.4 107.5h4.6M198.4 106.2h4.6M198.4 104.4h4.6M198.4 107.4h4.6M198.5 100.4h4.5M198.5 107.4h4.5M198.5 106.3h4.5M198.5 106.2h4.5M198.5 106.4h4.5"/>
<path d="M198.5 107.3h4.5M198.5 104.3h4.5M198.5 107.2l-.2 .6M198.5 106.4v.8M198.5 106.5h4.5M198.5 107.2h4.5M198.5 107.1h4.5M198.5 107h4.5M198.5 106.9h4.5M198.5 106.8h4.5M198.5 106.7h4.5M198.5 106.6h4.5"/>
<path d="M198.6 100.4h4.4M198.6 100.5l.7 .6M198.6 104.3h4.4M198.7 104.2h4.3M198.7 100.5h4.3M198.8 100.6h4.2M198.8 104.1h4.2M198.9 104h4.1M198.9 100.7h4.1M198.9 100.8h4.1M199 103.9h4M199 100.8h4"/>
<path d="M199.1 103.8h3.9M199.1 100.9h3.9M199.1 101h3.9M199.2 103.7h3.8M199.2 101h3.8M199.3 103.7l-.7 .6-.7 .3M199.3 101.1l.3 .8M199.3 103.6h3.7M199.3 101.1h3.7M199.3 103.5h3.7M199.3 101.2h3.7M199.3 101.3h3.7"/>
<path d="M199.4 103.4h3.6M199.4 101.3h3.6M199.4 101.4h3.6M199.4 103.3h3.6M199.4 101.5h3.6M199.5 103.2h3.5M199.5 101.5h3.5M199.5 103.1h3.5M199.5 101.6h3.5M199.5 103h3.5M199.5 101.7h3.5M199.6 102.9h3.4"/>
<path d="M199.6 101.8h3.4M199.6 101.9h3.4M199.6 102.8h3.4M199.6 102.4h3.4M199.6 102.3h3.4M199.6 102.2h3.4M199.6 102.8l-.3 .9M199.6 101.9v.9M199.6 102.7h3.4M199.6 102.6h3.4M199.6 102.5h3.4M199.6 102.1h3.4"/>
<path d="M199.6 102h3.4M97.8 134.8l2.6 2.6M97.8 137.6h6l8.8 8.8 .7 .3M97.8 139.1h7.5M97.8 136.6h1.8M97.8 138.8h7.2M97.8 140h8.4M97.8 139.9l8.4 .1M97.8 139.9h8.3M97.8 139.8h8.2M97.8 139.7h8.1M97.8 139.6h8"/>
<path d="M97.8 139.5h7.9M97.8 139.4l7.9 .1M97.8 139.4h7.8M97.8 139.3l7.8 .1M97.8 139.3h7.7M97.8 139.2l7.7 .1M97.8 139.2h7.6M97.8 139h7.4M97.8 138.9h7.3M97.8 138.7l7.2 .1M97.8 138.7h7.1M97.8 138.6l7.1 .1"/>
<path d="M97.8 138.6h7M97.8 138.5l7 .1M97.8 138.5h6.9M97.8 138.4l6.9 .1M97.8 138.4h6.8M97.8 138.3l6.8 .1M97.8 138.3h6.7M97.8 138.2l6.7 .1M97.8 138.2h6.6M97.8 138.1l6.6 .1M97.8 138.1h6.5M97.8 138h6.4"/>
<path d="M97.8 137.9h6.3M97.8 137.8h6.2M97.8 137.7h6.1M97.8 137.6l6.1 .1M97.8 137.5l3.1 .1M97.8 137.5h3M97.8 137.4l2.8 .1M97.8 137.4h2.7M97.8 137.3l2.6 .1M97.8 137.3h2.5M97.8 137.2h2.5M97.8 137.2h2.4"/>
<path d="M97.8 137.1h2.4M97.8 137.1h2.3M97.8 137h2.3M97.8 136.9l2.2 .1M97.8 136.9h2.1M97.8 136.8l2.1 .1M97.8 136.8h2M97.8 136.7l2 .1M97.8 136.7h1.9M97.8 136.6l1.9 .1M97.8 136.5h1.8M97.8 136.5h1.7"/>
<path d="M97.8 136.4h1.7M97.8 136.4h1.6M97.8 136.3h1.6M97.8 136.2l1.5 .1M97.8 136.2h1.5M97.8 136.1l1.4 .1M97.8 136.1h1.3M97.8 136l1.3 .1M97.8 136h1.2M97.8 135.9l1.2 .1M97.8 135.9h1.1M97.8 135.8l1.1 .1"/>
<path d="M97.8 135.8h1M97.8 135.7l1 .1M97.8 135.7h.9M97.8 135.6l.9 .1M97.8 135.6h.8M97.8 135.5l.8 .1M97.8 135.5h.7M97.8 135.4h.7M97.8 135.4h.6M97.8 135.3h.6M97.8 135.3h.5M97.8 135.2h.5"/>
<path d="M97.8 135.1l.4 .1M97.8 135.1h.3M97.8 135l.3 .1M97.8 135h.2M97.8 134.9l.2 .1M97.8 134.9h.1M97.8 134.8l.1 .1M97.8 134.8h.1M97.8 120.4h.3M97.8 120.1h.6M97.9 120.7h-.1M97.9 120.6h-.1"/>
<path d="M98 120.5l-.2 .1M98 120.5l-.2 .2v-69.7h105.2v97.9h-105.2v-14.1M98 120.5h-.2M98.1 120.5h-.3M98.2 120.4h-.4M98.2 120.3h-.4M98.3 120.2l-.5 .1M98.3 120.2h-.5M98.4 120.1l-.6 .1M98.5 120l-.7 .1M100.4 137.4l.6 .2M103.3 125.3h7.1"/>
<path d="M103.3 125.4h7.2M103.3 125.9h9l-.2 .6M103.3 130.9h28.2M103.3 125.8h7.7M103.3 126.1h8.9M103.3 130.9h9.9M103.3 130.8h9.7M103.3 130.7l9.6 .1M103.3 130.7h9.5M103.3 130.6l9.4 .1M103.3 130.6h9.3M103.3 130.5l9.2 .1"/>
<path d="M103.3 130.5h9.2M103.3 130.4l9.1 .1M103.3 130.4h9.1M103.3 130.3h9M103.3 130.3h8.9M103.3 130.2h8.9M103.3 130.2h8.8M103.3 130.1h8.8M103.3 130l8.8 .1M103.3 130h8.8M103.3 129.9l8.7 .1M103.3 129.9h8.7"/>
<path d="M103.3 129.8l8.7 .1M103.3 129.8h8.7M103.3 129.7l8.7 .1M103.3 129.7h8.6M103.3 129.6l8.6 .1M103.3 129.6h8.6M103.3 129.5l8.6 .1M103.3 129.5h8.5M103.3 129.4h8.5M103.3 129.3h8.5M103.3 129.2h8.5M103.3 129.1h8.5"/>
<path d="M103.3 129h8.5M103.3 128.9h8.5M103.3 128.8h8.5M103.3 128.7h8.5M103.3 128.6h8.5M103.3 128.5h8.5M103.3 128.4h8.5M103.3 128.3h8.5M103.3 128.2h8.5M103.3 128.1h8.5M103.3 128h8.5M103.3 127.9h8.5"/>
<path d="M103.3 127.8h8.5M103.3 127.7h8.5M103.3 127.6h8.5M103.3 127.5h8.5M103.3 127.4h8.5M103.3 127.3h8.5M103.3 126.8h8.7M103.3 126.7h8.8M103.3 126.6h8.8M103.3 126.5h8.8M103.3 126.4h8.8M103.3 126.3h8.9"/>
<path d="M103.3 126.2h8.9M103.3 126h9M103.3 125.9h8M103.3 125.8l7.9 .1M103.3 125.7l7.6 .1M103.3 125.7h7.5M103.3 125.6h7.4M103.3 125.6h7.3M103.3 125.5h7.3M103.3 125.5h7.2M103.3 125.3l7.1 .1M103.3 125.2h7"/>
<path d="M103.3 125.1h6.9M105.6 125.1h4.6M105.7 125h4.5M105.8 125l-.3 .1M106 131.4l.7 .3M106.2 131.4h24.8M106.2 124.9h4M106.3 131.5h24.6M106.3 124.9h3.8M106.4 131.6h24.4M106.5 124.8h3.6M106.6 124.8h3.5"/>
<path d="M106.7 131.7l8.9 8.9M106.7 131.7h12M106.7 124.7h3.4M106.7 131.7h11.9M106.8 131.8h11.6M106.8 124.7h3.2M106.8 131.8h11.5M106.9 124.6h3.1M106.9 131.9h11.2M107 122l3 .1M107 122h3M107 124.5h3"/>
<path d="M107 132h11M107 122.1h3M107 121.9h3M107.1 124.4h2.9M107.1 122.2h3M107.1 121.9h2.9M107.1 132.1h10.8M107.1 121.8h2.9M107.2 124.3h2.8M107.2 122.3h2.9M107.2 121.8h2.8M107.2 132.2h10.6"/>
<path d="M107.3 132.2h10.5M107.3 122.3h2.8M107.3 121.7h2.7M107.3 124.2h2.7M107.3 122.4h2.9M107.3 124.1h2.7M107.3 121.6h2.7M107.3 132.3h10.4M107.3 122.5h2.9M107.3 124h2.7M107.3 122.5l2.9 .1M107.3 121.5h2.7"/>
<path d="M107.4 132.3h10.3M107.4 124h2.6M107.4 122.6h2.8M107.4 121.5h2.6M107.4 120l2.8 .1M107.4 122.6h2.9M107.4 120.1h2.9M107.4 123.9h2.6M107.4 122.7h2.9M107.4 121.4h2.6M107.4 120.1l2.9 .1M107.4 132.4h10.2"/>
<path d="M107.4 122.7l3 .1M107.4 120.2h3M107.4 122.8h3M107.4 120.2l3 .1M107.5 132.4h10.1M107.5 122.9h3M107.5 120.4h3M107.5 120.3h3M107.5 123.6l-.2 .6-.5 .5-.6 .3M107.5 120.4v.7M107.5 123v.6M107.5 121.1l-.2 .6-.4 .3 .4 .3 .2 .7"/>
<path d="M107.5 132.5h10M107.5 123.6h2.7M107.5 123h3.1M107.5 120.4h3.1M107.6 132.5h9.9M107.6 132.6h9.8M107.7 132.7h9.7M107.7 132.7h9.6M107.8 132.8h9.4M107.9 132.9h9.2M108 133h9.1M108.1 133h8.9"/>
<path d="M108.1 133.1h8.8M108.2 133.1h8.7M108.2 133.2h8.6M108.3 133.2h8.5M108.3 133.3h8.4M108.4 133.3h8.3M108.4 133.4h8.2M108.5 133.5h8M108.6 133.6h7.8M108.7 133.7h7.7M108.8 133.8h7.6M108.8 133.8h7.5"/>
<path d="M108.9 133.9h7.4M109 134h7.3M109.1 134h7.1M109.1 134.1h7.1M109.2 134.1h7M109.2 134.2h7M109.3 134.2h6.9M109.3 134.3h6.9M109.4 134.3h6.8M109.4 134.4h6.8M109.5 134.5h6.7M109.6 134.6h6.6"/>
<path d="M109.7 134.7h6.5M109.8 134.8h6.4M109.9 134.8h6.3M109.9 134.9h6.3M110 134.9h6.2M110 135h6.2M110 123.8l-2.6 .1M110 121.3h-2.6M110.1 135h6.1M110.1 123.8h-2.7M110.1 121.3h-2.7M110.1 123.7l-2.7 .1"/>
<path d="M110.1 121.2h-2.7M110.1 135.1h6.1M110.1 123.7h-2.6M110.1 121.2h-2.6M110.1 123.6l-2.6 .1M110.1 121.1h-2.6M110.2 121.1h-2.7M110.2 135.1h6M110.2 123.5h-2.7M110.2 121h-2.7M110.2 120.9l-2.7 .1M110.2 125.1h-6.9v6.3h27.7"/>
<path d="M110.2 135.2h6M110.2 123.4h-2.7M110.2 120.9h-2.7M110.2 120.8l-2.7 .1M110.3 123.3a1.71 1.71 0 0 0 1 2.6M110.3 123.3h-2.8M110.3 135.3h5.9M110.3 120.8h-2.8M110.3 120.7l-2.8 .1M110.4 123.2l-2.9 .1M110.4 120.7h-2.9M110.4 135.4h5.8"/>
<path d="M110.4 123.2h-2.9M110.4 120.6h-2.9M110.5 123.1h-3M110.5 120.6h-3M110.5 135.5h5.7M110.5 120.5h-3M110.6 120.5a1.63 1.63 0 0 0 0 2.5M110.6 123l-.3 .3M110.6 123h-3.1M110.6 120.5h-3.1M110.6 135.6h5.6M110.7 135.7h5.5"/>
<path d="M110.7 135.7h5.4M110.8 135.8h5.2M110.8 135.8h5.1M110.9 135.9h5M111 135.9h4.8M111 136h4.7M111.1 136h4.6M111.1 136.1h4.5M111.2 136.1h4.4M111.2 136.2h4.3M111.3 136.2h4.2M111.3 136.3h4.1"/>
<path d="M111.4 136.4h4M111.5 136.5h3.9M111.6 136.6h3.7M111.7 136.6h3.6M111.7 136.7h3.6M111.8 136.7h3.5M111.8 136.8h3.5M111.8 127.3v2.2M111.8 129.5l.3 .7 .5 .5 .7 .2M111.8 127.3h-8.5M111.9 136.8h3.3M111.9 127.2h-8.6"/>
<path d="M111.9 127.1l-8.6 .1M111.9 127.1h-8.6M111.9 136.9h3.3M111.9 127l-8.6 .1M112 127h-8.7M112 136.9h3.2M112 126.9l-8.7 .1M112 126.9h-8.7M112 137h3.2M112 126.8h-8.7M112.1 126.7h-8.8M112.1 126.5v.2"/>
<path d="M112.1 126.7l-.3 .6M112.1 137.1h3.1M112.1 126.3l-8.8 .1M112.2 137.2h3M112.3 137.3h2.9M112.3 126h-9M112.4 137.3h2.8M112.4 137.4h2.8M112.5 137.4h2.7M112.5 137.5h2.7M112.6 137.5h2.6M112.6 137.6h2.6"/>
<path d="M112.7 137.6h2.5M112.7 137.7h2.5M112.8 137.8h2.5M112.9 137.9h2.4M113 138h2.3M113 138h2.4M113.1 138.1h2.3M113.1 138.1l2.3 .1M113.2 138.2h2.2M113.2 138.2l2.3 .1M113.3 138.3h2.2M113.3 138.3l2.2 .1"/>
<path d="M113.4 138.4h2.2M113.5 138.4l2.2 .1M113.5 138.5h2.2M113.6 138.5l2.2 .1M113.6 138.6h2.2M113.7 138.6l2.2 .1M113.7 138.7h2.2M113.8 138.7l2.2 .1M113.8 138.8h2.3M113.9 138.9h2.3M113.9 138.9h2.5M114 139h2.5"/>
<path d="M114 130.9h1.7M114 139h2.6M114.1 139.1h20.6M114.2 139.1h20.5M114.2 130.8h1.4M114.2 139.2h20.4M114.3 139.2h20.2M114.3 139.3h20.2M114.3 130.8h1.2M114.4 139.3h20M114.4 139.4h20M114.4 130.7h.9"/>
<path d="M114.5 139.4h19.8M114.5 139.5h19.8M114.5 130.7h.7M114.6 139.6h19.6M114.6 130.6h.5M114.7 139.7h19.4M114.7 130.6h.4M114.7 130.5h.3M114.8 139.8h19.2M114.8 130.5h.1M114.9 130.4l-.9 .5M114.9 130.4l.9 .5"/>
<path d="M114.9 130.4h.1M114.9 139.9h19M115 140h18.8M115.2 137.6l.3 .7 .5 .5M116 135.8l-.5 .5-.3 .6v.7M116 138.8l.6 .3M116.2 135.7l-.2 .1M116.4 133.6l-.2 .5v1.6M116.6 130.9h1.7M116.7 130.8h1.4M116.8 130.8h1.2M117 130.7h.8"/>
<path d="M117.1 130.7h.7M117.2 130.6h.4M117.3 130.5h.2M117.4 130.4h.1M117.4 130.4l-.9 .5M117.4 130.4l.9 .5M118.1 131.9l-1.7 1.7M118.7 131.6l-.6 .3M118.9 139h4M119 139h3.9M119.1 130.9h1.7M119.1 138.9h3.6"/>
<path d="M119.2 138.9h3.4M119.3 135.7l.2 .1M119.3 135v.7M119.3 135.5h3.4M119.3 135.4h3.4M119.3 135.3h3.4M119.3 135.2h3.5M119.3 135.1h3.5M119.3 130.8h1.3M119.3 135.7h3.3M119.4 138.8h3M119.4 135.7h3"/>
<path d="M119.4 130.8h1.1M119.5 138.8h2.8M119.5 135.8l.5 .5 .3 .6M119.5 135.8h2.8M119.5 130.7h.9M119.5 138.7h2.8M119.6 134.7h3.7l-.5 .4M119.6 138.7h2.6M119.6 135.9h2.6M119.6 130.7h.7M119.6 134.7l-.3 .3M119.7 138.6h2.5"/>
<path d="M119.7 135.9h2.5M119.7 138.6h2.4M119.7 136h2.4M119.7 130.6h.5M119.8 138.5h2.2M119.8 136h2.2M119.8 130.6h.3M119.8 136.1h2.2M119.8 130.5h.3M119.9 138.4h2M119.9 136.1h2.1M119.9 130.5h.1"/>
<path d="M119.9 136.2h2M119.9 130.4h.1M120 130.4l-1 .5M120 130.4l.9 .5M120 138.3h1.8M120 136.2h1.8M120 138.2l1.8 .1M120 136.3h1.8M120 138.2h1.8M120 136.4h1.8M120.1 138.1l1.7 .1M120.1 136.4h1.7"/>
<path d="M120.1 138.1h1.6M120.1 136.5h1.7M120.1 138h1.6M120.1 136.5h1.6M120.1 136.6h1.6M120.1 137.9h1.6M120.2 137.9h1.4M120.2 136.7h1.4M120.2 137.8h1.4M120.2 136.8h1.4M120.2 137.7h1.4M120.2 136.9h1.4"/>
<path d="M120.3 137.6h1.2M120.3 137.6l-.3 .7-.5 .5-.6 .3M120.3 136.9v.7M120.3 137.5h1.2M120.3 137.4h1.2M120.3 137.3h1.2M120.3 137.2h1.2M120.3 137.1h1.2M120.3 137h1.2M120.3 136.9h1.2M121.5 136.9v.7M121.5 137.6l.3 .7 .5 .5"/>
<path d="M121.6 130.9h1.8M121.8 130.8h1.4M121.9 130.8h1.2M122.1 130.7h.8M122.2 130.7h.6M122.3 130.6h.4M122.3 138.8l.7 .3M122.4 130.5h.2M122.5 130.4h.1M122.5 130.4l-.9 .5M122.5 130.4l.9 .5M122.6 135.7l-.8 .6-.3 .6"/>
<path d="M122.6 135.6l-3.3 .1M122.6 135.6h-3.3M122.6 135.5l-3.3 .1M122.7 135.4h-3.4M122.7 135.3h-3.4M122.8 135.1l-.2 .6M122.9 135.1h-3.6M122.9 135l-3.6 .1M123 135h-3.7M123 134.9l-3.7 .1M123.1 134.9h-3.7M123.1 134.8l-3.7 .1"/>
<path d="M123.2 134.8h-3.7M123.2 134.7h-3.7M124.2 130.9h1.7M124.3 130.8h1.4M124.5 130.8h1.1M124.6 130.7h.9M124.7 130.7h.7M124.8 130.6h.5M124.8 130.6h.4M124.9 130.5h.3M125 130.5h.1M125 130.4h.1"/>
<path d="M125 130.4l-.9 .5M125 130.4l.9 .5M125.2 139h4.1M125.3 139h3.9M125.5 138.9h3.6M125.6 138.9h3.3M125.7 138.8h3.1M125.8 138.8h2.9M125.9 138.8l-.7 .3M125.9 138.7h2.7M126 138.6h2.5M126.1 138.5h2.3"/>
<path d="M126.2 138.5h2.2M126.2 138.4h2.1M126.3 138.4h1.9M126.3 138.3h1.9M126.4 138.2h1.7M126.4 138.1h1.7M126.4 138h1.7M126.5 138h1.5M126.5 137.9h1.5M126.5 136.6h1.5M126.5 136.7h1.5M126.5 137.8h1.5"/>
<path d="M126.6 137.8h1.4M126.6 136.8h1.4M126.6 137.7h1.3M126.6 136.8h1.3M126.6 136.9h1.3M126.6 137.6h1.3M126.6 137.6l-.3 .7-.4 .5M126.6 137.5h1.3M126.6 137.4h1.3M126.6 137.3h1.3M126.6 137.2h1.3M126.6 137.1h1.3"/>
<path d="M126.6 137h1.3M127.6 125.9l3.3 .1M127.6 125.9l.2 .6M127.6 125.9v.1M127.6 126h3.4M127.6 126l3.5 .1M127.7 126.1h3.5M127.7 126.1l46.3 .1M127.7 126.2h46.3M127.7 126.3h46.3M127.8 126.3h46.2M127.8 126.4h46.2"/>
<path d="M127.8 126.7l.3 .6M127.8 126.5v.2M127.8 126.6h46.2M127.8 126.5h46.2M127.9 136.9l.1-.3h-1.5l.1 1M127.9 136.9v.7M127.9 137.6l.3 .7M127.9 126.8h7.8M127.9 126.9h7.6M128 127h7.4M128 127h7.3M128 127.1h7.3"/>
<path d="M128 127.1h7.2M128 127.2h7.2M128.1 127.3h7M128.1 129.5l-.3 .7-.5 .5-.6 .2M128.1 127.3v2.2M128.2 138.3l.5 .5M128.7 125.9h2M128.7 138.8l.6 .3M128.8 125.9h1.9M130.6 125.8l.1 .1M130.6 125.8h-1.7l-.3 .1M130.7 125.9l.6 .3"/>
<path d="M131 131.3l-27.7 .1M131.1 131.3h-27.8M131.1 131.2l-27.8 .1M131.2 131.2h-27.9M131.3 131.1h-28M131.4 131h-28.1M131.5 130.9h-4.8M131.6 130.8h-4.7M131.7 130.7l-4.7 .1M131.7 130.7h-4.6M131.7 130.6l-4.5 .1M131.8 130.6h-4.5"/>
<path d="M131.8 138.9h3.1M131.8 130.5l-4.4 .1M131.9 130.5h-4.5M132 130.4l-4.5 .1M132 130.4h-4.4M132.1 130.3h-4.5M132.1 130.3h-4.4M132.2 138.8l-.6 .3M132.2 130.2h-4.5M132.2 126.1h41.8M132.2 130.2h-4.4M132.3 126.1h41.7"/>
<path d="M132.3 130.1h-4.5M132.4 130l-4.6 .1M132.4 130h-4.5M132.4 126h41.6M132.4 129.9l-4.5 .1M132.5 129.9h-4.6M132.5 126h41.5M132.5 129.8l-4.6 .1M132.6 129.8h-4.6M132.7 129.7l-4.7 .1M132.7 129.7h-4.7M132.7 125.9h41.3"/>
<path d="M132.8 129.6l-4.8 .1M132.8 125.8h41.2M132.8 129.6h-4.8M132.9 129.5l-4.8 .1M132.9 125.7h41.1M132.9 129.5h-4.8M132.9 125.6h41.1M133 129.4l-4.9 .1M133 129.4h-4.9M133 125.6h41M133 121.7h4.1M133.1 125.5h40.9"/>
<path d="M133.1 121.7h4M133.1 129.3h-5M133.1 121.8h4M133.2 125.4h40.8M133.2 129.2h-5.1M133.2 121.8h3.9M133.2 121.9l.3 .6M133.2 125.4h5.1M133.2 125.3h5M133.3 125.2h4.6M133.3 122h3.8M133.3 125.1h4.4"/>
<path d="M133.3 129.1h-5.2M133.3 125.1l4.5 .1M133.3 122.1h3.7M133.3 125l4.3 .1M133.3 122.2h3.6M133.4 125h4.2M133.4 122.3h3.5M133.4 129h-5.3M133.4 124.9h4.1M133.4 122.4h3.5M133.4 128.9l-5.3 .1M133.4 124.8h4"/>
<path d="M133.5 124.8h3.9M133.5 122.5h3.4M133.5 122.5v2.3M133.5 124.8l-.3 .6-.5 .5-.6 .3M133.5 124.7h3.8M133.5 124.7h3.7M133.5 124.6h3.7M133.5 124.5l3.7 .1M133.5 124.5h3.6M133.5 124.4l3.6 .1M133.5 124.4h3.6M133.5 124.3l3.6 .1"/>
<path d="M133.5 124.3h3.5M133.5 124.2h3.5M133.5 124.1l3.5 .1M133.5 124.1h3.5M133.5 124h3.4M133.5 123.9h3.4M133.5 123.8h3.4M133.5 123.7h3.4M133.5 123.6h3.4M133.5 123.5h3.4M133.5 123.4h3.4M133.5 123.3h3.4"/>
<path d="M133.5 123.2h3.4M133.5 123.1h3.4M133.5 123h3.4M133.5 122.9h3.4M133.5 122.8h3.4M133.5 122.7h3.4M133.5 122.6h3.4M133.5 128.9h-5.4M133.6 128.8l-5.5 .1M133.6 128.8h-5.5M133.6 128.7l-5.5 .1M133.7 138.6h1.5"/>
<path d="M133.7 128.7h-5.6M133.8 128.6l-5.7 .1M133.8 128.6h-5.7M133.9 128.5h-5.8M134 128.4h-5.9M134.1 128.3h-6M134.1 128.2l-6 .1M134.2 128.2h-6.1M134.3 128.1l-6.2 .1M134.3 128.1h-6.2M134.3 128l-6.2 .1M134.4 128h-6.3"/>
<path d="M134.5 127.9l-6.4 .1M134.5 127.9h-6.4M134.6 127.8l-6.5 .1M134.6 127.8h-6.5M134.7 127.7l-6.6 .1M134.7 127.7h-6.6M134.7 139h-3.1M134.8 127.6l-6.7 .1M134.8 139h-3.1M134.8 127.6h-6.7M134.9 127.5l-6.8 .1M134.9 138.9h-3"/>
<path d="M134.9 127.5h-6.8M135 138.8h-2.9M135 127.4h-6.9M135 127.4l-4.3 4.2h-24.2M135 138.7l-1.7 .1M135.1 138.7h-1.6M135.1 127.3h-7M135.1 138.6l-1.6 .1M135.2 138.5l-1.4 .1M135.3 138.5h-1.4M135.4 138.4l-1.5 .1M135.4 138.4h-1.4"/>
<path d="M135.4 138.3l-1.4 .1M135.5 138.3h-1.4M135.6 138.2l-1.5 .1M135.6 138.2h-1.4M135.6 126.9h-7.7M135.7 138.1l-1.5 .1M135.7 138.1h-1.4M135.8 138h-1.5M135.8 138h-1.4M135.9 137.9h-1.4M135.9 126.8h-8M136 126.7h-8.2"/>
<path d="M136 126.7l-.6 .2-.4 .5M136 137.8h-1.4M136.1 137.7h-1.4M136.1 137.6l-1.4 .1M136.2 137.6h-1.4M136.2 137.5l-1.4 .1M136.3 137.5h-1.4M136.3 137.4l-1.4 .1M136.4 137.4h-1.4M136.4 137.3l-1.4 .1M136.5 137.3h-1.4M136.6 137.2h-1.5"/>
<path d="M136.6 137.2h-1.4M136.7 137.1h-1.4M136.8 137h-1.4M136.8 136.9l-1.4 .1M136.9 136.9h-1.4M136.9 122.3v1.7M136.9 124l.1 .2M136.9 136.8l-1.4 .1M137 122.2h-3.7M137 124.2l.1 .2M137 136.8h-1.4M137 136.7l-1.4 .1"/>
<path d="M137 122l-3.7 .1M137.1 124.4l.1 .2M137.1 121.9l-3.9 .1M137.1 136.7h-1.4M137.1 121.9h-3.9M137.1 121.8v-.1h-4.1l.2 .2M137.1 121.8l-.2 .5M137.1 136.6l-1.4 .1M137.2 124.6l.7 .6M137.2 136.6h-1.4M137.3 136.5h-1.5M137.3 136.5h-1.4"/>
<path d="M137.4 136.4h-1.4M137.5 136.3h-1.4M137.5 136.2l-1.4 .1M137.6 136.2h-1.4M137.6 136.1l-1.4 .1M137.7 136.1h-1.4M137.7 136l-1.4 .1M137.8 136h-1.4M137.8 135.9l-1.4 .1M137.9 135.9h-1.4M137.9 125.2l.1 .1M138 135.8l-1.5 .1"/>
<path d="M138 135.8h-1.4M138 135.7l-1.4 .1M138.1 125.3l.2 .1M138.1 135.7h-1.4M138.2 135.6l-1.5 .1M138.2 135.6h-1.4M138.3 135.5l-1.5 .1M138.3 135.5h-1.4M138.4 135.4h-1.5M138.4 135.4h-1.4M138.5 135.3h-1.4M138.6 135.2h-1.4"/>
<path d="M138.6 135.1l-1.4 .1M138.7 135.1h-1.4M138.7 135l-1.4 .1M138.8 135l-5.6 5.6-17.6-.1M138.8 135h-1.4M138.9 134.9l-1.5 .1M138.9 134.9h-1.4M138.9 134.8l-1.4 .1M139 134.8h-1.4M139 134.7h-1.4M139.1 134.7h-1.4M139.1 125.4h11.9"/>
<path d="M139.2 134.6h-1.4M139.2 125.3h11.6M139.3 134.5h-1.4M139.3 125.3l-.3 .1M139.4 134.5h-1.5M139.4 125.2h11.2M139.5 125.2h11.1M139.5 134.4h-1.5M139.6 125.2h10.9M139.7 134.3l-1.7 .1M139.7 125.1h10.7M139.8 125.1h10.5"/>
<path d="M139.8 134.3h-1.7M139.8 125h10.5M139.9 124.9h10.3M139.9 134.2l-.6 .3-.5 .5M140 124.8h10.1M140.1 124.7h9.9M140.1 124.7h9.8M140.2 124.6l-.8 .7M140.2 124.6h9.7M140.2 121.8l.3 .5M140.2 124.5h9.6M140.2 121.8h9.6"/>
<path d="M140.3 124.5h9.5M140.3 124.4h9.5M140.3 121.9h9.5M140.3 121.7h9.6M140.3 121.6h9.6M140.3 122h9.4M140.3 121.5h9.6M140.4 124.2l-.2 .4M140.4 124.3h9.3M140.4 124.2h9.3M140.4 122.1h9.3M140.4 121.5h9.5"/>
<path d="M140.4 122.2h9.3M140.4 121.4h9.5M140.4 124.1h9.3M140.4 122.3h9.2M140.4 122.2h9.2M140.4 121.3h9.5M140.4 124h9.2M140.5 124l-.1 .2M140.5 122.3v1.7M140.5 121.3l-.3 .5M140.5 124h9.1M140.5 123.9h9.1"/>
<path d="M140.5 123.8h9.1M140.5 123.7h9.1M140.5 123.6h9.1M140.5 123.5h9.1M140.5 123.4h9.1M140.5 123.3h9.1M140.5 123.2h9.1M140.5 123.1h9.1M140.5 123h9.1M140.5 122.9h9.1M140.5 122.8h9.1M140.5 122.7h9.1"/>
<path d="M140.5 122.6h9.1M140.5 122.5h9.1M140.5 122.4h9.1M140.5 122.3h9.1M140.5 121.2h9.4M140.5 121.1h9.4M140.5 121h9.4M140.5 120.9h9.4M140.5 120.8h9.4M140.5 120.7h9.4M140.5 120.6h9.4M140.5 120.5h9.4"/>
<path d="M140.5 120.4h9.4M140.5 120.3h9.4M140.5 120.2h9.4M140.5 120.1h9.4M149.6 122.3v1.7M149.6 124l.1 .2M149.7 124.2l.1 .2M149.8 124.4l.1 .2M149.8 121.8l-9.5 .1M149.9 121.7l-.3 .6M149.9 121.7l-9.6 .1M149.9 124.6l.7 .6"/>
<path d="M150.6 125.2l.1 .1M150.8 125.3l.2 .1M151.8 125.4h22.2M151.9 125.3h22.1M152 125.3l-.3 .1M152.1 125.3h21.9M152.1 125.2v.1M152.2 125.2h21.8M152.3 125.2h21.7M152.4 125.1h21.6M152.5 125.1h21.5M152.5 125h21.5"/>
<path d="M152.6 124.9h21.4M152.7 124.8h21.3M152.8 124.7h21.2M152.9 124.6l-.8 .6M152.9 124.6h21.1M152.9 121.7l.3 .6M152.9 121.6h21.1M152.9 121.7h21.1M152.9 121.5h21.1M152.9 121.4h21.1M152.9 121.3h21.1M152.9 121.2h21.1"/>
<path d="M152.9 121.1h21.1M152.9 121h21.1M152.9 120.9h21.1M152.9 120.8h21.1M152.9 120.7h21.1M152.9 120.6h21.1M152.9 120.5h21.1M152.9 120.4h21.1M152.9 120.3h21.1M152.9 120.2h21.1M152.9 120.1h21.1M152.9 124.5h21.1"/>
<path d="M152.9 121.8h21.1M153 124.5h21M153 121.8h21M153 124.4h21M153 121.9h21M153 124.4l-.1 .2M153 122h21M153.1 124.2l-.1 .2M153.1 124.3h20.9M153.1 124.2h20.9M153.1 122.1h20.9M153.1 122.2h20.9"/>
<path d="M153.1 124.1h20.9M153.1 122.3h20.9M153.1 124h20.9M153.2 124l-.1 .2M153.2 122.3v1.7M153.2 124h20.8M153.2 123.9h20.8M153.2 123.8h20.8M153.2 123.7h20.8M153.2 123.6h20.8M153.2 123.5h20.8M153.2 123.4h20.8"/>
<path d="M153.2 123.3h20.8M153.2 123.2h20.8M153.2 123.1h20.8M153.2 123h20.8M153.2 122.9h20.8M153.2 122.8h20.8M153.2 122.7h20.8M153.2 122.6h20.8M153.2 122.5h20.8M153.2 122.4h20.8M153.2 122.3h20.8M178 134.2h-39.8"/>
<path d="M178.1 134.1l-39.9 .1M178.1 134.1h-39.8M178.2 134l-39.9 .1M178.2 134h-39.8M178.3 133.9l-39.9 .1M178.3 133.9h-39.8M178.4 133.8l-39.9 .1M178.4 133.8h-39.8M178.5 133.7l-39.9 .1M178.5 133.7h-39.8M178.6 133.6h-39.9M178.6 133.6h-39.8"/>
<path d="M178.7 133.5h-39.8M178.8 133.4h-39.8l-5.2 5.2-.5 .2M178.8 133.3l-1.7 .1M178.9 133.3h-1.6M178.9 133.2l-1.5 .1M179 133.2h-1.5M179 133.1l-1.3 .1M179.1 133.1h-1.4M179.2 133l-1.4 .1M179.2 133h-1.4M179.3 132.9h-1.4M179.4 132.8h-1.4"/>
<path d="M179.5 132.7h-1.4M179.6 132.6h-1.4M179.6 132.5l-1.4 .1M179.7 132.5h-1.4M179.7 132.4l-1.4 .1M179.8 132.4h-1.4M179.9 132.3l-1.5 .1M179.9 132.3h-1.4M180 132.2l-1.5 .1M180 132.2h-1.4M180.1 132.1l-1.5 .1M180.1 132.1h-1.4"/>
<path d="M180.2 132l-1.4 .1M180.2 132h-1.4M180.3 131.9l-1.4 .1M180.3 130.5h1.4M180.3 131.9h-1.4M180.4 130.5h1.3M180.4 131.8h-1.4M180.4 130.4h1.3M180.5 130.3h1.2M180.5 131.7h-1.4M180.6 130.2h1.1M180.6 131.6h-1.4"/>
<path d="M180.6 130.2l-3 3-.5 .2M180.6 130.1h1.1M180.7 130.1h1M180.7 130h1M180.7 131.5h-1.4M180.7 129.9h1M180.7 131.4l-1.4 .1M180.8 129.8h.9M180.8 131.4h-1.4M180.8 129.7h.9M180.8 125.1h.9M180.8 125h.9"/>
<path d="M180.8 125.3h.9M180.8 125.4h.9M180.8 126.7h.9M180.8 129.6l-.2 .6M180.8 125.9h.9M180.8 125.8h.9M180.8 126.1h.9M180.8 121.6h.9M180.8 129.6h.9M180.8 129.5h.9M180.8 129.4h.9M180.8 129.3h.9"/>
<path d="M180.8 129.2h.9M180.8 129.1h.9M180.8 129h.9M180.8 128.9h.9M180.8 128.8h.9M180.8 128.7h.9M180.8 128.6h.9M180.8 128.5h.9M180.8 128.4h.9M180.8 128.3h.9M180.8 128.2h.9M180.8 128.1h.9"/>
<path d="M180.8 128h.9M180.8 127.9h.9M180.8 127.8h.9M180.8 127.7h.9M180.8 127.6h.9M180.8 127.5h.9M180.8 127.4h.9M180.8 127.3h.9M180.8 127.2h.9M180.8 127.1h.9M180.8 127h.9M180.8 126.9h.9"/>
<path d="M180.8 126.8h.9M180.8 126.6h.9M180.8 126.5h.9M180.8 126.4h.9M180.8 126.3h.9M180.8 126.2h.9M180.8 126h.9M180.8 125.7h.9M180.8 125.6h.9M180.8 125.5h.9M180.8 125.2h.9M180.8 124.9h.9"/>
<path d="M180.8 124.8h.9M180.8 124.7h.9M180.8 124.6h.9M180.8 124.5h.9M180.8 124.4h.9M180.8 124.3h.9M180.8 124.2h.9M180.8 124.1h.9M180.8 124h.9M180.8 123.9h.9M180.8 123.8h.9M180.8 123.7h.9"/>
<path d="M180.8 123.6h.9M180.8 123.5h.9M180.8 123.4h.9M180.8 123.3h.9M180.8 123.2h.9M180.8 123.1h.9M180.8 123h.9M180.8 122.9h.9M180.8 122.8h.9M180.8 122.7h.9M180.8 122.6h.9M180.8 122.5h.9"/>
<path d="M180.8 122.4h.9M180.8 122.3h.9M180.8 122.2h.9M180.8 122.1h.9M180.8 122h.9M180.8 121.9h.9M180.8 121.8h.9M180.8 121.7h.9M180.8 121.5h.9M180.8 121.4h.9M180.8 121.3h.9M180.8 121.2h.9"/>
<path d="M180.8 121.1h.9M180.8 121h.9M180.8 120.9h.9M180.8 120.8h.9M180.8 120.7h.9M180.8 120.6h.9M180.8 120.5h.9M180.8 120.4h.9M180.8 120.3h.9M180.8 120.2h.9M180.8 120.1h.9M180.8 131.3l-1.3 .1"/>
<path d="M180.9 131.3h-1.4M181 131.2l-1.4 .1M181 140h22M181 131.2h-1.4M181.1 140h21.9M181.1 131.1h-1.4M181.1 139.9h21.9M181.1 139.8h21.9M181.2 131h-1.4M181.2 139.8h21.8M181.3 130.9h-1.4M181.3 139.7h21.7"/>
<path d="M181.4 139.6h21.6M181.4 130.8h-1.4M181.4 130.7l-1.4 .1M181.5 139.5h21.5M181.5 139.6h21.5M181.5 130.7h-1.4M181.5 130.6l-1.4 .1M181.6 139.4h21.4M181.6 130.6h-1.4M181.7 139.3h21.3M181.7 130.5l-1.5 .1M181.7 130.5l-3.8 3.7-39.8 .1"/>
<path d="M181.8 139.3h21.2M181.8 139.2h21.2M181.8 139.1h21.2M181.9 139.1h21.1M182 139h21M182.1 138.9h20.9M182.2 138.8h20.8M182.3 138.7h20.7M182.4 138.6h20.6M182.5 138.5h20.5M182.6 138.4h20.4M182.7 138.3h20.3"/>
<path d="M182.8 138.2h20.2M182.9 138.1h20.1M183 138h20M183 137.9h20M183.1 137.9h19.9M183.2 137.8h19.8M183.3 137.7h19.7M183.4 137.6h19.6M183.5 137.5h19.5M183.6 137.4h19.4M183.7 137.4h19.3M183.7 137.3h19.3"/>
<path d="M183.7 137.2h19.3M183.8 137.2h19.2M183.9 137.1h19.1M184 137h19M184.1 136.9h18.9M184.2 136.8h18.8M184.3 136.7h18.7M184.4 136.7h18.6M184.4 136.6h18.6M184.4 136.5h18.6M184.5 136.5h18.5M184.6 136.4h18.4"/>
<path d="M184.7 136.3h18.3M184.8 136.2h18.2M184.9 136.1h18.1M185 136h18M185.1 135.9h17.9M185.1 135.8h17.9M185.2 135.8h17.8M185.3 135.8h17.7M185.3 135.7h17.7M185.4 135.6h17.6M185.5 135.5h17.5M185.6 135.4h17.4"/>
<path d="M185.7 135.3h17.3M185.8 135.2h17.2M185.8 135.1h17.2M185.9 135.1h17.1M186 135h17M186.1 134.9h16.9M186.2 134.8h16.8M186.3 134.7h16.7M186.4 134.6h16.6M186.5 134.5h16.5M186.6 134.4h16.4M186.7 134.3h16.3"/>
<path d="M186.8 134.2h16.2M186.9 134.1h16.1M187 134h.1M187 134h16M187 133.9h16M187.1 133.9h15.9M187.2 133.9h15.8M187.2 133.8h15.8M187.3 133.7h15.7M187.4 133.6h15.6M187.5 133.5h15.5M187.5 133.5l-6.5 6.6"/>
<path d="M187.5 133.4h15.5M187.6 133.3h15.4M187.6 133.2h15.4M187.6 133.1h15.4M187.7 133h15.3M187.7 132.9h15.3M187.7 131.4h15.3M187.7 125.1h15.3M187.7 125h15.3M187.7 132.9l-.2 .6M187.7 125.3h15.3M187.7 125.4h15.3"/>
<path d="M187.7 126.7h15.3M187.7 131.6h15.3M187.7 125.9h15.3M187.7 130.9h15.3M187.7 125.8h15.3M187.7 126.1h15.3M187.7 121.6h15.3M187.7 132.8h15.3M187.7 132.7h15.3M187.7 132.6h15.3M187.7 132.5h15.3M187.7 132.4h15.3"/>
<path d="M187.7 132.3h15.3M187.7 132.2h15.3M187.7 132.1h15.3M187.7 132h15.3M187.7 131.9h15.3M187.7 131.8h15.3M187.7 131.7h15.3M187.7 131.5h15.3M187.7 131.3h15.3M187.7 131.2h15.3M187.7 131.1h15.3M187.7 131h15.3"/>
<path d="M187.7 130.8h15.3M187.7 130.7h15.3M187.7 130.6h15.3M187.7 130.5h15.3M187.7 130.4h15.3M187.7 130.3h15.3M187.7 130.2h15.3M187.7 130.1h15.3M187.7 130h15.3M187.7 129.9h15.3M187.7 129.8h15.3M187.7 129.7h15.3"/>
<path d="M187.7 129.6h15.3M187.7 129.5h15.3M187.7 129.4h15.3M187.7 129.3h15.3M187.7 129.2h15.3M187.7 129.1h15.3M187.7 129h15.3M187.7 128.9h15.3M187.7 128.8h15.3M187.7 128.7h15.3M187.7 128.6h15.3M187.7 128.5h15.3"/>
<path d="M187.7 128.4h15.3M187.7 128.3h15.3M187.7 128.2h15.3M187.7 128.1h15.3M187.7 128h15.3M187.7 127.9h15.3M187.7 127.8h15.3M187.7 127.7h15.3M187.7 127.6h15.3M187.7 127.5h15.3M187.7 127.4h15.3M187.7 127.3h15.3"/>
<path d="M187.7 127.2h15.3M187.7 127.1h15.3M187.7 127h15.3M187.7 126.9h15.3M187.7 126.8h15.3M187.7 126.6h15.3M187.7 126.5h15.3M187.7 126.4h15.3M187.7 126.3h15.3M187.7 126.2h15.3M187.7 126h15.3M187.7 125.7h15.3"/>
<path d="M187.7 125.6h15.3M187.7 125.5h15.3M187.7 125.2h15.3M187.7 124.9h15.3M187.7 124.8h15.3M187.7 124.7h15.3M187.7 124.6h15.3M187.7 124.5h15.3M187.7 124.4h15.3M187.7 124.3h15.3M187.7 124.2h15.3M187.7 124.1h15.3"/>
<path d="M187.7 124h15.3M187.7 123.9h15.3M187.7 123.8h15.3M187.7 123.7h15.3M187.7 123.6h15.3M187.7 123.5h15.3M187.7 123.4h15.3M187.7 123.3h15.3M187.7 123.2h15.3M187.7 123.1h15.3M187.7 123h15.3M187.7 122.9h15.3"/>
<path d="M187.7 122.8h15.3M187.7 122.7h15.3M187.7 122.6h15.3M187.7 122.5h15.3M187.7 122.4h15.3M187.7 122.3h15.3M187.7 122.2h15.3M187.7 122.1h15.3M187.7 122h15.3M187.7 121.9h15.3M187.7 121.8h15.3M187.7 121.7h15.3"/>
<path d="M187.7 121.5h15.3M187.7 121.4h15.3M187.7 121.3h15.3M187.7 121.2h15.3M187.7 121.1h15.3M187.7 121h15.3M187.7 120.9h15.3M187.7 120.8h15.3M187.7 120.7h15.3M187.7 120.6h15.3M187.7 120.5h15.3M187.7 120.4h15.3"/>
<path d="M187.7 120.3h15.3M187.7 120.2h15.3M187.7 120.1h15.3M97.8 140.5l9 .1M97.8 146.6l105.2 .1M97.8 146.1l14.6 .1M97.8 140.9h9.3M97.8 140.3h8.7M97.8 148.9h105.2M97.8 148.8h105.2M97.8 148.7h105.2M97.8 148.6h105.2"/>
<path d="M97.8 148.5h105.2M97.8 148.4h105.2M97.8 148.3h105.2M97.8 148.2h105.2M97.8 148.1h105.2M97.8 148h105.2M97.8 147.9h105.2M97.8 147.8h105.2M97.8 147.7h105.2M97.8 147.6h105.2M97.8 147.5h105.2M97.8 147.4h105.2"/>
<path d="M97.8 147.3h105.2M97.8 147.2h105.2M97.8 147.1h105.2M97.8 147h105.2M97.8 146.9h105.2M97.8 146.8h105.2M97.8 146.7h105.2M97.8 146.6h15.3M97.8 146.5l15.3 .1M97.8 146.5h15.1M97.8 146.4l15 .1M97.8 146.4h14.8"/>
<path d="M97.8 146.3l14.8 .1M97.8 146.3h14.7M97.8 146.2l14.7 .1M97.8 146.2h14.6M97.8 146.1h7.4M97.8 146h7.3M97.8 146h7M97.8 145.9h6.9M97.8 145.9h6.7M97.8 145.8h6.7M97.8 145.8h6.5M97.8 145.7h6.5"/>
<path d="M97.8 145.6l6.4 .1M97.8 145.6h6.3M97.8 145.5l6.2 .1M97.8 145.5h6.1M97.8 145.4l6.1 .1M97.8 145.4h6M97.8 145.3l6 .1M97.8 145.3h5.9M97.8 145.2h5.9M97.8 145.2h5.8M97.8 145.1h5.8M97.8 145.1h5.7"/>
<path d="M97.8 145h5.7M97.8 144.9l5.7 .1M97.8 144.9h5.6M97.8 144.8l5.6 .1M97.8 144.8h5.6M97.8 144.7l5.5 .1M97.8 144.7h5.5M97.8 144.6l5.5 .1M97.8 144.6h5.5M97.8 144.5h5.4M97.8 144.4h5.4M97.8 144.4h5.3"/>
<path d="M97.8 144.3l5.3 .1M97.8 144.3h5.3M97.8 144.2h5.3M97.8 144.1h5.3M97.8 144h5.3M97.8 144h5.2M97.8 143.9h5.2M97.8 143.8l5.2 .1M97.8 143.8h5.2M97.8 143.7h5.2M97.8 143.6h5.2M97.8 143.5h5.2"/>
<path d="M97.8 143.4h5.2M97.8 143.3h5.2M97.8 143.2h5.2M97.8 143h5.2M97.8 142.9h5.3M97.8 142.8h5.3M97.8 142.7h5.3M97.8 142.6h5.3M97.8 142.5h5.4M97.8 142h5.7M97.8 141.9h5.7M97.8 140.8h9.2"/>
<path d="M97.8 140.7h9.1M97.8 140.6h9M97.8 140.5h8.9M97.8 140.4l8.9 .1M97.8 140.4h8.8M97.8 140.3l8.8 .1M97.8 140.2l8.7 .1M97.8 140.2h8.6M97.8 140.1l8.6 .1M97.8 140.1h8.5M97.8 140l8.5 .1M103 143.8l.5 1.3"/>
<path d="M103 143.1h-5.2M103 143h-5.2M103.1 142.8h-5.3M103.1 142.7h-5.3M103.2 142.5h-5.4M103.2 142.4h-5.4M103.3 142.3l-5.5 .1M103.3 142.3h-5.5M103.3 142.2l-5.5 .1M103.3 142.2h-5.5M103.4 142.1l-5.6 .1M103.4 142.1h-5.6"/>
<path d="M103.4 142l-5.6 .1M103.5 141.9l-5.7 .1M103.5 145.1l.5 .5 1.3 .5M103.6 141.8l-5.8 .1M103.6 141.8h-5.8M103.7 141.7l-5.9 .1M103.7 141.7h-5.9M103.8 141.6h-6M103.9 141.5h-6.1M104 141.4h-6.2M104.1 141.4h-6.3M104.2 141.3h-6.4"/>
<path d="M104.2 141.2l-6.4 .1M104.4 141.2h-6.6M104.4 141.1l-6.6 .1M104.5 141.1h-6.7M104.6 141a2.65 2.65 0 0 0-1.6 2.8M104.6 141l-6.8 .1M104.9 141h-7.1M105 140.9h-7.2M105.3 140.9l-.7 .1M106 140.9a2.62 2.62 0 0 1 2.1 1.6M106 146.1h6.3M106.2 146h6"/>
<path d="M106.2 140.9h.9M106.4 141h.8M106.4 146h5.8M106.6 145.9h5.5M106.6 141l.7 .1M106.7 145.9h5.4M106.7 141.1h.6M106.8 145.8h5.2M106.8 141.1l.6 .1M106.9 141.2h.5M106.9 145.8h5.1M107 145.7h4.9"/>
<path d="M107 141.2l.5 .1M107.1 141.3h.4M107.1 145.7h4.8M107.1 145.6h4.7M107.2 141.4h.4M107.3 145.6h4.5M107.3 141.4h.3M107.3 145.5h4.4M107.3 141.5h.4M107.4 145.5h4.3M107.4 141.5h.3M107.4 145.4h4.2"/>
<path d="M107.4 141.6h.4M107.5 145.4h4M107.5 141.6h.3M107.5 145.3h4M107.5 141.7h.4M107.6 145.2h3.8M107.6 141.7l.3 .1M107.6 141.8h.4M107.7 145.1h3.6M107.7 141.8l.4 .1M107.7 141.9h.4M107.8 145h3.4"/>
<path d="M107.8 141.9l.4 .1M107.8 142h.4M107.8 144.9h3.3M107.8 142l.5 .1M107.9 142.1h.4M107.9 144.8h3.1M107.9 142.1l.5 .1M107.9 142.2h.5M107.9 142.2l.6 .1M107.9 144.7h3M108 144.7h2.9M108 142.3h.5"/>
<path d="M108 144.6h2.8M108 142.3l.6 .1M108 144.5l2.8 .1M108 142.4h.6M108.1 142.5h.6M108.1 142.5l.1 .6M108.1 144.5a2.73 2.73 0 0 1-2.1 1.6M108.1 144.5h2.6M108.1 144.4h2.5M108.1 142.6h.7M108.1 144.3l2.5 .1M108.1 144.3h2.4"/>
<path d="M108.1 142.7h.8M108.1 144.2l2.3 .1M108.2 144.2h2.2M108.2 144.1h2.1M108.2 142.8l.9 .1M108.2 142.8h.8M108.2 142.9h.9M108.2 144h2M108.2 143h1M108.2 142.9l1 .1M108.2 143.9h1.9M108.2 143l1.1 .1"/>
<path d="M108.2 143.1v.7M108.2 143.8l-.1 .7M108.2 143.8l1.9 .1M108.2 143.8h1.8M108.2 143.7l1.8 .1M108.2 143.7h1.7M108.2 143.6l1.7 .1M108.2 143.6h1.6M108.2 143.5l1.5 .1M108.2 143.5h1.5M108.2 143.4h1.4M108.2 143.3h1.3"/>
<path d="M108.2 143.2h1.2M108.2 143.1h1.1M115.1 140.1h18.6M115.1 140.1h18.5M115.2 140.2h18.4M115.3 140.2h18.2M115.3 140.3h18.2M115.4 140.3h18M115.4 140.4h18M115.5 140.4h17.8M115.5 140.5h17.8M135.7 146.6h67.3"/>
<path d="M135.9 146.5h67.1M136 146.5h67M136.2 146.4h66.8M136.3 146.3h66.7M136.4 146.2h66.6M136.5 146.1h5.8M136.5 146h5.7M136.6 146h5.4M136.7 145.9h5.1M136.7 145.9h5M136.8 145.8h4.8M136.8 145.8h4.7"/>
<path d="M136.9 145.7h4.5M136.9 145.7h4.4M137 145.6h4.2M137 145.6h4.1M137.1 145.5h4M137.1 145.5h3.9M137.2 145.4h3.8M137.2 145.4h3.7M137.3 145.3h3.6M137.4 145.2h3.4M137.5 145.1h3.2M137.6 145h3"/>
<path d="M137.7 144.9h2.9M137.7 144.9h2.8M137.8 144.8h2.7M137.9 144.7h2.5M138 144.6h2.4M138.1 144.5h2.2M138.2 144.4h2.1M138.3 144.3h2M138.4 144.2h1.8M138.5 144.1h1.7M138.6 144h1.6M138.7 143.9h1.5"/>
<path d="M138.7 143.9h1.4M138.8 143.8h1.3M138.9 143.7h1.2M139 143.6h1.1M139.1 143.5h1M139.1 143.4h1M139.2 143.4h.9M139.3 143.3h.8M139.4 143.2h.7M139.5 143.1h.6M139.5 143.1h.7M139.6 143h.6"/>
<path d="M139.8 142.8h.4M139.8 142.7h.5M140 142.6h.3M140.1 143.1v.7M140.1 143.8l.2 .7M140.2 143h-.6M140.2 142.9h-.5M140.2 142.8l-.5 .1M140.3 142.7h-.4M140.3 142.6h-.3M140.3 144.5l.4 .6M140.3 142.5h-.2"/>
<path d="M140.4 142.4h-.2M140.4 142.3h-.1M140.5 142.2l-.2 .1M140.5 142.2h-.1M140.5 142.1h.1M140.5 142l.1 .1M140.6 142l-4.4 4.4-.6 .3M140.6 142l-.5 1.1M140.7 145.1l.5 .5 1.2 .5M141.3 141.3h.1M141.4 141.2l-.1 .1M141.5 141.2h-.1"/>
<path d="M141.6 141.1l-.2 .1M141.7 141.1h-.2M141.8 140.8h61.2M141.8 141l-.3 .1M141.9 140.7h61.1M142 140.6h61M142 141h-.4M142.1 140.5h60.9M142.2 140.9h-.6M142.2 140.4h60.8M142.4 140.9l-1.1 .4M143.1 140.9a2.6 2.6 0 0 1 2.3 2.2"/>
<path d="M143.2 146.1h16.8M143.3 146h16.5M143.4 140.9h16.4M143.5 141h16.1M143.6 146h16M143.7 145.9h15.7M143.7 141h15.7M143.8 145.9h15.5M143.8 141.1h15.5M143.9 145.8h15.3M144 141.1h15.2M144 141.2h15.1"/>
<path d="M144.1 145.8h15M144.1 145.7h14.9M144.1 141.2h14.9M144.2 141.3h14.7M144.2 145.7h14.7M144.3 145.6h14.6M144.3 141.4h14.5M144.4 145.6h14.3M144.4 145.5h14.3M144.5 145.5h14.1M144.5 141.5h14.1M144.5 145.4h14.1"/>
<path d="M144.6 141.6h14M144.6 141.6h13.9M144.6 145.4h13.9M144.7 145.3h13.8M144.7 141.7h13.8M144.7 145.2h13.7M144.8 145.2h13.6M144.8 145.1h13.5M144.8 141.8h13.5M144.9 145.1l-.5 .5-1.3 .5M144.9 145.1h13.4M144.9 141.9h13.4"/>
<path d="M144.9 141.9h13.3M144.9 145h13.3M144.9 142h13.3M145 144.9h13.2M145 142h13.2M145 142.1h13.1M145 144.8h13.1M145.1 144.8h13M145.1 142.2h13M145.1 144.7h13M145.1 144.7h12.9M145.1 142.3h12.9"/>
<path d="M145.1 144.6h12.9M145.2 144.5h12.8M145.2 144.5h12.7M145.2 142.5h12.7M145.2 144.4h12.7M145.2 142.6h12.7M145.3 144.3h12.6M145.3 144.2h12.6M145.3 144.2h12.5M145.3 142.8h12.5M145.3 142.7h12.6M145.3 144.1h12.5"/>
<path d="M145.3 144h12.5M145.3 142.9h12.5M145.4 144h12.4M145.4 143.9h12.4M145.4 143.1h12.4M145.4 143h12.4M145.4 143.1v.7M145.4 143.8l-.5 1.3M145.4 143.8h12.4M145.4 143.7h12.4M145.4 143.6h12.4M145.4 143.5h12.4"/>
<path d="M145.4 143.4h12.4M145.4 143.3h12.4M145.4 143.2h12.4M157.8 143.1v.7M157.8 143.8l.1 .7M157.8 143h-12.4M157.9 142.7h-12.6M157.9 144.5l.4 .6M157.9 142.5h-12.7M158 142.4h-12.8M158.3 145.1l.5 .5 1.2 .5M158.4 141.8h-13.6"/>
<path d="M158.4 141.7h-13.7M158.7 141.5h-14.2M158.7 141.4h-14.3M159.4 141a2.64 2.64 0 0 0-1.6 2.1M160 140.9l-.6 .1M160.7 140.9a2.61 2.61 0 0 1 2.1 1.6M160.8 146.1h36.3M160.9 146h36.1M161 140.9h35.9M161.1 141h35.7M161.2 146h35.5M161.3 145.9h35.3"/>
<path d="M161.4 141h35.1M161.5 145.9h34.9M161.5 141.1h34.9M161.5 145.8h34.8M161.6 141.1h34.7M161.6 141.2h34.7M161.7 145.8h34.5M161.7 145.7h34.5M161.8 141.2h34.4M161.8 141.3h34.3M161.8 145.7h34.3M161.9 145.6h34.1"/>
<path d="M161.9 141.4h34.1M162 145.6h33.9M162.1 145.5h33.7M162.1 141.5h33.7M162.2 145.4h33.5M162.2 141.6h33.5M162.3 145.3h33.3M162.3 141.7h33.3M162.3 145.2h33.3M162.4 145.2h33.1M162.4 145.1h33.1M162.4 141.8h33.1"/>
<path d="M162.5 145.1l-.5 .5-1.3 .5M162.5 145.1h32.9M162.5 141.9h32.9M162.5 145h32.9M162.5 142h32.8M162.6 144.9h32.7M162.6 142.1h32.7M162.6 144.8h32.7M162.7 144.8h32.5M162.7 142.2h32.5M162.7 144.7h32.5M162.7 142.3h32.5"/>
<path d="M162.8 144.6h32.3M162.8 142.3h32.3M162.8 144.5h32.3M162.8 142.5h32.3M162.8 142.5l.2 .6M162.8 144.5l-.3 .6M162.8 144.4l32.3 .1M162.9 144.4h32.2M162.9 144.4h32.1M162.9 142.6h32.1M162.9 144.3h32.1M162.9 142.7h32.1"/>
<path d="M162.9 144.2h32.1M162.9 142.8h32.1M162.9 144.1h32.1M162.9 144h32M162.9 142.9h32M163 144h31.9M163 143h31.9M163 143.9h31.9M163 143.1h31.9M163 143.1v.7M163 143.8l-.2 .7M163 143.8h31.9"/>
<path d="M163 143.7h31.9M163 143.6h31.9M163 143.5h31.9M163 143.4h31.9M163 143.3h31.9M163 143.2h31.9M180.4 140.3h22.6M180.6 140.2h22.4M180.7 140.2h22.3M180.8 140.1h22.2M180.9 140.1h22.1M181 140.1l-.7 .2"/>
<path d="M194.9 143.1v.7M194.9 143.8l.2 .7M194.9 143l-31.9 .1M195 142.9h-32.1M195 142.7h-32.1M195.1 142.6h-32.2M195.1 142.5l-.2 .6M195.1 144.5l.3 .6M195.1 142.4h-32.3M195.3 142h-32.7M195.4 141.9h-32.9M195.4 145.1l.5 .5 1.3 .5"/>
<path d="M195.5 141.8h-33.1M195.6 141.7h-33.3M195.8 141.5h-33.7M195.9 141.4h-33.9M197.2 140.9a2.54 2.54 0 0 0-2.1 1.6M197.9 140.9a2.54 2.54 0 0 1 2.1 1.6M197.9 146.1h5.1M198.1 146h4.9M198.1 140.9h4.9M198.3 141h4.7M198.3 146h4.7M198.5 145.9h4.5"/>
<path d="M198.5 141h4.5M198.6 145.9h4.4M198.6 141.1h4.4M198.7 145.8h4.3M198.7 141.1h4.3M198.8 141.2h4.2M198.8 145.8h4.2M198.9 145.7h4.1M198.9 141.2h4.1M199 141.3h4M199 145.7h4M199.1 145.6h3.9"/>
<path d="M199.1 141.4h3.9M199.2 141.4h3.8M199.2 145.5h3.8M199.2 141.5h3.8M199.3 145.4h3.7M199.3 141.6h3.7M199.4 145.4h3.6M199.4 145.3h3.6M199.4 141.7h3.6M199.5 145.2h3.5M199.5 141.7h3.5M199.5 141.8h3.5"/>
<path d="M199.6 141.8h3.4M199.6 145.1h3.4M199.6 145.1l-.5 .5-1.2 .5M199.6 141.9h3.4M199.7 145h3.3M199.7 142h3.3M199.7 144.9h3.3M199.7 142.1h3.3M199.8 144.8h3.2M199.8 142.1h3.2M199.8 142.2h3.2M199.8 144.7h3.2"/>
<path d="M199.9 144.7h3.1M199.9 142.3h3.1M199.9 144.6h3.1M199.9 142.4h3.1M200 142.5l.2 .6M200 144.5l-.4 .6M200 144.5h3M200 142.5h3M200 144.4h3M200 142.6h3M200 144.3h3M200 142.7h3"/>
<path d="M200 144.2h3M200 142.8h3M200.1 144.1h2.9M200.1 142.9h2.9M200.1 142.8h2.9M200.1 144h2.9M200.1 143.9h2.9M200.1 143h2.9M200.1 143.8h2.9M200.1 143.1h2.9M200.2 143.1v.7M200.2 143.8l-.2 .7"/>
<path d="M200.2 143.8h2.8M200.2 143.7h2.8M200.2 143.6h2.8M200.2 143.5h2.8M200.2 143.4h2.8M200.2 143.3h2.8M200.2 143.2h2.8M203 140.9h-61.3M203 140.3h-60.7l-1 1"/>
</g>
<path d="M104.5 123.3h1.4" fill="none" stroke="#000" stroke-width="1.3"/>
<circle cx="105.2" cy="123.3" r=".4" fill="#fff" stroke="#000" stroke-width=".21"/>
<path d="M104.5 120.8h1.4" fill="none" stroke="#000" stroke-width="1.3"/>
<circle cx="105.2" cy="120.8" r=".4" fill="#fff" stroke="#000" stroke-width=".21"/>
<path d="M104.5 113.1h1.4" fill="none" stroke="#000" stroke-width="1.3"/>
<circle cx="105.2" cy="113.1" r=".4" fill="#fff" stroke="#000" stroke-width=".21"/>
<path d="M104.5 108.1h1.4" fill="none" stroke="#000" stroke-width="1.3"/>
<circle cx="105.2" cy="108.1" r=".4" fill="#fff" stroke="#000" stroke-width=".21"/>
<path d="M126.9 124.3h1.3" fill="none" stroke="#000" stroke-width="1.3"/>
<circle cx="127.6" cy="124.3" r=".4" fill="#fff" stroke="#000" stroke-width=".21"/>
<path d="M126.9 121.7h1.3" fill="none" stroke="#000" stroke-width="1.3"/>
<circle cx="127.6" cy="121.7" r=".4" fill="#fff" stroke="#000" stroke-width=".21"/>
<path d="M126.9 109h1.3" fill="none" stroke="#000" stroke-width="1.3"/>
<circle cx="127.6" cy="109" r=".4" fill="#fff" stroke="#000" stroke-width=".21"/>
<path d="M126.9 106.5h1.3" fill="none" stroke="#000" stroke-width="1.3"/>
<circle cx="127.6" cy="106.5" r=".4" fill="#fff" stroke="#000" stroke-width=".21"/>
<path d="M126.9 119.2h1.3" fill="none" stroke="#000" stroke-width="1.3"/>
<circle cx="127.6" cy="119.2" r=".4" fill="#fff" stroke="#000" stroke-width=".21"/>
<path d="M126.9 116.6h1.3" fill="none" stroke="#000" stroke-width="1.3"/>
<circle cx="127.6" cy="116.6" r=".4" fill="#fff" stroke="#000" stroke-width=".21"/>
<path d="M126.9 111.6h1.3" fill="none" stroke="#000" stroke-width="1.3"/>
<circle cx="127.6" cy="111.6" r=".4" fill="#fff" stroke="#000" stroke-width=".21"/>
<path d="M126.9 114.1h1.3" fill="none" stroke="#000" stroke-width="1.3"/>
<circle cx="127.6" cy="114.1" r=".4" fill="#fff" stroke="#000" stroke-width=".21"/>
<path d="M126.9 103.9h1.3" fill="none" stroke="#000" stroke-width="1.3"/>
<circle cx="127.6" cy="103.9" r=".4" fill="#fff" stroke="#000" stroke-width=".21"/>
<path d="M126.9 101.4h1.3" fill="none" stroke="#000" stroke-width="1.3"/>
<circle cx="127.6" cy="101.4" r=".4" fill="#fff" stroke="#000" stroke-width=".21"/>
<path d="M126.9 98.9h1.3" fill="none" stroke="#000" stroke-width="1.3"/>
<circle cx="127.6" cy="98.9" r=".4" fill="#fff" stroke="#000" stroke-width=".21"/>
<path d="M126.9 96.3h1.3" fill="none" stroke="#000" stroke-width="1.3"/>
<circle cx="127.6" cy="96.3" r=".4" fill="#fff" stroke="#000" stroke-width=".21"/>
<path d="M126.9 93.8h1.3" fill="none" stroke="#000" stroke-width="1.3"/>
<circle cx="127.6" cy="93.8" r=".4" fill="#fff" stroke="#000" stroke-width=".21"/>
<path d="M126.9 91.2h1.3" fill="none" stroke="#000" stroke-width="1.3"/>
<circle cx="127.6" cy="91.2" r=".4" fill="#fff" stroke="#000" stroke-width=".21"/>
<path d="M126.9 88.7h1.3" fill="none" stroke="#000" stroke-width="1.3"/>
<circle cx="127.6" cy="88.7" r=".4" fill="#fff" stroke="#000" stroke-width=".21"/>
<path d="M126.9 86.2h1.3" fill="none" stroke="#000" stroke-width="1.3"/>
<circle cx="127.6" cy="86.2" r=".4" fill="#fff" stroke="#000" stroke-width=".21"/>
<path d="M126.9 83.6h1.3" fill="none" stroke="#000" stroke-width="1.3"/>
<circle cx="127.6" cy="83.6" r=".4" fill="#fff" stroke="#000" stroke-width=".21"/>
<path d="M126.9 81.1h1.3" fill="none" stroke="#000" stroke-width="1.3"/>
<circle cx="127.6" cy="81.1" r=".4" fill="#fff" stroke="#000" stroke-width=".21"/>
<path d="M126.9 78.5h1.3" fill="none" stroke="#000" stroke-width="1.3"/>
<circle cx="127.6" cy="78.5" r=".4" fill="#fff" stroke="#000" stroke-width=".21"/>
<path d="M126.9 76h1.3" fill="none" stroke="#000" stroke-width="1.3"/>
<circle cx="127.6" cy="76" r=".4" fill="#fff" stroke="#000" stroke-width=".21"/>
<path d="M111.7 76h1.3" fill="none" stroke="#000" stroke-width="1.3"/>
<circle cx="112.3" cy="76" r=".4" fill="#fff" stroke="#000" stroke-width=".21"/>
<path d="M111.7 78.5h1.3" fill="none" stroke="#000" stroke-width="1.3"/>
<circle cx="112.3" cy="78.5" r=".4" fill="#fff" stroke="#000" stroke-width=".21"/>
<path d="M111.7 81.1h1.3" fill="none" stroke="#000" stroke-width="1.3"/>
<circle cx="112.3" cy="81.1" r=".4" fill="#fff" stroke="#000" stroke-width=".21"/>
<path d="M111.7 83.6h1.3" fill="none" stroke="#000" stroke-width="1.3"/>
<circle cx="112.3" cy="83.6" r=".4" fill="#fff" stroke="#000" stroke-width=".21"/>
<path d="M111.7 86.2h1.3" fill="none" stroke="#000" stroke-width="1.3"/>
<circle cx="112.3" cy="86.2" r=".4" fill="#fff" stroke="#000" stroke-width=".21"/>
<path d="M111.7 88.7h1.3" fill="none" stroke="#000" stroke-width="1.3"/>
<circle cx="112.3" cy="88.7" r=".4" fill="#fff" stroke="#000" stroke-width=".21"/>
<path d="M111.7 91.2h1.3" fill="none" stroke="#000" stroke-width="1.3"/>
<circle cx="112.3" cy="91.2" r=".4" fill="#fff" stroke="#000" stroke-width=".21"/>
<path d="M111.7 93.8h1.3" fill="none" stroke="#000" stroke-width="1.3"/>
<circle cx="112.3" cy="93.8" r=".4" fill="#fff" stroke="#000" stroke-width=".21"/>
<path d="M111.7 96.3h1.3" fill="none" stroke="#000" stroke-width="1.3"/>
<circle cx="112.3" cy="96.3" r=".4" fill="#fff" stroke="#000" stroke-width=".21"/>
<path d="M111.7 98.9h1.3" fill="none" stroke="#000" stroke-width="1.3"/>
<circle cx="112.3" cy="98.9" r=".4" fill="#fff" stroke="#000" stroke-width=".21"/>
<path d="M111.7 101.4h1.3" fill="none" stroke="#000" stroke-width="1.3"/>
<circle cx="112.3" cy="101.4" r=".4" fill="#fff" stroke="#000" stroke-width=".21"/>
<path d="M111.7 103.9h1.3" fill="none" stroke="#000" stroke-width="1.3"/>
<circle cx="112.3" cy="103.9" r=".4" fill="#fff" stroke="#000" stroke-width=".21"/>
<path d="M111.7 106.5h1.3" fill="none" stroke="#000" stroke-width="1.3"/>
<circle cx="112.3" cy="106.5" r=".4" fill="#fff" stroke="#000" stroke-width=".21"/>
<path d="M111.7 109h1.3" fill="none" stroke="#000" stroke-width="1.3"/>
<circle cx="112.3" cy="109" r=".4" fill="#fff" stroke="#000" stroke-width=".21"/>
<path d="M111.7 111.6h1.3" fill="none" stroke="#000" stroke-width="1.3"/>
<circle cx="112.3" cy="111.6" r=".4" fill="#fff" stroke="#000" stroke-width=".21"/>
<path d="M111.7 114.1h1.3" fill="none" stroke="#000" stroke-width="1.3"/>
<circle cx="112.3" cy="114.1" r=".4" fill="#fff" stroke="#000" stroke-width=".21"/>
<path d="M111.7 116.6h1.3" fill="none" stroke="#000" stroke-width="1.3"/>
<circle cx="112.3" cy="116.6" r=".4" fill="#fff" stroke="#000" stroke-width=".21"/>
<path d="M111.7 119.2h1.3" fill="none" stroke="#000" stroke-width="1.3"/>
<circle cx="112.3" cy="119.2" r=".4" fill="#fff" stroke="#000" stroke-width=".21"/>
<path d="M111.7 121.7h1.3" fill="none" stroke="#000" stroke-width="1.3"/>
<circle cx="112.3" cy="121.7" r=".4" fill="#fff" stroke="#000" stroke-width=".21"/>
<path d="M111.7 124.3h1.3" fill="none" stroke="#000" stroke-width="1.3"/>
<circle cx="112.3" cy="124.3" r=".4" fill="#fff" stroke="#000" stroke-width=".21"/>
<circle cx="141.1" cy="87.4" r=".91" fill="#000" stroke="#000" stroke-width=".21"/>
<circle cx="141.1" cy="87.4" r=".4" fill="#fff" stroke="#000" stroke-width=".21"/>
<circle cx="136.3" cy="87.4" r=".91" fill="#000" stroke="#000" stroke-width=".21"/>
<circle cx="136.3" cy="87.4" r=".4" fill="#fff" stroke="#000" stroke-width=".21"/>
<circle cx="142.5" cy="83.3" r=".71" fill="#000" stroke="#000" stroke-width=".21"/>
<circle cx="142.5" cy="83.3" r=".4" fill="#fff" stroke="#000" stroke-width=".21"/>
<circle cx="140" cy="83.3" r=".71" fill="#000" stroke="#000" stroke-width=".21"/>
<circle cx="140" cy="83.3" r=".4" fill="#fff" stroke="#000" stroke-width=".21"/>
<circle cx="134.9" cy="83.3" r=".71" fill="#000" stroke="#000" stroke-width=".21"/>
<circle cx="134.9" cy="83.3" r=".4" fill="#fff" stroke="#000" stroke-width=".21"/>
<circle cx="137.4" cy="83.3" r=".71" fill="#000" stroke="#000" stroke-width=".21"/>
<circle cx="137.4" cy="83.3" r=".4" fill="#fff" stroke="#000" stroke-width=".21"/>
<circle cx="134.2" cy="101.4" r=".71" fill="#000" stroke="#000" stroke-width=".21"/>
<circle cx="134.2" cy="101.4" r=".4" fill="#fff" stroke="#000" stroke-width=".21"/>
<circle cx="134.2" cy="98.9" r=".71" fill="#000" stroke="#000" stroke-width=".21"/>
<circle cx="134.2" cy="98.9" r=".4" fill="#fff" stroke="#000" stroke-width=".21"/>
<circle cx="151.1" cy="85.9" r=".71" fill="#000" stroke="#000" stroke-width=".21"/>
<circle cx="151.1" cy="85.9" r=".4" fill="#fff" stroke="#000" stroke-width=".21"/>
<circle cx="153.6" cy="85.9" r=".71" fill="#000" stroke="#000" stroke-width=".21"/>
<circle cx="153.6" cy="85.9" r=".4" fill="#fff" stroke="#000" stroke-width=".21"/>
<path d="M155.5 111.6h1.3" fill="none" stroke="#000" stroke-width="1.3"/>
<circle cx="156.1" cy="111.6" r=".4" fill="#fff" stroke="#000" stroke-width=".21"/>
<path d="M155.5 109h1.3" fill="none" stroke="#000" stroke-width="1.3"/>
<circle cx="156.1" cy="109" r=".4" fill="#fff" stroke="#000" stroke-width=".21"/>
<path d="M155.5 96.3h1.3" fill="none" stroke="#000" stroke-width="1.3"/>
<circle cx="156.1" cy="96.3" r=".4" fill="#fff" stroke="#000" stroke-width=".21"/>
<path d="M155.5 93.8h1.3" fill="none" stroke="#000" stroke-width="1.3"/>
<circle cx="156.1" cy="93.8" r=".4" fill="#fff" stroke="#000" stroke-width=".21"/>
<path d="M155.5 106.5h1.3" fill="none" stroke="#000" stroke-width="1.3"/>
<circle cx="156.1" cy="106.5" r=".4" fill="#fff" stroke="#000" stroke-width=".21"/>
<path d="M155.5 103.9h1.3" fill="none" stroke="#000" stroke-width="1.3"/>
<circle cx="156.1" cy="103.9" r=".4" fill="#fff" stroke="#000" stroke-width=".21"/>
<path d="M155.5 98.9h1.3" fill="none" stroke="#000" stroke-width="1.3"/>
<circle cx="156.1" cy="98.9" r=".4" fill="#fff" stroke="#000" stroke-width=".21"/>
<path d="M155.5 101.4h1.3" fill="none" stroke="#000" stroke-width="1.3"/>
<circle cx="156.1" cy="101.4" r=".4" fill="#fff" stroke="#000" stroke-width=".21"/>
<path d="M155.5 91.2h1.3" fill="none" stroke="#000" stroke-width="1.3"/>
<circle cx="156.1" cy="91.2" r=".4" fill="#fff" stroke="#000" stroke-width=".21"/>
<path d="M155.5 88.7h1.3" fill="none" stroke="#000" stroke-width="1.3"/>
<circle cx="156.1" cy="88.7" r=".4" fill="#fff" stroke="#000" stroke-width=".21"/>
<path d="M147.9 88.7h1.3" fill="none" stroke="#000" stroke-width="1.3"/>
<circle cx="148.5" cy="88.7" r=".4" fill="#fff" stroke="#000" stroke-width=".21"/>
<path d="M147.9 91.2h1.3" fill="none" stroke="#000" stroke-width="1.3"/>
<circle cx="148.5" cy="91.2" r=".4" fill="#fff" stroke="#000" stroke-width=".21"/>
<path d="M147.9 93.8h1.3" fill="none" stroke="#000" stroke-width="1.3"/>
<circle cx="148.5" cy="93.8" r=".4" fill="#fff" stroke="#000" stroke-width=".21"/>
<path d="M147.9 96.3h1.3" fill="none" stroke="#000" stroke-width="1.3"/>
<circle cx="148.5" cy="96.3" r=".4" fill="#fff" stroke="#000" stroke-width=".21"/>
<path d="M147.9 98.9h1.3" fill="none" stroke="#000" stroke-width="1.3"/>
<circle cx="148.5" cy="98.9" r=".4" fill="#fff" stroke="#000" stroke-width=".21"/>
<path d="M147.9 101.4h1.3" fill="none" stroke="#000" stroke-width="1.3"/>
<circle cx="148.5" cy="101.4" r=".4" fill="#fff" stroke="#000" stroke-width=".21"/>
<path d="M147.9 103.9h1.3" fill="none" stroke="#000" stroke-width="1.3"/>
<circle cx="148.5" cy="103.9" r=".4" fill="#fff" stroke="#000" stroke-width=".21"/>
<path d="M147.9 106.5h1.3" fill="none" stroke="#000" stroke-width="1.3"/>
<circle cx="148.5" cy="106.5" r=".4" fill="#fff" stroke="#000" stroke-width=".21"/>
<path d="M147.9 109h1.3" fill="none" stroke="#000" stroke-width="1.3"/>
<circle cx="148.5" cy="109" r=".4" fill="#fff" stroke="#000" stroke-width=".21"/>
<path d="M147.9 111.6h1.3" fill="none" stroke="#000" stroke-width="1.3"/>
<circle cx="148.5" cy="111.6" r=".4" fill="#fff" stroke="#000" stroke-width=".21"/>
<path d="M158.9 111.6h1.5" fill="none" stroke="#000" stroke-width="1.5"/>
<circle cx="159.6" cy="111.6" r=".51" fill="#fff" stroke="#000" stroke-width=".21"/>
<path d="M158.9 109h1.5" fill="none" stroke="#000" stroke-width="1.5"/>
<circle cx="159.6" cy="109" r=".51" fill="#fff" stroke="#000" stroke-width=".21"/>
<path d="M158.9 106.5h1.5" fill="none" stroke="#000" stroke-width="1.5"/>
<circle cx="159.6" cy="106.5" r=".51" fill="#fff" stroke="#000" stroke-width=".21"/>
<path d="M158.9 103.9h1.5" fill="none" stroke="#000" stroke-width="1.5"/>
<circle cx="159.6" cy="103.9" r=".51" fill="#fff" stroke="#000" stroke-width=".21"/>
<path d="M158.9 101.4h1.5" fill="none" stroke="#000" stroke-width="1.5"/>
<circle cx="159.6" cy="101.4" r=".51" fill="#fff" stroke="#000" stroke-width=".21"/>
<path d="M158.9 98.9h1.5" fill="none" stroke="#000" stroke-width="1.5"/>
<circle cx="159.6" cy="98.9" r=".51" fill="#fff" stroke="#000" stroke-width=".21"/>
<path d="M158.9 96.3h1.5" fill="none" stroke="#000" stroke-width="1.5"/>
<circle cx="159.6" cy="96.3" r=".51" fill="#fff" stroke="#000" stroke-width=".21"/>
<path d="M158.9 93.8h1.5" fill="none" stroke="#000" stroke-width="1.5"/>
<circle cx="159.6" cy="93.8" r=".51" fill="#fff" stroke="#000" stroke-width=".21"/>
<path d="M158.9 91.2h1.5" fill="none" stroke="#000" stroke-width="1.5"/>
<circle cx="159.6" cy="91.2" r=".51" fill="#fff" stroke="#000" stroke-width=".21"/>
<path d="M158.9 88.7h1.5" fill="none" stroke="#000" stroke-width="1.5"/>
<circle cx="159.6" cy="88.7" r=".51" fill="#fff" stroke="#000" stroke-width=".21"/>
<circle cx="156.1" cy="85.9" r=".71" fill="#000" stroke="#000" stroke-width=".21"/>
<circle cx="156.1" cy="85.9" r=".4" fill="#fff" stroke="#000" stroke-width=".21"/>
<circle cx="156.1" cy="83.3" r=".71" fill="#000" stroke="#000" stroke-width=".21"/>
<circle cx="156.1" cy="83.3" r=".4" fill="#fff" stroke="#000" stroke-width=".21"/>
<circle cx="163.1" cy="101.4" r=".71" fill="#000" stroke="#000" stroke-width=".21"/>
<circle cx="163.1" cy="101.4" r=".4" fill="#fff" stroke="#000" stroke-width=".21"/>
<circle cx="163.1" cy="88.7" r=".71" fill="#000" stroke="#000" stroke-width=".21"/>
<circle cx="163.1" cy="88.7" r=".4" fill="#fff" stroke="#000" stroke-width=".21"/>
<circle cx="137.4" cy="103.9" r=".71" fill="#000" stroke="#000" stroke-width=".21"/>
<circle cx="137.4" cy="103.9" r=".4" fill="#fff" stroke="#000" stroke-width=".21"/>
<circle cx="137.4" cy="98.9" r=".71" fill="#000" stroke="#000" stroke-width=".21"/>
<circle cx="137.4" cy="98.9" r=".4" fill="#fff" stroke="#000" stroke-width=".21"/>
<circle cx="140.6" cy="103.9" r=".71" fill="#000" stroke="#000" stroke-width=".21"/>
<circle cx="140.6" cy="103.9" r=".4" fill="#fff" stroke="#000" stroke-width=".21"/>
<circle cx="140.6" cy="101.4" r=".71" fill="#000" stroke="#000" stroke-width=".21"/>
<circle cx="140.6" cy="101.4" r=".4" fill="#fff" stroke="#000" stroke-width=".21"/>
<path d="M129.7 111.6h1.5" fill="none" stroke="#000" stroke-width="1.5"/>
<circle cx="130.4" cy="111.6" r=".51" fill="#fff" stroke="#000" stroke-width=".21"/>
<path d="M129.7 109h1.5" fill="none" stroke="#000" stroke-width="1.5"/>
<circle cx="130.4" cy="109" r=".51" fill="#fff" stroke="#000" stroke-width=".21"/>
<path d="M129.7 106.5h1.5" fill="none" stroke="#000" stroke-width="1.5"/>
<circle cx="130.4" cy="106.5" r=".51" fill="#fff" stroke="#000" stroke-width=".21"/>
<path d="M129.7 103.9h1.5" fill="none" stroke="#000" stroke-width="1.5"/>
<circle cx="130.4" cy="103.9" r=".51" fill="#fff" stroke="#000" stroke-width=".21"/>
<path d="M129.7 101.4h1.5" fill="none" stroke="#000" stroke-width="1.5"/>
<circle cx="130.4" cy="101.4" r=".51" fill="#fff" stroke="#000" stroke-width=".21"/>
<path d="M129.7 98.9h1.5" fill="none" stroke="#000" stroke-width="1.5"/>
<circle cx="130.4" cy="98.9" r=".51" fill="#fff" stroke="#000" stroke-width=".21"/>
<path d="M129.7 91.2h1.5" fill="none" stroke="#000" stroke-width="1.5"/>
<circle cx="130.4" cy="91.2" r=".51" fill="#fff" stroke="#000" stroke-width=".21"/>
<path d="M129.7 88.7h1.5" fill="none" stroke="#000" stroke-width="1.5"/>
<circle cx="130.4" cy="88.7" r=".51" fill="#fff" stroke="#000" stroke-width=".21"/>
<path d="M129.7 86.2h1.5" fill="none" stroke="#000" stroke-width="1.5"/>
<circle cx="130.4" cy="86.2" r=".51" fill="#fff" stroke="#000" stroke-width=".21"/>
<path d="M129.7 83.6h1.5" fill="none" stroke="#000" stroke-width="1.5"/>
<circle cx="130.4" cy="83.6" r=".51" fill="#fff" stroke="#000" stroke-width=".21"/>
<path d="M189.8 102.4h2.6" fill="none" stroke="#000" stroke-width="2.5"/>
<circle cx="191.1" cy="102.4" r=".66" fill="#fff" stroke="#000" stroke-width=".21"/>
<path d="M194.9 102.4h2.5" fill="none" stroke="#000" stroke-width="2.5"/>
<circle cx="196.1" cy="102.4" r=".66" fill="#fff" stroke="#000" stroke-width=".21"/>
<path d="M189.8 97.9h2.6" fill="none" stroke="#000" stroke-width="2.5"/>
<circle cx="191.1" cy="97.9" r=".66" fill="#fff" stroke="#000" stroke-width=".21"/>
<path d="M194.9 97.9h2.5" fill="none" stroke="#000" stroke-width="2.5"/>
<circle cx="196.1" cy="97.9" r=".66" fill="#fff" stroke="#000" stroke-width=".21"/>
<circle cx="101.5" cy="123.3" r=".71" fill="#000" stroke="#000" stroke-width=".21"/>
<circle cx="101.5" cy="123.3" r=".4" fill="#fff" stroke="#000" stroke-width=".21"/>
<circle cx="101.5" cy="120.8" r=".71" fill="#000" stroke="#000" stroke-width=".21"/>
<circle cx="101.5" cy="120.8" r=".4" fill="#fff" stroke="#000" stroke-width=".21"/>
<circle cx="101.5" cy="108.1" r=".71" fill="#000" stroke="#000" stroke-width=".21"/>
<circle cx="101.5" cy="108.1" r=".4" fill="#fff" stroke="#000" stroke-width=".21"/>
<circle cx="101.5" cy="113.2" r=".71" fill="#000" stroke="#000" stroke-width=".21"/>
<circle cx="101.5" cy="113.2" r=".4" fill="#fff" stroke="#000" stroke-width=".21"/>
<path d="M106.5 76h1.5" fill="none" stroke="#000" stroke-width="1.5"/>
<circle cx="107.3" cy="76" r=".51" fill="#fff" stroke="#000" stroke-width=".21"/>
<path d="M106.5 78.5h1.5" fill="none" stroke="#000" stroke-width="1.5"/>
<circle cx="107.3" cy="78.5" r=".51" fill="#fff" stroke="#000" stroke-width=".21"/>
<path d="M106.5 81.1h1.5" fill="none" stroke="#000" stroke-width="1.5"/>
<circle cx="107.3" cy="81.1" r=".51" fill="#fff" stroke="#000" stroke-width=".21"/>
<path d="M106.5 73.5h1.5" fill="none" stroke="#000" stroke-width="1.5"/>
<circle cx="107.3" cy="73.5" r=".51" fill="#fff" stroke="#000" stroke-width=".21"/>
<path d="M117.6 57.6h1.5" fill="none" stroke="#000" stroke-width="1.5"/>
<circle cx="118.4" cy="57.6" r=".51" fill="#fff" stroke="#000" stroke-width=".21"/>
<path d="M117.6 60.2h1.5" fill="none" stroke="#000" stroke-width="1.5"/>
<circle cx="118.4" cy="60.2" r=".51" fill="#fff" stroke="#000" stroke-width=".21"/>
<path d="M117.6 62.7h1.5" fill="none" stroke="#000" stroke-width="1.5"/>
<circle cx="118.4" cy="62.7" r=".51" fill="#fff" stroke="#000" stroke-width=".21"/>
<path d="M117.6 55.1h1.5" fill="none" stroke="#000" stroke-width="1.5"/>
<circle cx="118.4" cy="55.1" r=".51" fill="#fff" stroke="#000" stroke-width=".21"/>
<path d="M117 142.4h1.5" fill="none" stroke="#000" stroke-width="1.5"/>
<circle cx="117.7" cy="142.4" r=".51" fill="#fff" stroke="#000" stroke-width=".21"/>
<path d="M117 139.8h1.5" fill="none" stroke="#000" stroke-width="1.5"/>
<circle cx="117.7" cy="139.8" r=".51" fill="#fff" stroke="#000" stroke-width=".21"/>
<path d="M117 137.3h1.5" fill="none" stroke="#000" stroke-width="1.5"/>
<circle cx="117.7" cy="137.3" r=".51" fill="#fff" stroke="#000" stroke-width=".21"/>
<path d="M117 144.9h1.5" fill="none" stroke="#000" stroke-width="1.5"/>
<circle cx="117.7" cy="144.9" r=".51" fill="#fff" stroke="#000" stroke-width=".21"/>
<path d="M124 57.6h1.5" fill="none" stroke="#000" stroke-width="1.5"/>
<circle cx="124.7" cy="57.6" r=".51" fill="#fff" stroke="#000" stroke-width=".21"/>
<path d="M124 60.2h1.5" fill="none" stroke="#000" stroke-width="1.5"/>
<circle cx="124.7" cy="60.2" r=".51" fill="#fff" stroke="#000" stroke-width=".21"/>
<path d="M124 62.7h1.5" fill="none" stroke="#000" stroke-width="1.5"/>
<circle cx="124.7" cy="62.7" r=".51" fill="#fff" stroke="#000" stroke-width=".21"/>
<path d="M124 55.1h1.5" fill="none" stroke="#000" stroke-width="1.5"/>
<circle cx="124.7" cy="55.1" r=".51" fill="#fff" stroke="#000" stroke-width=".21"/>
<path d="M123.3 142.4h1.5" fill="none" stroke="#000" stroke-width="1.5"/>
<circle cx="124.1" cy="142.4" r=".51" fill="#fff" stroke="#000" stroke-width=".21"/>
<path d="M123.3 139.8h1.5" fill="none" stroke="#000" stroke-width="1.5"/>
<circle cx="124.1" cy="139.8" r=".51" fill="#fff" stroke="#000" stroke-width=".21"/>
<path d="M123.3 137.3h1.5" fill="none" stroke="#000" stroke-width="1.5"/>
<circle cx="124.1" cy="137.3" r=".51" fill="#fff" stroke="#000" stroke-width=".21"/>
<path d="M123.3 144.9h1.5" fill="none" stroke="#000" stroke-width="1.5"/>
<circle cx="124.1" cy="144.9" r=".51" fill="#fff" stroke="#000" stroke-width=".21"/>
<path d="M130.3 57.6h1.5" fill="none" stroke="#000" stroke-width="1.5"/>
<circle cx="131.1" cy="57.6" r=".51" fill="#fff" stroke="#000" stroke-width=".21"/>
<path d="M130.3 60.2h1.5" fill="none" stroke="#000" stroke-width="1.5"/>
<circle cx="131.1" cy="60.2" r=".51" fill="#fff" stroke="#000" stroke-width=".21"/>
<path d="M130.3 62.7h1.5" fill="none" stroke="#000" stroke-width="1.5"/>
<circle cx="131.1" cy="62.7" r=".51" fill="#fff" stroke="#000" stroke-width=".21"/>
<path d="M130.3 55.1h1.5" fill="none" stroke="#000" stroke-width="1.5"/>
<circle cx="131.1" cy="55.1" r=".51" fill="#fff" stroke="#000" stroke-width=".21"/>
<path d="M129.7 142.4h1.5" fill="none" stroke="#000" stroke-width="1.5"/>
<circle cx="130.4" cy="142.4" r=".51" fill="#fff" stroke="#000" stroke-width=".21"/>
<path d="M129.7 139.8h1.5" fill="none" stroke="#000" stroke-width="1.5"/>
<circle cx="130.4" cy="139.8" r=".51" fill="#fff" stroke="#000" stroke-width=".21"/>
<path d="M129.7 137.3h1.5" fill="none" stroke="#000" stroke-width="1.5"/>
<circle cx="130.4" cy="137.3" r=".51" fill="#fff" stroke="#000" stroke-width=".21"/>
<path d="M129.7 144.9h1.5" fill="none" stroke="#000" stroke-width="1.5"/>
<circle cx="130.4" cy="144.9" r=".51" fill="#fff" stroke="#000" stroke-width=".21"/>
<circle cx="108.5" cy="103.9" r=".71" fill="#000" stroke="#000" stroke-width=".21"/>
<circle cx="108.5" cy="103.9" r=".4" fill="#fff" stroke="#000" stroke-width=".21"/>
<circle cx="108.5" cy="101.4" r=".71" fill="#000" stroke="#000" stroke-width=".21"/>
<circle cx="108.5" cy="101.4" r=".4" fill="#fff" stroke="#000" stroke-width=".21"/>
<path d="M134.2 116.5v1.5" fill="none" stroke="#000" stroke-width="1.5"/>
<circle cx="134.2" cy="117.3" r=".51" fill="#fff" stroke="#000" stroke-width=".21"/>
<path d="M131.7 116.5v1.5" fill="none" stroke="#000" stroke-width="1.5"/>
<circle cx="131.7" cy="117.3" r=".51" fill="#fff" stroke="#000" stroke-width=".21"/>
<path d="M134.2 122.9v1.5" fill="none" stroke="#000" stroke-width="1.5"/>
<circle cx="134.2" cy="123.6" r=".51" fill="#fff" stroke="#000" stroke-width=".21"/>
<path d="M131.7 122.9v1.5" fill="none" stroke="#000" stroke-width="1.5"/>
<circle cx="131.7" cy="123.6" r=".51" fill="#fff" stroke="#000" stroke-width=".21"/>
<path d="M100.1 91.2h1.6" fill="none" stroke="#000" stroke-width="1.5"/>
<circle cx="100.9" cy="91.2" r=".51" fill="#fff" stroke="#000" stroke-width=".21"/>
<path d="M100.1 93.8h1.6" fill="none" stroke="#000" stroke-width="1.5"/>
<circle cx="100.9" cy="93.8" r=".51" fill="#fff" stroke="#000" stroke-width=".21"/>
<path d="M100.1 96.3h1.6" fill="none" stroke="#000" stroke-width="1.5"/>
<circle cx="100.9" cy="96.3" r=".51" fill="#fff" stroke="#000" stroke-width=".21"/>
<path d="M100.1 88.7h1.6" fill="none" stroke="#000" stroke-width="1.5"/>
<circle cx="100.9" cy="88.7" r=".51" fill="#fff" stroke="#000" stroke-width=".21"/>
<path d="M100.1 86.2h1.6" fill="none" stroke="#000" stroke-width="1.5"/>
<circle cx="100.9" cy="86.2" r=".51" fill="#fff" stroke="#000" stroke-width=".21"/>
<path d="M100.1 83.6h1.6" fill="none" stroke="#000" stroke-width="1.5"/>
<circle cx="100.9" cy="83.6" r=".51" fill="#fff" stroke="#000" stroke-width=".21"/>
<path d="M100.1 81.1h1.6" fill="none" stroke="#000" stroke-width="1.5"/>
<circle cx="100.9" cy="81.1" r=".51" fill="#fff" stroke="#000" stroke-width=".21"/>
<path d="M100.1 78.5h1.6" fill="none" stroke="#000" stroke-width="1.5"/>
<circle cx="100.9" cy="78.5" r=".51" fill="#fff" stroke="#000" stroke-width=".21"/>
<path d="M100.1 76h1.6" fill="none" stroke="#000" stroke-width="1.5"/>
<circle cx="100.9" cy="76" r=".51" fill="#fff" stroke="#000" stroke-width=".21"/>
<path d="M100.1 73.5h1.6" fill="none" stroke="#000" stroke-width="1.5"/>
<circle cx="100.9" cy="73.5" r=".51" fill="#fff" stroke="#000" stroke-width=".21"/>
<path d="M100.1 65.6h1.6" fill="none" stroke="#000" stroke-width="1.5"/>
<circle cx="100.9" cy="65.6" r=".51" fill="#fff" stroke="#000" stroke-width=".21"/>
<path d="M100.1 68.1h1.6" fill="none" stroke="#000" stroke-width="1.5"/>
<circle cx="100.9" cy="68.1" r=".51" fill="#fff" stroke="#000" stroke-width=".21"/>
<circle cx="138.7" cy="123.6" r=".71" fill="#000" stroke="#000" stroke-width=".21"/>
<circle cx="138.7" cy="123.6" r=".4" fill="#fff" stroke="#000" stroke-width=".21"/>
<circle cx="151.4" cy="123.6" r=".71" fill="#000" stroke="#000" stroke-width=".21"/>
<circle cx="151.4" cy="123.6" r=".4" fill="#fff" stroke="#000" stroke-width=".21"/>
<path d="M141.2 119.4v1.5" fill="none" stroke="#000" stroke-width="1.5"/>
<circle cx="141.2" cy="120.1" r=".51" fill="#fff" stroke="#000" stroke-width=".21"/>
<path d="M138.7 119.4v1.5" fill="none" stroke="#000" stroke-width="1.5"/>
<circle cx="138.7" cy="120.1" r=".51" fill="#fff" stroke="#000" stroke-width=".21"/>
<path d="M158.9 83.6h1.5" fill="none" stroke="#000" stroke-width="1.5"/>
<circle cx="159.6" cy="83.6" r=".51" fill="#fff" stroke="#000" stroke-width=".21"/>
<path d="M158.9 86.2h1.5" fill="none" stroke="#000" stroke-width="1.5"/>
<circle cx="159.6" cy="86.2" r=".51" fill="#fff" stroke="#000" stroke-width=".21"/>
<path d="M121.2 127.6v1.6" fill="none" stroke="#000" stroke-width="1.5"/>
<circle cx="121.2" cy="128.4" r=".51" fill="#fff" stroke="#000" stroke-width=".21"/>
<path d="M123.8 127.6v1.6" fill="none" stroke="#000" stroke-width="1.5"/>
<circle cx="123.8" cy="128.4" r=".51" fill="#fff" stroke="#000" stroke-width=".21"/>
<path d="M126.3 127.6v1.6" fill="none" stroke="#000" stroke-width="1.5"/>
<circle cx="126.3" cy="128.4" r=".51" fill="#fff" stroke="#000" stroke-width=".21"/>
<path d="M118.7 127.6v1.6" fill="none" stroke="#000" stroke-width="1.5"/>
<circle cx="118.7" cy="128.4" r=".51" fill="#fff" stroke="#000" stroke-width=".21"/>
<path d="M116.1 127.6v1.6" fill="none" stroke="#000" stroke-width="1.5"/>
<circle cx="116.1" cy="128.4" r=".51" fill="#fff" stroke="#000" stroke-width=".21"/>
<path d="M113.6 127.6v1.6" fill="none" stroke="#000" stroke-width="1.5"/>
<circle cx="113.6" cy="128.4" r=".51" fill="#fff" stroke="#000" stroke-width=".21"/>
<path d="M111.1 127.6v1.6" fill="none" stroke="#000" stroke-width="1.5"/>
<circle cx="111.1" cy="128.4" r=".51" fill="#fff" stroke="#000" stroke-width=".21"/>
<circle cx="196.2" cy="106.8" r=".76" fill="#000" stroke="#000" stroke-width=".21"/>
<circle cx="196.2" cy="106.8" r=".38" fill="#fff" stroke="#000" stroke-width=".21"/>
<circle cx="191.1" cy="108.7" r=".76" fill="#000" stroke="#000" stroke-width=".21"/>
<circle cx="191.1" cy="108.7" r=".38" fill="#fff" stroke="#000" stroke-width=".21"/>
<circle cx="183.5" cy="108.7" r=".76" fill="#000" stroke="#000" stroke-width=".21"/>
<circle cx="183.5" cy="108.7" r=".38" fill="#fff" stroke="#000" stroke-width=".21"/>
<circle cx="183.5" cy="106.8" r=".76" fill="#000" stroke="#000" stroke-width=".21"/>
<circle cx="183.5" cy="106.8" r=".38" fill="#fff" stroke="#000" stroke-width=".21"/>
<circle cx="191.1" cy="91.6" r=".76" fill="#000" stroke="#000" stroke-width=".21"/>
<circle cx="191.1" cy="91.6" r=".38" fill="#fff" stroke="#000" stroke-width=".21"/>
<circle cx="196.2" cy="93.5" r=".76" fill="#000" stroke="#000" stroke-width=".21"/>
<circle cx="196.2" cy="93.5" r=".38" fill="#fff" stroke="#000" stroke-width=".21"/>
<circle cx="186" cy="91.6" r=".76" fill="#000" stroke="#000" stroke-width=".21"/>
<circle cx="186" cy="91.6" r=".38" fill="#fff" stroke="#000" stroke-width=".21"/>
<circle cx="186" cy="93.5" r=".76" fill="#000" stroke="#000" stroke-width=".21"/>
<circle cx="186" cy="93.5" r=".38" fill="#fff" stroke="#000" stroke-width=".21"/>
<circle cx="151.4" cy="76" r=".76" fill="#000" stroke="#000" stroke-width=".21"/>
<circle cx="151.4" cy="76" r=".38" fill="#fff" stroke="#000" stroke-width=".21"/>
<circle cx="151.4" cy="80.8" r=".76" fill="#000" stroke="#000" stroke-width=".21"/>
<circle cx="151.4" cy="80.8" r=".38" fill="#fff" stroke="#000" stroke-width=".21"/>
<circle cx="145.4" cy="101.4" r=".76" fill="#000" stroke="#000" stroke-width=".21"/>
<circle cx="145.4" cy="101.4" r=".38" fill="#fff" stroke="#000" stroke-width=".21"/>
<circle cx="145.4" cy="95.1" r=".76" fill="#000" stroke="#000" stroke-width=".21"/>
<circle cx="145.4" cy="95.1" r=".38" fill="#fff" stroke="#000" stroke-width=".21"/>
<circle cx="170.1" cy="91.2" r=".76" fill="#000" stroke="#000" stroke-width=".21"/>
<circle cx="170.1" cy="91.2" r=".38" fill="#fff" stroke="#000" stroke-width=".21"/>
<circle cx="170.1" cy="98.9" r=".76" fill="#000" stroke="#000" stroke-width=".21"/>
<circle cx="170.1" cy="98.9" r=".38" fill="#fff" stroke="#000" stroke-width=".21"/>
<circle cx="170.1" cy="101.4" r=".76" fill="#000" stroke="#000" stroke-width=".21"/>
<circle cx="170.1" cy="101.4" r=".38" fill="#fff" stroke="#000" stroke-width=".21"/>
<circle cx="170.1" cy="114.4" r=".76" fill="#000" stroke="#000" stroke-width=".21"/>
<circle cx="170.1" cy="114.4" r=".38" fill="#fff" stroke="#000" stroke-width=".21"/>
<circle cx="153.6" cy="83.3" r=".76" fill="#000" stroke="#000" stroke-width=".21"/>
<circle cx="153.6" cy="83.3" r=".38" fill="#fff" stroke="#000" stroke-width=".21"/>
<circle cx="148.5" cy="83.3" r=".76" fill="#000" stroke="#000" stroke-width=".21"/>
<circle cx="148.5" cy="83.3" r=".38" fill="#fff" stroke="#000" stroke-width=".21"/>
<circle cx="172" cy="75.4" r=".76" fill="#000" stroke="#000" stroke-width=".21"/>
<circle cx="172" cy="75.4" r=".38" fill="#fff" stroke="#000" stroke-width=".21"/>
<circle cx="172" cy="124.9" r=".76" fill="#000" stroke="#000" stroke-width=".21"/>
<circle cx="172" cy="124.9" r=".38" fill="#fff" stroke="#000" stroke-width=".21"/>
<circle cx="189.5" cy="124.9" r=".76" fill="#000" stroke="#000" stroke-width=".21"/>
<circle cx="189.5" cy="124.9" r=".38" fill="#fff" stroke="#000" stroke-width=".21"/>
<circle cx="189.5" cy="75.4" r=".76" fill="#000" stroke="#000" stroke-width=".21"/>
<circle cx="189.5" cy="75.4" r=".38" fill="#fff" stroke="#000" stroke-width=".21"/>
<circle cx="173.3" cy="96.3" r=".76" fill="#000" stroke="#000" stroke-width=".21"/>
<circle cx="173.3" cy="96.3" r=".38" fill="#fff" stroke="#000" stroke-width=".21"/>
<circle cx="173.3" cy="114.4" r=".76" fill="#000" stroke="#000" stroke-width=".21"/>
<circle cx="173.3" cy="114.4" r=".38" fill="#fff" stroke="#000" stroke-width=".21"/>
<circle cx="176.5" cy="106.5" r=".76" fill="#000" stroke="#000" stroke-width=".21"/>
<circle cx="176.5" cy="106.5" r=".38" fill="#fff" stroke="#000" stroke-width=".21"/>
<circle cx="176.5" cy="114.4" r=".76" fill="#000" stroke="#000" stroke-width=".21"/>
<circle cx="176.5" cy="114.4" r=".38" fill="#fff" stroke="#000" stroke-width=".21"/>
<circle cx="145.4" cy="103.9" r=".76" fill="#000" stroke="#000" stroke-width=".21"/>
<circle cx="145.4" cy="103.9" r=".38" fill="#fff" stroke="#000" stroke-width=".21"/>
<circle cx="145.4" cy="114.1" r=".76" fill="#000" stroke="#000" stroke-width=".21"/>
<circle cx="145.4" cy="114.1" r=".38" fill="#fff" stroke="#000" stroke-width=".21"/>
<g fill="none" stroke="#000" stroke-width=".21">
<path d="M96.8 50h107.3v100h-107.3z"/>
<circle cx="160.4" cy="56.4" r="1.61"/>
</g>
<circle cx="160.4" cy="56.4" r="1.61" fill="#fff" stroke="#000" stroke-width=".21"/>
<circle cx="197.5" cy="56.4" r="1.61" fill="none" stroke="#000" stroke-width=".21"/>
<circle cx="197.5" cy="56.4" r="1.61" fill="#fff" stroke="#000" stroke-width=".21"/>
<circle cx="160.4" cy="143.5" r="1.61" fill="none" stroke="#000" stroke-width=".21"/>
<circle cx="160.4" cy="143.5" r="1.61" fill="#fff" stroke="#000" stroke-width=".21"/>
<circle cx="197.5" cy="143.5" r="1.61" fill="none" stroke="#000" stroke-width=".21"/>
<circle cx="197.5" cy="143.5" r="1.61" fill="#fff" stroke="#000" stroke-width=".21"/>
<circle cx="105.6" cy="56.4" r="1.61" fill="none" stroke="#000" stroke-width=".21"/>
<circle cx="105.6" cy="56.4" r="1.61" fill="#fff" stroke="#000" stroke-width=".21"/>
<circle cx="142.8" cy="56.4" r="1.61" fill="none" stroke="#000" stroke-width=".21"/>
<circle cx="142.8" cy="56.4" r="1.61" fill="#fff" stroke="#000" stroke-width=".21"/>
<circle cx="105.6" cy="143.5" r="1.61" fill="none" stroke="#000" stroke-width=".21"/>
<circle cx="105.6" cy="143.5" r="1.61" fill="#fff" stroke="#000" stroke-width=".21"/>
<circle cx="142.8" cy="143.5" r="1.61" fill="none" stroke="#000" stroke-width=".21"/>
<circle cx="142.8" cy="143.5" r="1.61" fill="#fff" stroke="#000" stroke-width=".21"/>
<g fill="none" stroke="#000" stroke-width=".21">
<path d="M22.5 18.9h252.7v171.4h-252.7zM64.6 15.1v3.8M106.7 15.1v3.8M148.8 15.1v3.8M191 15.1v3.8M233.1 15.1v3.8M18.7 61.7h3.8M275.2 61.7h3.8M18.7 104.6h3.8M275.2 104.6h3.8M18.7 147.4h3.8M275.2 147.4h3.8"/>
<path d="M233.9 170v20.3M233.9 175h41.3M235.9 177.2l.6 1.6 .5-1.6M237.5 177.2h.8M238.3 176.4l-.4 .1-.1 .3v2M239.9 176.4v2.4l-.8-.1-.2-.2v-1.1l.2-.2h.8M240.7 179h1M243.3 177.2h-.7l-.2 .4 .1 1 .8 .2M244.1 177.4l.5-.2a.92 .92 0 0 1 .2 1.5l-.4 .1-.3-.2-.1-.4zM245.9 178.8v-1.6l.9 .1 .1 1.5M247.6 177.2h.8M247.9 176.4v2.1l.5 .3"/>
<path d="M249.9 177.5v-.3h-.7v1.6M250.7 177.4l.4-.2a.92 .92 0 0 1 .2 1.5l-.3 .1-.3-.2-.2-.4zM252.4 176.4v2l.1 .2 .3 .2M253.5 176.4v2.1l.4 .3M254.6 178h1a.55 .55 0 0 0-.3-.8 .55 .55 0 0 0-.7 .5l.1 .9 .9 .2M257.2 177.5v-.3h-.7v1.6M257.8 179h1M260.4 177.2h-.6l-.3 .4 .1 1 .8 .2M261.2 178.8l.8-.1 .2-.2v-.9l-.2-.4h-.8v2.3M263.1 177.2v1.3l.3 .3h.7v-1.6M275.2 170h-95.2v20.3M64.6 190.3v3.8"/>
<path d="M106.7 190.3v3.8M148.8 190.3v3.8M191 190.3v3.8M233.1 190.3v3.8M233.9 185.2h41.3M233.9 180.1h41.3M235.9 182.2l.6-.5v2.2M235.9 183.9h1.2M239.7 183.7l.1 .2zM240.8 181.9l.1-.1a.88 .88 0 0 1 .8 1.2l-.1 .3a.51 .51 0 0 1-.5 .6 .51 .51 0 0 1-.5-.6l-.1-.8zM241.6 182.2l-1 1.2M242.4 182v-.3h1.2l-.6 2.2"/>
<path d="M244.3 183.7l.1 .2zM245.1 182.2a.58 .58 0 0 1 .9-.4 .58 .58 0 0 1 .1 .9l-1 1.2h1.2M247.3 181.9l.2-.1a.88 .88 0 0 1 .7 1.2 .61 .61 0 0 1-.6 .9 .61 .61 0 0 1-.5-.9v-.5zM248.1 182.2l-.9 1.2M250 182.2a.58 .58 0 0 1 .8-.4 .58 .58 0 0 1 .2 .9l-1 1.2h1.2M251.9 182.2a.58 .58 0 0 1 .9-.4 .58 .58 0 0 1 .1 .9l-1 1.2h1.2M253.9 182.6l.1 .1zM253.9 183.6l.1 .1zM254.7 182.2a.58 .58 0 0 1 .9-.4 .58 .58 0 0 1 .1 .9l-1 1.2h1.2M256.8 181.9l.4-.1 .5 .1 .2 1-1.1-.1-.1-.3zM257.9 182.9l-.3 .7-.7 .3M265 185.2v5.1"/>
<circle cx="238.4" cy="182.2" r=".47"/>
<circle cx="238.4" cy="183.3" r=".59"/>
</g>
<path d="M18.7 15.1h260.3v179h-260.3z" fill="none" stroke="#000" stroke-width=".32"/>
<use href="#words"/>
</svg>
